VERSION 5.8 ;
BUSBITCHARS "[]" ;
DIVIDERCHAR "/" ;
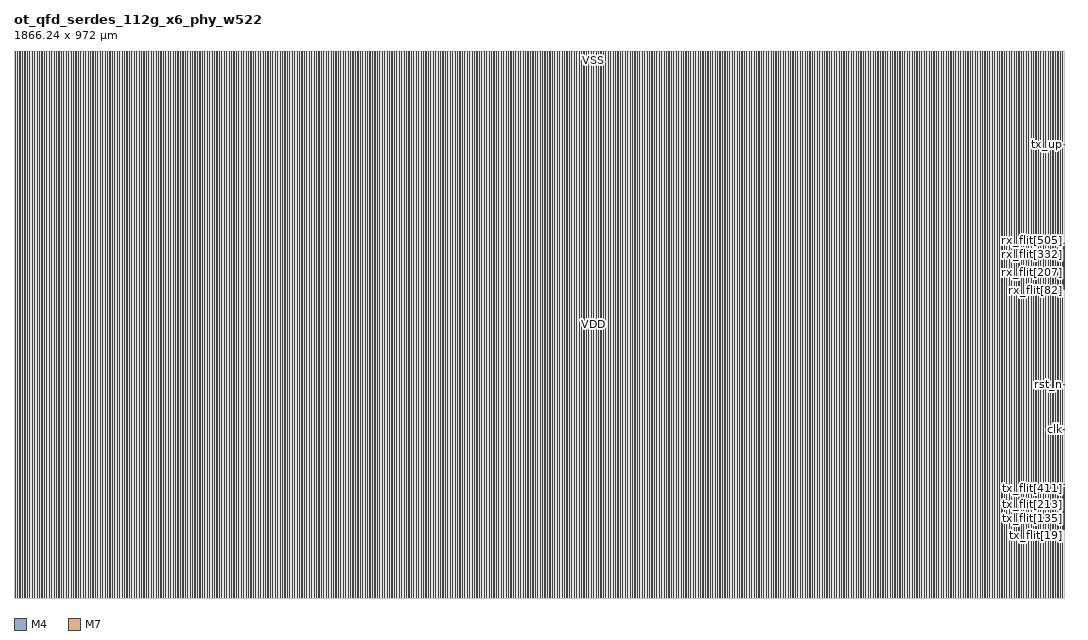
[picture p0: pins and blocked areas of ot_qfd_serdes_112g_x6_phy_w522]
MACRO ot_qfd_serdes_112g_x6_phy_w522
 CLASS BLOCK ;
 ORIGIN 0 0 ;
 SIZE 1866.24 BY 972.0 ;
 SYMMETRY X Y ;
 PIN clk
 DIRECTION INPUT ;
 USE CLOCK ;
 PORT
 LAYER M4 ;
 RECT 1865.760000 300.012000 1866.240000 300.036000 ;
 END
 END clk
 PIN rst_n
 DIRECTION INPUT ;
 USE SIGNAL ;
 PORT
 LAYER M4 ;
 RECT 1865.760000 379.068000 1866.240000 379.092000 ;
 END
 END rst_n
 PIN tx_up
 DIRECTION OUTPUT ;
 USE SIGNAL ;
 PORT
 LAYER M4 ;
 RECT 1865.760000 806.316000 1866.240000 806.340000 ;
 END
 END tx_up
 PIN tx_v
 DIRECTION INPUT ;
 USE SIGNAL ;
 PORT
 LAYER M4 ;
 RECT 1865.760000 201.996000 1866.240000 202.020000 ;
 END
 END tx_v
 PIN tx_flit[0]
 DIRECTION INPUT ;
 USE SIGNAL ;
 PORT
 LAYER M4 ;
 RECT 1865.760000 121.932000 1866.240000 121.956000 ;
 END
 END tx_flit[0]
 PIN tx_flit[1]
 DIRECTION INPUT ;
 USE SIGNAL ;
 PORT
 LAYER M4 ;
 RECT 1865.760000 122.076000 1866.240000 122.100000 ;
 END
 END tx_flit[1]
 PIN tx_flit[2]
 DIRECTION INPUT ;
 USE SIGNAL ;
 PORT
 LAYER M4 ;
 RECT 1865.760000 122.220000 1866.240000 122.244000 ;
 END
 END tx_flit[2]
 PIN tx_flit[3]
 DIRECTION INPUT ;
 USE SIGNAL ;
 PORT
 LAYER M4 ;
 RECT 1865.760000 122.364000 1866.240000 122.388000 ;
 END
 END tx_flit[3]
 PIN tx_flit[4]
 DIRECTION INPUT ;
 USE SIGNAL ;
 PORT
 LAYER M4 ;
 RECT 1865.760000 122.508000 1866.240000 122.532000 ;
 END
 END tx_flit[4]
 PIN tx_flit[5]
 DIRECTION INPUT ;
 USE SIGNAL ;
 PORT
 LAYER M4 ;
 RECT 1865.760000 122.652000 1866.240000 122.676000 ;
 END
 END tx_flit[5]
 PIN tx_flit[6]
 DIRECTION INPUT ;
 USE SIGNAL ;
 PORT
 LAYER M4 ;
 RECT 1865.760000 122.796000 1866.240000 122.820000 ;
 END
 END tx_flit[6]
 PIN tx_flit[7]
 DIRECTION INPUT ;
 USE SIGNAL ;
 PORT
 LAYER M4 ;
 RECT 1865.760000 122.940000 1866.240000 122.964000 ;
 END
 END tx_flit[7]
 PIN tx_flit[8]
 DIRECTION INPUT ;
 USE SIGNAL ;
 PORT
 LAYER M4 ;
 RECT 1865.760000 123.084000 1866.240000 123.108000 ;
 END
 END tx_flit[8]
 PIN tx_flit[9]
 DIRECTION INPUT ;
 USE SIGNAL ;
 PORT
 LAYER M4 ;
 RECT 1865.760000 123.228000 1866.240000 123.252000 ;
 END
 END tx_flit[9]
 PIN tx_flit[10]
 DIRECTION INPUT ;
 USE SIGNAL ;
 PORT
 LAYER M4 ;
 RECT 1865.760000 123.372000 1866.240000 123.396000 ;
 END
 END tx_flit[10]
 PIN tx_flit[11]
 DIRECTION INPUT ;
 USE SIGNAL ;
 PORT
 LAYER M4 ;
 RECT 1865.760000 123.516000 1866.240000 123.540000 ;
 END
 END tx_flit[11]
 PIN tx_flit[12]
 DIRECTION INPUT ;
 USE SIGNAL ;
 PORT
 LAYER M4 ;
 RECT 1865.760000 123.660000 1866.240000 123.684000 ;
 END
 END tx_flit[12]
 PIN tx_flit[13]
 DIRECTION INPUT ;
 USE SIGNAL ;
 PORT
 LAYER M4 ;
 RECT 1865.760000 123.804000 1866.240000 123.828000 ;
 END
 END tx_flit[13]
 PIN tx_flit[14]
 DIRECTION INPUT ;
 USE SIGNAL ;
 PORT
 LAYER M4 ;
 RECT 1865.760000 123.948000 1866.240000 123.972000 ;
 END
 END tx_flit[14]
 PIN tx_flit[15]
 DIRECTION INPUT ;
 USE SIGNAL ;
 PORT
 LAYER M4 ;
 RECT 1865.760000 124.092000 1866.240000 124.116000 ;
 END
 END tx_flit[15]
 PIN tx_flit[16]
 DIRECTION INPUT ;
 USE SIGNAL ;
 PORT
 LAYER M4 ;
 RECT 1865.760000 124.236000 1866.240000 124.260000 ;
 END
 END tx_flit[16]
 PIN tx_flit[17]
 DIRECTION INPUT ;
 USE SIGNAL ;
 PORT
 LAYER M4 ;
 RECT 1865.760000 124.380000 1866.240000 124.404000 ;
 END
 END tx_flit[17]
 PIN tx_flit[18]
 DIRECTION INPUT ;
 USE SIGNAL ;
 PORT
 LAYER M4 ;
 RECT 1865.760000 124.524000 1866.240000 124.548000 ;
 END
 END tx_flit[18]
 PIN tx_flit[19]
 DIRECTION INPUT ;
 USE SIGNAL ;
 PORT
 LAYER M4 ;
 RECT 1865.760000 124.668000 1866.240000 124.692000 ;
 END
 END tx_flit[19]
 PIN tx_flit[20]
 DIRECTION INPUT ;
 USE SIGNAL ;
 PORT
 LAYER M4 ;
 RECT 1865.760000 124.812000 1866.240000 124.836000 ;
 END
 END tx_flit[20]
 PIN tx_flit[21]
 DIRECTION INPUT ;
 USE SIGNAL ;
 PORT
 LAYER M4 ;
 RECT 1865.760000 124.956000 1866.240000 124.980000 ;
 END
 END tx_flit[21]
 PIN tx_flit[22]
 DIRECTION INPUT ;
 USE SIGNAL ;
 PORT
 LAYER M4 ;
 RECT 1865.760000 125.100000 1866.240000 125.124000 ;
 END
 END tx_flit[22]
 PIN tx_flit[23]
 DIRECTION INPUT ;
 USE SIGNAL ;
 PORT
 LAYER M4 ;
 RECT 1865.760000 125.244000 1866.240000 125.268000 ;
 END
 END tx_flit[23]
 PIN tx_flit[24]
 DIRECTION INPUT ;
 USE SIGNAL ;
 PORT
 LAYER M4 ;
 RECT 1865.760000 125.388000 1866.240000 125.412000 ;
 END
 END tx_flit[24]
 PIN tx_flit[25]
 DIRECTION INPUT ;
 USE SIGNAL ;
 PORT
 LAYER M4 ;
 RECT 1865.760000 125.532000 1866.240000 125.556000 ;
 END
 END tx_flit[25]
 PIN tx_flit[26]
 DIRECTION INPUT ;
 USE SIGNAL ;
 PORT
 LAYER M4 ;
 RECT 1865.760000 125.676000 1866.240000 125.700000 ;
 END
 END tx_flit[26]
 PIN tx_flit[27]
 DIRECTION INPUT ;
 USE SIGNAL ;
 PORT
 LAYER M4 ;
 RECT 1865.760000 125.820000 1866.240000 125.844000 ;
 END
 END tx_flit[27]
 PIN tx_flit[28]
 DIRECTION INPUT ;
 USE SIGNAL ;
 PORT
 LAYER M4 ;
 RECT 1865.760000 125.964000 1866.240000 125.988000 ;
 END
 END tx_flit[28]
 PIN tx_flit[29]
 DIRECTION INPUT ;
 USE SIGNAL ;
 PORT
 LAYER M4 ;
 RECT 1865.760000 126.108000 1866.240000 126.132000 ;
 END
 END tx_flit[29]
 PIN tx_flit[30]
 DIRECTION INPUT ;
 USE SIGNAL ;
 PORT
 LAYER M4 ;
 RECT 1865.760000 126.252000 1866.240000 126.276000 ;
 END
 END tx_flit[30]
 PIN tx_flit[31]
 DIRECTION INPUT ;
 USE SIGNAL ;
 PORT
 LAYER M4 ;
 RECT 1865.760000 126.396000 1866.240000 126.420000 ;
 END
 END tx_flit[31]
 PIN tx_flit[32]
 DIRECTION INPUT ;
 USE SIGNAL ;
 PORT
 LAYER M4 ;
 RECT 1865.760000 126.540000 1866.240000 126.564000 ;
 END
 END tx_flit[32]
 PIN tx_flit[33]
 DIRECTION INPUT ;
 USE SIGNAL ;
 PORT
 LAYER M4 ;
 RECT 1865.760000 126.684000 1866.240000 126.708000 ;
 END
 END tx_flit[33]
 PIN tx_flit[34]
 DIRECTION INPUT ;
 USE SIGNAL ;
 PORT
 LAYER M4 ;
 RECT 1865.760000 126.828000 1866.240000 126.852000 ;
 END
 END tx_flit[34]
 PIN tx_flit[35]
 DIRECTION INPUT ;
 USE SIGNAL ;
 PORT
 LAYER M4 ;
 RECT 1865.760000 126.972000 1866.240000 126.996000 ;
 END
 END tx_flit[35]
 PIN tx_flit[36]
 DIRECTION INPUT ;
 USE SIGNAL ;
 PORT
 LAYER M4 ;
 RECT 1865.760000 127.116000 1866.240000 127.140000 ;
 END
 END tx_flit[36]
 PIN tx_flit[37]
 DIRECTION INPUT ;
 USE SIGNAL ;
 PORT
 LAYER M4 ;
 RECT 1865.760000 127.260000 1866.240000 127.284000 ;
 END
 END tx_flit[37]
 PIN tx_flit[38]
 DIRECTION INPUT ;
 USE SIGNAL ;
 PORT
 LAYER M4 ;
 RECT 1865.760000 127.404000 1866.240000 127.428000 ;
 END
 END tx_flit[38]
 PIN tx_flit[39]
 DIRECTION INPUT ;
 USE SIGNAL ;
 PORT
 LAYER M4 ;
 RECT 1865.760000 127.548000 1866.240000 127.572000 ;
 END
 END tx_flit[39]
 PIN tx_flit[40]
 DIRECTION INPUT ;
 USE SIGNAL ;
 PORT
 LAYER M4 ;
 RECT 1865.760000 127.692000 1866.240000 127.716000 ;
 END
 END tx_flit[40]
 PIN tx_flit[41]
 DIRECTION INPUT ;
 USE SIGNAL ;
 PORT
 LAYER M4 ;
 RECT 1865.760000 127.836000 1866.240000 127.860000 ;
 END
 END tx_flit[41]
 PIN tx_flit[42]
 DIRECTION INPUT ;
 USE SIGNAL ;
 PORT
 LAYER M4 ;
 RECT 1865.760000 127.980000 1866.240000 128.004000 ;
 END
 END tx_flit[42]
 PIN tx_flit[43]
 DIRECTION INPUT ;
 USE SIGNAL ;
 PORT
 LAYER M4 ;
 RECT 1865.760000 128.124000 1866.240000 128.148000 ;
 END
 END tx_flit[43]
 PIN tx_flit[44]
 DIRECTION INPUT ;
 USE SIGNAL ;
 PORT
 LAYER M4 ;
 RECT 1865.760000 128.268000 1866.240000 128.292000 ;
 END
 END tx_flit[44]
 PIN tx_flit[45]
 DIRECTION INPUT ;
 USE SIGNAL ;
 PORT
 LAYER M4 ;
 RECT 1865.760000 128.412000 1866.240000 128.436000 ;
 END
 END tx_flit[45]
 PIN tx_flit[46]
 DIRECTION INPUT ;
 USE SIGNAL ;
 PORT
 LAYER M4 ;
 RECT 1865.760000 128.556000 1866.240000 128.580000 ;
 END
 END tx_flit[46]
 PIN tx_flit[47]
 DIRECTION INPUT ;
 USE SIGNAL ;
 PORT
 LAYER M4 ;
 RECT 1865.760000 128.700000 1866.240000 128.724000 ;
 END
 END tx_flit[47]
 PIN tx_flit[48]
 DIRECTION INPUT ;
 USE SIGNAL ;
 PORT
 LAYER M4 ;
 RECT 1865.760000 128.844000 1866.240000 128.868000 ;
 END
 END tx_flit[48]
 PIN tx_flit[49]
 DIRECTION INPUT ;
 USE SIGNAL ;
 PORT
 LAYER M4 ;
 RECT 1865.760000 128.988000 1866.240000 129.012000 ;
 END
 END tx_flit[49]
 PIN tx_flit[50]
 DIRECTION INPUT ;
 USE SIGNAL ;
 PORT
 LAYER M4 ;
 RECT 1865.760000 129.132000 1866.240000 129.156000 ;
 END
 END tx_flit[50]
 PIN tx_flit[51]
 DIRECTION INPUT ;
 USE SIGNAL ;
 PORT
 LAYER M4 ;
 RECT 1865.760000 129.276000 1866.240000 129.300000 ;
 END
 END tx_flit[51]
 PIN tx_flit[52]
 DIRECTION INPUT ;
 USE SIGNAL ;
 PORT
 LAYER M4 ;
 RECT 1865.760000 129.420000 1866.240000 129.444000 ;
 END
 END tx_flit[52]
 PIN tx_flit[53]
 DIRECTION INPUT ;
 USE SIGNAL ;
 PORT
 LAYER M4 ;
 RECT 1865.760000 129.564000 1866.240000 129.588000 ;
 END
 END tx_flit[53]
 PIN tx_flit[54]
 DIRECTION INPUT ;
 USE SIGNAL ;
 PORT
 LAYER M4 ;
 RECT 1865.760000 129.708000 1866.240000 129.732000 ;
 END
 END tx_flit[54]
 PIN tx_flit[55]
 DIRECTION INPUT ;
 USE SIGNAL ;
 PORT
 LAYER M4 ;
 RECT 1865.760000 129.852000 1866.240000 129.876000 ;
 END
 END tx_flit[55]
 PIN tx_flit[56]
 DIRECTION INPUT ;
 USE SIGNAL ;
 PORT
 LAYER M4 ;
 RECT 1865.760000 129.996000 1866.240000 130.020000 ;
 END
 END tx_flit[56]
 PIN tx_flit[57]
 DIRECTION INPUT ;
 USE SIGNAL ;
 PORT
 LAYER M4 ;
 RECT 1865.760000 130.140000 1866.240000 130.164000 ;
 END
 END tx_flit[57]
 PIN tx_flit[58]
 DIRECTION INPUT ;
 USE SIGNAL ;
 PORT
 LAYER M4 ;
 RECT 1865.760000 130.284000 1866.240000 130.308000 ;
 END
 END tx_flit[58]
 PIN tx_flit[59]
 DIRECTION INPUT ;
 USE SIGNAL ;
 PORT
 LAYER M4 ;
 RECT 1865.760000 130.428000 1866.240000 130.452000 ;
 END
 END tx_flit[59]
 PIN tx_flit[60]
 DIRECTION INPUT ;
 USE SIGNAL ;
 PORT
 LAYER M4 ;
 RECT 1865.760000 130.572000 1866.240000 130.596000 ;
 END
 END tx_flit[60]
 PIN tx_flit[61]
 DIRECTION INPUT ;
 USE SIGNAL ;
 PORT
 LAYER M4 ;
 RECT 1865.760000 130.716000 1866.240000 130.740000 ;
 END
 END tx_flit[61]
 PIN tx_flit[62]
 DIRECTION INPUT ;
 USE SIGNAL ;
 PORT
 LAYER M4 ;
 RECT 1865.760000 130.860000 1866.240000 130.884000 ;
 END
 END tx_flit[62]
 PIN tx_flit[63]
 DIRECTION INPUT ;
 USE SIGNAL ;
 PORT
 LAYER M4 ;
 RECT 1865.760000 131.004000 1866.240000 131.028000 ;
 END
 END tx_flit[63]
 PIN tx_flit[64]
 DIRECTION INPUT ;
 USE SIGNAL ;
 PORT
 LAYER M4 ;
 RECT 1865.760000 131.148000 1866.240000 131.172000 ;
 END
 END tx_flit[64]
 PIN tx_flit[65]
 DIRECTION INPUT ;
 USE SIGNAL ;
 PORT
 LAYER M4 ;
 RECT 1865.760000 131.292000 1866.240000 131.316000 ;
 END
 END tx_flit[65]
 PIN tx_flit[66]
 DIRECTION INPUT ;
 USE SIGNAL ;
 PORT
 LAYER M4 ;
 RECT 1865.760000 131.436000 1866.240000 131.460000 ;
 END
 END tx_flit[66]
 PIN tx_flit[67]
 DIRECTION INPUT ;
 USE SIGNAL ;
 PORT
 LAYER M4 ;
 RECT 1865.760000 131.580000 1866.240000 131.604000 ;
 END
 END tx_flit[67]
 PIN tx_flit[68]
 DIRECTION INPUT ;
 USE SIGNAL ;
 PORT
 LAYER M4 ;
 RECT 1865.760000 131.724000 1866.240000 131.748000 ;
 END
 END tx_flit[68]
 PIN tx_flit[69]
 DIRECTION INPUT ;
 USE SIGNAL ;
 PORT
 LAYER M4 ;
 RECT 1865.760000 131.868000 1866.240000 131.892000 ;
 END
 END tx_flit[69]
 PIN tx_flit[70]
 DIRECTION INPUT ;
 USE SIGNAL ;
 PORT
 LAYER M4 ;
 RECT 1865.760000 132.012000 1866.240000 132.036000 ;
 END
 END tx_flit[70]
 PIN tx_flit[71]
 DIRECTION INPUT ;
 USE SIGNAL ;
 PORT
 LAYER M4 ;
 RECT 1865.760000 132.156000 1866.240000 132.180000 ;
 END
 END tx_flit[71]
 PIN tx_flit[72]
 DIRECTION INPUT ;
 USE SIGNAL ;
 PORT
 LAYER M4 ;
 RECT 1865.760000 132.300000 1866.240000 132.324000 ;
 END
 END tx_flit[72]
 PIN tx_flit[73]
 DIRECTION INPUT ;
 USE SIGNAL ;
 PORT
 LAYER M4 ;
 RECT 1865.760000 132.444000 1866.240000 132.468000 ;
 END
 END tx_flit[73]
 PIN tx_flit[74]
 DIRECTION INPUT ;
 USE SIGNAL ;
 PORT
 LAYER M4 ;
 RECT 1865.760000 132.588000 1866.240000 132.612000 ;
 END
 END tx_flit[74]
 PIN tx_flit[75]
 DIRECTION INPUT ;
 USE SIGNAL ;
 PORT
 LAYER M4 ;
 RECT 1865.760000 132.732000 1866.240000 132.756000 ;
 END
 END tx_flit[75]
 PIN tx_flit[76]
 DIRECTION INPUT ;
 USE SIGNAL ;
 PORT
 LAYER M4 ;
 RECT 1865.760000 132.876000 1866.240000 132.900000 ;
 END
 END tx_flit[76]
 PIN tx_flit[77]
 DIRECTION INPUT ;
 USE SIGNAL ;
 PORT
 LAYER M4 ;
 RECT 1865.760000 133.020000 1866.240000 133.044000 ;
 END
 END tx_flit[77]
 PIN tx_flit[78]
 DIRECTION INPUT ;
 USE SIGNAL ;
 PORT
 LAYER M4 ;
 RECT 1865.760000 133.164000 1866.240000 133.188000 ;
 END
 END tx_flit[78]
 PIN tx_flit[79]
 DIRECTION INPUT ;
 USE SIGNAL ;
 PORT
 LAYER M4 ;
 RECT 1865.760000 133.308000 1866.240000 133.332000 ;
 END
 END tx_flit[79]
 PIN tx_flit[80]
 DIRECTION INPUT ;
 USE SIGNAL ;
 PORT
 LAYER M4 ;
 RECT 1865.760000 133.452000 1866.240000 133.476000 ;
 END
 END tx_flit[80]
 PIN tx_flit[81]
 DIRECTION INPUT ;
 USE SIGNAL ;
 PORT
 LAYER M4 ;
 RECT 1865.760000 133.596000 1866.240000 133.620000 ;
 END
 END tx_flit[81]
 PIN tx_flit[82]
 DIRECTION INPUT ;
 USE SIGNAL ;
 PORT
 LAYER M4 ;
 RECT 1865.760000 133.740000 1866.240000 133.764000 ;
 END
 END tx_flit[82]
 PIN tx_flit[83]
 DIRECTION INPUT ;
 USE SIGNAL ;
 PORT
 LAYER M4 ;
 RECT 1865.760000 133.884000 1866.240000 133.908000 ;
 END
 END tx_flit[83]
 PIN tx_flit[84]
 DIRECTION INPUT ;
 USE SIGNAL ;
 PORT
 LAYER M4 ;
 RECT 1865.760000 134.028000 1866.240000 134.052000 ;
 END
 END tx_flit[84]
 PIN tx_flit[85]
 DIRECTION INPUT ;
 USE SIGNAL ;
 PORT
 LAYER M4 ;
 RECT 1865.760000 134.172000 1866.240000 134.196000 ;
 END
 END tx_flit[85]
 PIN tx_flit[86]
 DIRECTION INPUT ;
 USE SIGNAL ;
 PORT
 LAYER M4 ;
 RECT 1865.760000 134.316000 1866.240000 134.340000 ;
 END
 END tx_flit[86]
 PIN tx_flit[87]
 DIRECTION INPUT ;
 USE SIGNAL ;
 PORT
 LAYER M4 ;
 RECT 1865.760000 134.460000 1866.240000 134.484000 ;
 END
 END tx_flit[87]
 PIN tx_flit[88]
 DIRECTION INPUT ;
 USE SIGNAL ;
 PORT
 LAYER M4 ;
 RECT 1865.760000 134.604000 1866.240000 134.628000 ;
 END
 END tx_flit[88]
 PIN tx_flit[89]
 DIRECTION INPUT ;
 USE SIGNAL ;
 PORT
 LAYER M4 ;
 RECT 1865.760000 134.748000 1866.240000 134.772000 ;
 END
 END tx_flit[89]
 PIN tx_flit[90]
 DIRECTION INPUT ;
 USE SIGNAL ;
 PORT
 LAYER M4 ;
 RECT 1865.760000 134.892000 1866.240000 134.916000 ;
 END
 END tx_flit[90]
 PIN tx_flit[91]
 DIRECTION INPUT ;
 USE SIGNAL ;
 PORT
 LAYER M4 ;
 RECT 1865.760000 135.036000 1866.240000 135.060000 ;
 END
 END tx_flit[91]
 PIN tx_flit[92]
 DIRECTION INPUT ;
 USE SIGNAL ;
 PORT
 LAYER M4 ;
 RECT 1865.760000 135.180000 1866.240000 135.204000 ;
 END
 END tx_flit[92]
 PIN tx_flit[93]
 DIRECTION INPUT ;
 USE SIGNAL ;
 PORT
 LAYER M4 ;
 RECT 1865.760000 135.324000 1866.240000 135.348000 ;
 END
 END tx_flit[93]
 PIN tx_flit[94]
 DIRECTION INPUT ;
 USE SIGNAL ;
 PORT
 LAYER M4 ;
 RECT 1865.760000 135.468000 1866.240000 135.492000 ;
 END
 END tx_flit[94]
 PIN tx_flit[95]
 DIRECTION INPUT ;
 USE SIGNAL ;
 PORT
 LAYER M4 ;
 RECT 1865.760000 135.612000 1866.240000 135.636000 ;
 END
 END tx_flit[95]
 PIN tx_flit[96]
 DIRECTION INPUT ;
 USE SIGNAL ;
 PORT
 LAYER M4 ;
 RECT 1865.760000 135.756000 1866.240000 135.780000 ;
 END
 END tx_flit[96]
 PIN tx_flit[97]
 DIRECTION INPUT ;
 USE SIGNAL ;
 PORT
 LAYER M4 ;
 RECT 1865.760000 135.900000 1866.240000 135.924000 ;
 END
 END tx_flit[97]
 PIN tx_flit[98]
 DIRECTION INPUT ;
 USE SIGNAL ;
 PORT
 LAYER M4 ;
 RECT 1865.760000 136.044000 1866.240000 136.068000 ;
 END
 END tx_flit[98]
 PIN tx_flit[99]
 DIRECTION INPUT ;
 USE SIGNAL ;
 PORT
 LAYER M4 ;
 RECT 1865.760000 136.188000 1866.240000 136.212000 ;
 END
 END tx_flit[99]
 PIN tx_flit[100]
 DIRECTION INPUT ;
 USE SIGNAL ;
 PORT
 LAYER M4 ;
 RECT 1865.760000 136.332000 1866.240000 136.356000 ;
 END
 END tx_flit[100]
 PIN tx_flit[101]
 DIRECTION INPUT ;
 USE SIGNAL ;
 PORT
 LAYER M4 ;
 RECT 1865.760000 136.476000 1866.240000 136.500000 ;
 END
 END tx_flit[101]
 PIN tx_flit[102]
 DIRECTION INPUT ;
 USE SIGNAL ;
 PORT
 LAYER M4 ;
 RECT 1865.760000 136.620000 1866.240000 136.644000 ;
 END
 END tx_flit[102]
 PIN tx_flit[103]
 DIRECTION INPUT ;
 USE SIGNAL ;
 PORT
 LAYER M4 ;
 RECT 1865.760000 136.764000 1866.240000 136.788000 ;
 END
 END tx_flit[103]
 PIN tx_flit[104]
 DIRECTION INPUT ;
 USE SIGNAL ;
 PORT
 LAYER M4 ;
 RECT 1865.760000 136.908000 1866.240000 136.932000 ;
 END
 END tx_flit[104]
 PIN tx_flit[105]
 DIRECTION INPUT ;
 USE SIGNAL ;
 PORT
 LAYER M4 ;
 RECT 1865.760000 137.052000 1866.240000 137.076000 ;
 END
 END tx_flit[105]
 PIN tx_flit[106]
 DIRECTION INPUT ;
 USE SIGNAL ;
 PORT
 LAYER M4 ;
 RECT 1865.760000 137.196000 1866.240000 137.220000 ;
 END
 END tx_flit[106]
 PIN tx_flit[107]
 DIRECTION INPUT ;
 USE SIGNAL ;
 PORT
 LAYER M4 ;
 RECT 1865.760000 137.340000 1866.240000 137.364000 ;
 END
 END tx_flit[107]
 PIN tx_flit[108]
 DIRECTION INPUT ;
 USE SIGNAL ;
 PORT
 LAYER M4 ;
 RECT 1865.760000 137.484000 1866.240000 137.508000 ;
 END
 END tx_flit[108]
 PIN tx_flit[109]
 DIRECTION INPUT ;
 USE SIGNAL ;
 PORT
 LAYER M4 ;
 RECT 1865.760000 137.628000 1866.240000 137.652000 ;
 END
 END tx_flit[109]
 PIN tx_flit[110]
 DIRECTION INPUT ;
 USE SIGNAL ;
 PORT
 LAYER M4 ;
 RECT 1865.760000 137.772000 1866.240000 137.796000 ;
 END
 END tx_flit[110]
 PIN tx_flit[111]
 DIRECTION INPUT ;
 USE SIGNAL ;
 PORT
 LAYER M4 ;
 RECT 1865.760000 137.916000 1866.240000 137.940000 ;
 END
 END tx_flit[111]
 PIN tx_flit[112]
 DIRECTION INPUT ;
 USE SIGNAL ;
 PORT
 LAYER M4 ;
 RECT 1865.760000 138.060000 1866.240000 138.084000 ;
 END
 END tx_flit[112]
 PIN tx_flit[113]
 DIRECTION INPUT ;
 USE SIGNAL ;
 PORT
 LAYER M4 ;
 RECT 1865.760000 138.204000 1866.240000 138.228000 ;
 END
 END tx_flit[113]
 PIN tx_flit[114]
 DIRECTION INPUT ;
 USE SIGNAL ;
 PORT
 LAYER M4 ;
 RECT 1865.760000 138.348000 1866.240000 138.372000 ;
 END
 END tx_flit[114]
 PIN tx_flit[115]
 DIRECTION INPUT ;
 USE SIGNAL ;
 PORT
 LAYER M4 ;
 RECT 1865.760000 138.492000 1866.240000 138.516000 ;
 END
 END tx_flit[115]
 PIN tx_flit[116]
 DIRECTION INPUT ;
 USE SIGNAL ;
 PORT
 LAYER M4 ;
 RECT 1865.760000 138.636000 1866.240000 138.660000 ;
 END
 END tx_flit[116]
 PIN tx_flit[117]
 DIRECTION INPUT ;
 USE SIGNAL ;
 PORT
 LAYER M4 ;
 RECT 1865.760000 138.780000 1866.240000 138.804000 ;
 END
 END tx_flit[117]
 PIN tx_flit[118]
 DIRECTION INPUT ;
 USE SIGNAL ;
 PORT
 LAYER M4 ;
 RECT 1865.760000 138.924000 1866.240000 138.948000 ;
 END
 END tx_flit[118]
 PIN tx_flit[119]
 DIRECTION INPUT ;
 USE SIGNAL ;
 PORT
 LAYER M4 ;
 RECT 1865.760000 139.068000 1866.240000 139.092000 ;
 END
 END tx_flit[119]
 PIN tx_flit[120]
 DIRECTION INPUT ;
 USE SIGNAL ;
 PORT
 LAYER M4 ;
 RECT 1865.760000 139.212000 1866.240000 139.236000 ;
 END
 END tx_flit[120]
 PIN tx_flit[121]
 DIRECTION INPUT ;
 USE SIGNAL ;
 PORT
 LAYER M4 ;
 RECT 1865.760000 139.356000 1866.240000 139.380000 ;
 END
 END tx_flit[121]
 PIN tx_flit[122]
 DIRECTION INPUT ;
 USE SIGNAL ;
 PORT
 LAYER M4 ;
 RECT 1865.760000 139.500000 1866.240000 139.524000 ;
 END
 END tx_flit[122]
 PIN tx_flit[123]
 DIRECTION INPUT ;
 USE SIGNAL ;
 PORT
 LAYER M4 ;
 RECT 1865.760000 139.644000 1866.240000 139.668000 ;
 END
 END tx_flit[123]
 PIN tx_flit[124]
 DIRECTION INPUT ;
 USE SIGNAL ;
 PORT
 LAYER M4 ;
 RECT 1865.760000 139.788000 1866.240000 139.812000 ;
 END
 END tx_flit[124]
 PIN tx_flit[125]
 DIRECTION INPUT ;
 USE SIGNAL ;
 PORT
 LAYER M4 ;
 RECT 1865.760000 139.932000 1866.240000 139.956000 ;
 END
 END tx_flit[125]
 PIN tx_flit[126]
 DIRECTION INPUT ;
 USE SIGNAL ;
 PORT
 LAYER M4 ;
 RECT 1865.760000 140.076000 1866.240000 140.100000 ;
 END
 END tx_flit[126]
 PIN tx_flit[127]
 DIRECTION INPUT ;
 USE SIGNAL ;
 PORT
 LAYER M4 ;
 RECT 1865.760000 140.220000 1866.240000 140.244000 ;
 END
 END tx_flit[127]
 PIN tx_flit[128]
 DIRECTION INPUT ;
 USE SIGNAL ;
 PORT
 LAYER M4 ;
 RECT 1865.760000 140.364000 1866.240000 140.388000 ;
 END
 END tx_flit[128]
 PIN tx_flit[129]
 DIRECTION INPUT ;
 USE SIGNAL ;
 PORT
 LAYER M4 ;
 RECT 1865.760000 140.508000 1866.240000 140.532000 ;
 END
 END tx_flit[129]
 PIN tx_flit[130]
 DIRECTION INPUT ;
 USE SIGNAL ;
 PORT
 LAYER M4 ;
 RECT 1865.760000 140.652000 1866.240000 140.676000 ;
 END
 END tx_flit[130]
 PIN tx_flit[131]
 DIRECTION INPUT ;
 USE SIGNAL ;
 PORT
 LAYER M4 ;
 RECT 1865.760000 140.796000 1866.240000 140.820000 ;
 END
 END tx_flit[131]
 PIN tx_flit[132]
 DIRECTION INPUT ;
 USE SIGNAL ;
 PORT
 LAYER M4 ;
 RECT 1865.760000 140.940000 1866.240000 140.964000 ;
 END
 END tx_flit[132]
 PIN tx_flit[133]
 DIRECTION INPUT ;
 USE SIGNAL ;
 PORT
 LAYER M4 ;
 RECT 1865.760000 141.084000 1866.240000 141.108000 ;
 END
 END tx_flit[133]
 PIN tx_flit[134]
 DIRECTION INPUT ;
 USE SIGNAL ;
 PORT
 LAYER M4 ;
 RECT 1865.760000 141.228000 1866.240000 141.252000 ;
 END
 END tx_flit[134]
 PIN tx_flit[135]
 DIRECTION INPUT ;
 USE SIGNAL ;
 PORT
 LAYER M4 ;
 RECT 1865.760000 141.372000 1866.240000 141.396000 ;
 END
 END tx_flit[135]
 PIN tx_flit[136]
 DIRECTION INPUT ;
 USE SIGNAL ;
 PORT
 LAYER M4 ;
 RECT 1865.760000 141.516000 1866.240000 141.540000 ;
 END
 END tx_flit[136]
 PIN tx_flit[137]
 DIRECTION INPUT ;
 USE SIGNAL ;
 PORT
 LAYER M4 ;
 RECT 1865.760000 141.660000 1866.240000 141.684000 ;
 END
 END tx_flit[137]
 PIN tx_flit[138]
 DIRECTION INPUT ;
 USE SIGNAL ;
 PORT
 LAYER M4 ;
 RECT 1865.760000 141.804000 1866.240000 141.828000 ;
 END
 END tx_flit[138]
 PIN tx_flit[139]
 DIRECTION INPUT ;
 USE SIGNAL ;
 PORT
 LAYER M4 ;
 RECT 1865.760000 141.948000 1866.240000 141.972000 ;
 END
 END tx_flit[139]
 PIN tx_flit[140]
 DIRECTION INPUT ;
 USE SIGNAL ;
 PORT
 LAYER M4 ;
 RECT 1865.760000 142.092000 1866.240000 142.116000 ;
 END
 END tx_flit[140]
 PIN tx_flit[141]
 DIRECTION INPUT ;
 USE SIGNAL ;
 PORT
 LAYER M4 ;
 RECT 1865.760000 142.236000 1866.240000 142.260000 ;
 END
 END tx_flit[141]
 PIN tx_flit[142]
 DIRECTION INPUT ;
 USE SIGNAL ;
 PORT
 LAYER M4 ;
 RECT 1865.760000 142.380000 1866.240000 142.404000 ;
 END
 END tx_flit[142]
 PIN tx_flit[143]
 DIRECTION INPUT ;
 USE SIGNAL ;
 PORT
 LAYER M4 ;
 RECT 1865.760000 142.524000 1866.240000 142.548000 ;
 END
 END tx_flit[143]
 PIN tx_flit[144]
 DIRECTION INPUT ;
 USE SIGNAL ;
 PORT
 LAYER M4 ;
 RECT 1865.760000 142.668000 1866.240000 142.692000 ;
 END
 END tx_flit[144]
 PIN tx_flit[145]
 DIRECTION INPUT ;
 USE SIGNAL ;
 PORT
 LAYER M4 ;
 RECT 1865.760000 142.812000 1866.240000 142.836000 ;
 END
 END tx_flit[145]
 PIN tx_flit[146]
 DIRECTION INPUT ;
 USE SIGNAL ;
 PORT
 LAYER M4 ;
 RECT 1865.760000 142.956000 1866.240000 142.980000 ;
 END
 END tx_flit[146]
 PIN tx_flit[147]
 DIRECTION INPUT ;
 USE SIGNAL ;
 PORT
 LAYER M4 ;
 RECT 1865.760000 143.100000 1866.240000 143.124000 ;
 END
 END tx_flit[147]
 PIN tx_flit[148]
 DIRECTION INPUT ;
 USE SIGNAL ;
 PORT
 LAYER M4 ;
 RECT 1865.760000 143.244000 1866.240000 143.268000 ;
 END
 END tx_flit[148]
 PIN tx_flit[149]
 DIRECTION INPUT ;
 USE SIGNAL ;
 PORT
 LAYER M4 ;
 RECT 1865.760000 143.388000 1866.240000 143.412000 ;
 END
 END tx_flit[149]
 PIN tx_flit[150]
 DIRECTION INPUT ;
 USE SIGNAL ;
 PORT
 LAYER M4 ;
 RECT 1865.760000 143.532000 1866.240000 143.556000 ;
 END
 END tx_flit[150]
 PIN tx_flit[151]
 DIRECTION INPUT ;
 USE SIGNAL ;
 PORT
 LAYER M4 ;
 RECT 1865.760000 143.676000 1866.240000 143.700000 ;
 END
 END tx_flit[151]
 PIN tx_flit[152]
 DIRECTION INPUT ;
 USE SIGNAL ;
 PORT
 LAYER M4 ;
 RECT 1865.760000 143.820000 1866.240000 143.844000 ;
 END
 END tx_flit[152]
 PIN tx_flit[153]
 DIRECTION INPUT ;
 USE SIGNAL ;
 PORT
 LAYER M4 ;
 RECT 1865.760000 143.964000 1866.240000 143.988000 ;
 END
 END tx_flit[153]
 PIN tx_flit[154]
 DIRECTION INPUT ;
 USE SIGNAL ;
 PORT
 LAYER M4 ;
 RECT 1865.760000 144.108000 1866.240000 144.132000 ;
 END
 END tx_flit[154]
 PIN tx_flit[155]
 DIRECTION INPUT ;
 USE SIGNAL ;
 PORT
 LAYER M4 ;
 RECT 1865.760000 144.252000 1866.240000 144.276000 ;
 END
 END tx_flit[155]
 PIN tx_flit[156]
 DIRECTION INPUT ;
 USE SIGNAL ;
 PORT
 LAYER M4 ;
 RECT 1865.760000 144.396000 1866.240000 144.420000 ;
 END
 END tx_flit[156]
 PIN tx_flit[157]
 DIRECTION INPUT ;
 USE SIGNAL ;
 PORT
 LAYER M4 ;
 RECT 1865.760000 144.540000 1866.240000 144.564000 ;
 END
 END tx_flit[157]
 PIN tx_flit[158]
 DIRECTION INPUT ;
 USE SIGNAL ;
 PORT
 LAYER M4 ;
 RECT 1865.760000 144.684000 1866.240000 144.708000 ;
 END
 END tx_flit[158]
 PIN tx_flit[159]
 DIRECTION INPUT ;
 USE SIGNAL ;
 PORT
 LAYER M4 ;
 RECT 1865.760000 144.828000 1866.240000 144.852000 ;
 END
 END tx_flit[159]
 PIN tx_flit[160]
 DIRECTION INPUT ;
 USE SIGNAL ;
 PORT
 LAYER M4 ;
 RECT 1865.760000 144.972000 1866.240000 144.996000 ;
 END
 END tx_flit[160]
 PIN tx_flit[161]
 DIRECTION INPUT ;
 USE SIGNAL ;
 PORT
 LAYER M4 ;
 RECT 1865.760000 145.116000 1866.240000 145.140000 ;
 END
 END tx_flit[161]
 PIN tx_flit[162]
 DIRECTION INPUT ;
 USE SIGNAL ;
 PORT
 LAYER M4 ;
 RECT 1865.760000 145.260000 1866.240000 145.284000 ;
 END
 END tx_flit[162]
 PIN tx_flit[163]
 DIRECTION INPUT ;
 USE SIGNAL ;
 PORT
 LAYER M4 ;
 RECT 1865.760000 145.404000 1866.240000 145.428000 ;
 END
 END tx_flit[163]
 PIN tx_flit[164]
 DIRECTION INPUT ;
 USE SIGNAL ;
 PORT
 LAYER M4 ;
 RECT 1865.760000 145.548000 1866.240000 145.572000 ;
 END
 END tx_flit[164]
 PIN tx_flit[165]
 DIRECTION INPUT ;
 USE SIGNAL ;
 PORT
 LAYER M4 ;
 RECT 1865.760000 145.692000 1866.240000 145.716000 ;
 END
 END tx_flit[165]
 PIN tx_flit[166]
 DIRECTION INPUT ;
 USE SIGNAL ;
 PORT
 LAYER M4 ;
 RECT 1865.760000 145.836000 1866.240000 145.860000 ;
 END
 END tx_flit[166]
 PIN tx_flit[167]
 DIRECTION INPUT ;
 USE SIGNAL ;
 PORT
 LAYER M4 ;
 RECT 1865.760000 145.980000 1866.240000 146.004000 ;
 END
 END tx_flit[167]
 PIN tx_flit[168]
 DIRECTION INPUT ;
 USE SIGNAL ;
 PORT
 LAYER M4 ;
 RECT 1865.760000 146.124000 1866.240000 146.148000 ;
 END
 END tx_flit[168]
 PIN tx_flit[169]
 DIRECTION INPUT ;
 USE SIGNAL ;
 PORT
 LAYER M4 ;
 RECT 1865.760000 146.268000 1866.240000 146.292000 ;
 END
 END tx_flit[169]
 PIN tx_flit[170]
 DIRECTION INPUT ;
 USE SIGNAL ;
 PORT
 LAYER M4 ;
 RECT 1865.760000 146.412000 1866.240000 146.436000 ;
 END
 END tx_flit[170]
 PIN tx_flit[171]
 DIRECTION INPUT ;
 USE SIGNAL ;
 PORT
 LAYER M4 ;
 RECT 1865.760000 146.556000 1866.240000 146.580000 ;
 END
 END tx_flit[171]
 PIN tx_flit[172]
 DIRECTION INPUT ;
 USE SIGNAL ;
 PORT
 LAYER M4 ;
 RECT 1865.760000 146.700000 1866.240000 146.724000 ;
 END
 END tx_flit[172]
 PIN tx_flit[173]
 DIRECTION INPUT ;
 USE SIGNAL ;
 PORT
 LAYER M4 ;
 RECT 1865.760000 146.844000 1866.240000 146.868000 ;
 END
 END tx_flit[173]
 PIN tx_flit[174]
 DIRECTION INPUT ;
 USE SIGNAL ;
 PORT
 LAYER M4 ;
 RECT 1865.760000 146.988000 1866.240000 147.012000 ;
 END
 END tx_flit[174]
 PIN tx_flit[175]
 DIRECTION INPUT ;
 USE SIGNAL ;
 PORT
 LAYER M4 ;
 RECT 1865.760000 147.132000 1866.240000 147.156000 ;
 END
 END tx_flit[175]
 PIN tx_flit[176]
 DIRECTION INPUT ;
 USE SIGNAL ;
 PORT
 LAYER M4 ;
 RECT 1865.760000 147.276000 1866.240000 147.300000 ;
 END
 END tx_flit[176]
 PIN tx_flit[177]
 DIRECTION INPUT ;
 USE SIGNAL ;
 PORT
 LAYER M4 ;
 RECT 1865.760000 147.420000 1866.240000 147.444000 ;
 END
 END tx_flit[177]
 PIN tx_flit[178]
 DIRECTION INPUT ;
 USE SIGNAL ;
 PORT
 LAYER M4 ;
 RECT 1865.760000 147.564000 1866.240000 147.588000 ;
 END
 END tx_flit[178]
 PIN tx_flit[179]
 DIRECTION INPUT ;
 USE SIGNAL ;
 PORT
 LAYER M4 ;
 RECT 1865.760000 147.708000 1866.240000 147.732000 ;
 END
 END tx_flit[179]
 PIN tx_flit[180]
 DIRECTION INPUT ;
 USE SIGNAL ;
 PORT
 LAYER M4 ;
 RECT 1865.760000 147.852000 1866.240000 147.876000 ;
 END
 END tx_flit[180]
 PIN tx_flit[181]
 DIRECTION INPUT ;
 USE SIGNAL ;
 PORT
 LAYER M4 ;
 RECT 1865.760000 147.996000 1866.240000 148.020000 ;
 END
 END tx_flit[181]
 PIN tx_flit[182]
 DIRECTION INPUT ;
 USE SIGNAL ;
 PORT
 LAYER M4 ;
 RECT 1865.760000 148.140000 1866.240000 148.164000 ;
 END
 END tx_flit[182]
 PIN tx_flit[183]
 DIRECTION INPUT ;
 USE SIGNAL ;
 PORT
 LAYER M4 ;
 RECT 1865.760000 148.284000 1866.240000 148.308000 ;
 END
 END tx_flit[183]
 PIN tx_flit[184]
 DIRECTION INPUT ;
 USE SIGNAL ;
 PORT
 LAYER M4 ;
 RECT 1865.760000 148.428000 1866.240000 148.452000 ;
 END
 END tx_flit[184]
 PIN tx_flit[185]
 DIRECTION INPUT ;
 USE SIGNAL ;
 PORT
 LAYER M4 ;
 RECT 1865.760000 148.572000 1866.240000 148.596000 ;
 END
 END tx_flit[185]
 PIN tx_flit[186]
 DIRECTION INPUT ;
 USE SIGNAL ;
 PORT
 LAYER M4 ;
 RECT 1865.760000 148.716000 1866.240000 148.740000 ;
 END
 END tx_flit[186]
 PIN tx_flit[187]
 DIRECTION INPUT ;
 USE SIGNAL ;
 PORT
 LAYER M4 ;
 RECT 1865.760000 148.860000 1866.240000 148.884000 ;
 END
 END tx_flit[187]
 PIN tx_flit[188]
 DIRECTION INPUT ;
 USE SIGNAL ;
 PORT
 LAYER M4 ;
 RECT 1865.760000 149.004000 1866.240000 149.028000 ;
 END
 END tx_flit[188]
 PIN tx_flit[189]
 DIRECTION INPUT ;
 USE SIGNAL ;
 PORT
 LAYER M4 ;
 RECT 1865.760000 149.148000 1866.240000 149.172000 ;
 END
 END tx_flit[189]
 PIN tx_flit[190]
 DIRECTION INPUT ;
 USE SIGNAL ;
 PORT
 LAYER M4 ;
 RECT 1865.760000 149.292000 1866.240000 149.316000 ;
 END
 END tx_flit[190]
 PIN tx_flit[191]
 DIRECTION INPUT ;
 USE SIGNAL ;
 PORT
 LAYER M4 ;
 RECT 1865.760000 149.436000 1866.240000 149.460000 ;
 END
 END tx_flit[191]
 PIN tx_flit[192]
 DIRECTION INPUT ;
 USE SIGNAL ;
 PORT
 LAYER M4 ;
 RECT 1865.760000 149.580000 1866.240000 149.604000 ;
 END
 END tx_flit[192]
 PIN tx_flit[193]
 DIRECTION INPUT ;
 USE SIGNAL ;
 PORT
 LAYER M4 ;
 RECT 1865.760000 149.724000 1866.240000 149.748000 ;
 END
 END tx_flit[193]
 PIN tx_flit[194]
 DIRECTION INPUT ;
 USE SIGNAL ;
 PORT
 LAYER M4 ;
 RECT 1865.760000 149.868000 1866.240000 149.892000 ;
 END
 END tx_flit[194]
 PIN tx_flit[195]
 DIRECTION INPUT ;
 USE SIGNAL ;
 PORT
 LAYER M4 ;
 RECT 1865.760000 150.012000 1866.240000 150.036000 ;
 END
 END tx_flit[195]
 PIN tx_flit[196]
 DIRECTION INPUT ;
 USE SIGNAL ;
 PORT
 LAYER M4 ;
 RECT 1865.760000 150.156000 1866.240000 150.180000 ;
 END
 END tx_flit[196]
 PIN tx_flit[197]
 DIRECTION INPUT ;
 USE SIGNAL ;
 PORT
 LAYER M4 ;
 RECT 1865.760000 150.300000 1866.240000 150.324000 ;
 END
 END tx_flit[197]
 PIN tx_flit[198]
 DIRECTION INPUT ;
 USE SIGNAL ;
 PORT
 LAYER M4 ;
 RECT 1865.760000 150.444000 1866.240000 150.468000 ;
 END
 END tx_flit[198]
 PIN tx_flit[199]
 DIRECTION INPUT ;
 USE SIGNAL ;
 PORT
 LAYER M4 ;
 RECT 1865.760000 150.588000 1866.240000 150.612000 ;
 END
 END tx_flit[199]
 PIN tx_flit[200]
 DIRECTION INPUT ;
 USE SIGNAL ;
 PORT
 LAYER M4 ;
 RECT 1865.760000 150.732000 1866.240000 150.756000 ;
 END
 END tx_flit[200]
 PIN tx_flit[201]
 DIRECTION INPUT ;
 USE SIGNAL ;
 PORT
 LAYER M4 ;
 RECT 1865.760000 150.876000 1866.240000 150.900000 ;
 END
 END tx_flit[201]
 PIN tx_flit[202]
 DIRECTION INPUT ;
 USE SIGNAL ;
 PORT
 LAYER M4 ;
 RECT 1865.760000 151.020000 1866.240000 151.044000 ;
 END
 END tx_flit[202]
 PIN tx_flit[203]
 DIRECTION INPUT ;
 USE SIGNAL ;
 PORT
 LAYER M4 ;
 RECT 1865.760000 151.164000 1866.240000 151.188000 ;
 END
 END tx_flit[203]
 PIN tx_flit[204]
 DIRECTION INPUT ;
 USE SIGNAL ;
 PORT
 LAYER M4 ;
 RECT 1865.760000 151.308000 1866.240000 151.332000 ;
 END
 END tx_flit[204]
 PIN tx_flit[205]
 DIRECTION INPUT ;
 USE SIGNAL ;
 PORT
 LAYER M4 ;
 RECT 1865.760000 151.452000 1866.240000 151.476000 ;
 END
 END tx_flit[205]
 PIN tx_flit[206]
 DIRECTION INPUT ;
 USE SIGNAL ;
 PORT
 LAYER M4 ;
 RECT 1865.760000 151.596000 1866.240000 151.620000 ;
 END
 END tx_flit[206]
 PIN tx_flit[207]
 DIRECTION INPUT ;
 USE SIGNAL ;
 PORT
 LAYER M4 ;
 RECT 1865.760000 151.740000 1866.240000 151.764000 ;
 END
 END tx_flit[207]
 PIN tx_flit[208]
 DIRECTION INPUT ;
 USE SIGNAL ;
 PORT
 LAYER M4 ;
 RECT 1865.760000 151.884000 1866.240000 151.908000 ;
 END
 END tx_flit[208]
 PIN tx_flit[209]
 DIRECTION INPUT ;
 USE SIGNAL ;
 PORT
 LAYER M4 ;
 RECT 1865.760000 152.028000 1866.240000 152.052000 ;
 END
 END tx_flit[209]
 PIN tx_flit[210]
 DIRECTION INPUT ;
 USE SIGNAL ;
 PORT
 LAYER M4 ;
 RECT 1865.760000 152.172000 1866.240000 152.196000 ;
 END
 END tx_flit[210]
 PIN tx_flit[211]
 DIRECTION INPUT ;
 USE SIGNAL ;
 PORT
 LAYER M4 ;
 RECT 1865.760000 152.316000 1866.240000 152.340000 ;
 END
 END tx_flit[211]
 PIN tx_flit[212]
 DIRECTION INPUT ;
 USE SIGNAL ;
 PORT
 LAYER M4 ;
 RECT 1865.760000 152.460000 1866.240000 152.484000 ;
 END
 END tx_flit[212]
 PIN tx_flit[213]
 DIRECTION INPUT ;
 USE SIGNAL ;
 PORT
 LAYER M4 ;
 RECT 1865.760000 152.604000 1866.240000 152.628000 ;
 END
 END tx_flit[213]
 PIN tx_flit[214]
 DIRECTION INPUT ;
 USE SIGNAL ;
 PORT
 LAYER M4 ;
 RECT 1865.760000 152.748000 1866.240000 152.772000 ;
 END
 END tx_flit[214]
 PIN tx_flit[215]
 DIRECTION INPUT ;
 USE SIGNAL ;
 PORT
 LAYER M4 ;
 RECT 1865.760000 152.892000 1866.240000 152.916000 ;
 END
 END tx_flit[215]
 PIN tx_flit[216]
 DIRECTION INPUT ;
 USE SIGNAL ;
 PORT
 LAYER M4 ;
 RECT 1865.760000 153.036000 1866.240000 153.060000 ;
 END
 END tx_flit[216]
 PIN tx_flit[217]
 DIRECTION INPUT ;
 USE SIGNAL ;
 PORT
 LAYER M4 ;
 RECT 1865.760000 153.180000 1866.240000 153.204000 ;
 END
 END tx_flit[217]
 PIN tx_flit[218]
 DIRECTION INPUT ;
 USE SIGNAL ;
 PORT
 LAYER M4 ;
 RECT 1865.760000 153.324000 1866.240000 153.348000 ;
 END
 END tx_flit[218]
 PIN tx_flit[219]
 DIRECTION INPUT ;
 USE SIGNAL ;
 PORT
 LAYER M4 ;
 RECT 1865.760000 153.468000 1866.240000 153.492000 ;
 END
 END tx_flit[219]
 PIN tx_flit[220]
 DIRECTION INPUT ;
 USE SIGNAL ;
 PORT
 LAYER M4 ;
 RECT 1865.760000 153.612000 1866.240000 153.636000 ;
 END
 END tx_flit[220]
 PIN tx_flit[221]
 DIRECTION INPUT ;
 USE SIGNAL ;
 PORT
 LAYER M4 ;
 RECT 1865.760000 153.756000 1866.240000 153.780000 ;
 END
 END tx_flit[221]
 PIN tx_flit[222]
 DIRECTION INPUT ;
 USE SIGNAL ;
 PORT
 LAYER M4 ;
 RECT 1865.760000 153.900000 1866.240000 153.924000 ;
 END
 END tx_flit[222]
 PIN tx_flit[223]
 DIRECTION INPUT ;
 USE SIGNAL ;
 PORT
 LAYER M4 ;
 RECT 1865.760000 154.044000 1866.240000 154.068000 ;
 END
 END tx_flit[223]
 PIN tx_flit[224]
 DIRECTION INPUT ;
 USE SIGNAL ;
 PORT
 LAYER M4 ;
 RECT 1865.760000 154.188000 1866.240000 154.212000 ;
 END
 END tx_flit[224]
 PIN tx_flit[225]
 DIRECTION INPUT ;
 USE SIGNAL ;
 PORT
 LAYER M4 ;
 RECT 1865.760000 154.332000 1866.240000 154.356000 ;
 END
 END tx_flit[225]
 PIN tx_flit[226]
 DIRECTION INPUT ;
 USE SIGNAL ;
 PORT
 LAYER M4 ;
 RECT 1865.760000 154.476000 1866.240000 154.500000 ;
 END
 END tx_flit[226]
 PIN tx_flit[227]
 DIRECTION INPUT ;
 USE SIGNAL ;
 PORT
 LAYER M4 ;
 RECT 1865.760000 154.620000 1866.240000 154.644000 ;
 END
 END tx_flit[227]
 PIN tx_flit[228]
 DIRECTION INPUT ;
 USE SIGNAL ;
 PORT
 LAYER M4 ;
 RECT 1865.760000 154.764000 1866.240000 154.788000 ;
 END
 END tx_flit[228]
 PIN tx_flit[229]
 DIRECTION INPUT ;
 USE SIGNAL ;
 PORT
 LAYER M4 ;
 RECT 1865.760000 154.908000 1866.240000 154.932000 ;
 END
 END tx_flit[229]
 PIN tx_flit[230]
 DIRECTION INPUT ;
 USE SIGNAL ;
 PORT
 LAYER M4 ;
 RECT 1865.760000 155.052000 1866.240000 155.076000 ;
 END
 END tx_flit[230]
 PIN tx_flit[231]
 DIRECTION INPUT ;
 USE SIGNAL ;
 PORT
 LAYER M4 ;
 RECT 1865.760000 155.196000 1866.240000 155.220000 ;
 END
 END tx_flit[231]
 PIN tx_flit[232]
 DIRECTION INPUT ;
 USE SIGNAL ;
 PORT
 LAYER M4 ;
 RECT 1865.760000 155.340000 1866.240000 155.364000 ;
 END
 END tx_flit[232]
 PIN tx_flit[233]
 DIRECTION INPUT ;
 USE SIGNAL ;
 PORT
 LAYER M4 ;
 RECT 1865.760000 155.484000 1866.240000 155.508000 ;
 END
 END tx_flit[233]
 PIN tx_flit[234]
 DIRECTION INPUT ;
 USE SIGNAL ;
 PORT
 LAYER M4 ;
 RECT 1865.760000 155.628000 1866.240000 155.652000 ;
 END
 END tx_flit[234]
 PIN tx_flit[235]
 DIRECTION INPUT ;
 USE SIGNAL ;
 PORT
 LAYER M4 ;
 RECT 1865.760000 155.772000 1866.240000 155.796000 ;
 END
 END tx_flit[235]
 PIN tx_flit[236]
 DIRECTION INPUT ;
 USE SIGNAL ;
 PORT
 LAYER M4 ;
 RECT 1865.760000 155.916000 1866.240000 155.940000 ;
 END
 END tx_flit[236]
 PIN tx_flit[237]
 DIRECTION INPUT ;
 USE SIGNAL ;
 PORT
 LAYER M4 ;
 RECT 1865.760000 156.060000 1866.240000 156.084000 ;
 END
 END tx_flit[237]
 PIN tx_flit[238]
 DIRECTION INPUT ;
 USE SIGNAL ;
 PORT
 LAYER M4 ;
 RECT 1865.760000 156.204000 1866.240000 156.228000 ;
 END
 END tx_flit[238]
 PIN tx_flit[239]
 DIRECTION INPUT ;
 USE SIGNAL ;
 PORT
 LAYER M4 ;
 RECT 1865.760000 156.348000 1866.240000 156.372000 ;
 END
 END tx_flit[239]
 PIN tx_flit[240]
 DIRECTION INPUT ;
 USE SIGNAL ;
 PORT
 LAYER M4 ;
 RECT 1865.760000 156.492000 1866.240000 156.516000 ;
 END
 END tx_flit[240]
 PIN tx_flit[241]
 DIRECTION INPUT ;
 USE SIGNAL ;
 PORT
 LAYER M4 ;
 RECT 1865.760000 156.636000 1866.240000 156.660000 ;
 END
 END tx_flit[241]
 PIN tx_flit[242]
 DIRECTION INPUT ;
 USE SIGNAL ;
 PORT
 LAYER M4 ;
 RECT 1865.760000 156.780000 1866.240000 156.804000 ;
 END
 END tx_flit[242]
 PIN tx_flit[243]
 DIRECTION INPUT ;
 USE SIGNAL ;
 PORT
 LAYER M4 ;
 RECT 1865.760000 156.924000 1866.240000 156.948000 ;
 END
 END tx_flit[243]
 PIN tx_flit[244]
 DIRECTION INPUT ;
 USE SIGNAL ;
 PORT
 LAYER M4 ;
 RECT 1865.760000 157.068000 1866.240000 157.092000 ;
 END
 END tx_flit[244]
 PIN tx_flit[245]
 DIRECTION INPUT ;
 USE SIGNAL ;
 PORT
 LAYER M4 ;
 RECT 1865.760000 157.212000 1866.240000 157.236000 ;
 END
 END tx_flit[245]
 PIN tx_flit[246]
 DIRECTION INPUT ;
 USE SIGNAL ;
 PORT
 LAYER M4 ;
 RECT 1865.760000 157.356000 1866.240000 157.380000 ;
 END
 END tx_flit[246]
 PIN tx_flit[247]
 DIRECTION INPUT ;
 USE SIGNAL ;
 PORT
 LAYER M4 ;
 RECT 1865.760000 157.500000 1866.240000 157.524000 ;
 END
 END tx_flit[247]
 PIN tx_flit[248]
 DIRECTION INPUT ;
 USE SIGNAL ;
 PORT
 LAYER M4 ;
 RECT 1865.760000 157.644000 1866.240000 157.668000 ;
 END
 END tx_flit[248]
 PIN tx_flit[249]
 DIRECTION INPUT ;
 USE SIGNAL ;
 PORT
 LAYER M4 ;
 RECT 1865.760000 157.788000 1866.240000 157.812000 ;
 END
 END tx_flit[249]
 PIN tx_flit[250]
 DIRECTION INPUT ;
 USE SIGNAL ;
 PORT
 LAYER M4 ;
 RECT 1865.760000 157.932000 1866.240000 157.956000 ;
 END
 END tx_flit[250]
 PIN tx_flit[251]
 DIRECTION INPUT ;
 USE SIGNAL ;
 PORT
 LAYER M4 ;
 RECT 1865.760000 158.076000 1866.240000 158.100000 ;
 END
 END tx_flit[251]
 PIN tx_flit[252]
 DIRECTION INPUT ;
 USE SIGNAL ;
 PORT
 LAYER M4 ;
 RECT 1865.760000 158.220000 1866.240000 158.244000 ;
 END
 END tx_flit[252]
 PIN tx_flit[253]
 DIRECTION INPUT ;
 USE SIGNAL ;
 PORT
 LAYER M4 ;
 RECT 1865.760000 158.364000 1866.240000 158.388000 ;
 END
 END tx_flit[253]
 PIN tx_flit[254]
 DIRECTION INPUT ;
 USE SIGNAL ;
 PORT
 LAYER M4 ;
 RECT 1865.760000 158.508000 1866.240000 158.532000 ;
 END
 END tx_flit[254]
 PIN tx_flit[255]
 DIRECTION INPUT ;
 USE SIGNAL ;
 PORT
 LAYER M4 ;
 RECT 1865.760000 158.652000 1866.240000 158.676000 ;
 END
 END tx_flit[255]
 PIN tx_flit[256]
 DIRECTION INPUT ;
 USE SIGNAL ;
 PORT
 LAYER M4 ;
 RECT 1865.760000 158.796000 1866.240000 158.820000 ;
 END
 END tx_flit[256]
 PIN tx_flit[257]
 DIRECTION INPUT ;
 USE SIGNAL ;
 PORT
 LAYER M4 ;
 RECT 1865.760000 158.940000 1866.240000 158.964000 ;
 END
 END tx_flit[257]
 PIN tx_flit[258]
 DIRECTION INPUT ;
 USE SIGNAL ;
 PORT
 LAYER M4 ;
 RECT 1865.760000 159.084000 1866.240000 159.108000 ;
 END
 END tx_flit[258]
 PIN tx_flit[259]
 DIRECTION INPUT ;
 USE SIGNAL ;
 PORT
 LAYER M4 ;
 RECT 1865.760000 159.228000 1866.240000 159.252000 ;
 END
 END tx_flit[259]
 PIN tx_flit[260]
 DIRECTION INPUT ;
 USE SIGNAL ;
 PORT
 LAYER M4 ;
 RECT 1865.760000 159.372000 1866.240000 159.396000 ;
 END
 END tx_flit[260]
 PIN tx_flit[261]
 DIRECTION INPUT ;
 USE SIGNAL ;
 PORT
 LAYER M4 ;
 RECT 1865.760000 159.516000 1866.240000 159.540000 ;
 END
 END tx_flit[261]
 PIN tx_flit[262]
 DIRECTION INPUT ;
 USE SIGNAL ;
 PORT
 LAYER M4 ;
 RECT 1865.760000 159.660000 1866.240000 159.684000 ;
 END
 END tx_flit[262]
 PIN tx_flit[263]
 DIRECTION INPUT ;
 USE SIGNAL ;
 PORT
 LAYER M4 ;
 RECT 1865.760000 159.804000 1866.240000 159.828000 ;
 END
 END tx_flit[263]
 PIN tx_flit[264]
 DIRECTION INPUT ;
 USE SIGNAL ;
 PORT
 LAYER M4 ;
 RECT 1865.760000 159.948000 1866.240000 159.972000 ;
 END
 END tx_flit[264]
 PIN tx_flit[265]
 DIRECTION INPUT ;
 USE SIGNAL ;
 PORT
 LAYER M4 ;
 RECT 1865.760000 160.092000 1866.240000 160.116000 ;
 END
 END tx_flit[265]
 PIN tx_flit[266]
 DIRECTION INPUT ;
 USE SIGNAL ;
 PORT
 LAYER M4 ;
 RECT 1865.760000 160.236000 1866.240000 160.260000 ;
 END
 END tx_flit[266]
 PIN tx_flit[267]
 DIRECTION INPUT ;
 USE SIGNAL ;
 PORT
 LAYER M4 ;
 RECT 1865.760000 160.380000 1866.240000 160.404000 ;
 END
 END tx_flit[267]
 PIN tx_flit[268]
 DIRECTION INPUT ;
 USE SIGNAL ;
 PORT
 LAYER M4 ;
 RECT 1865.760000 160.524000 1866.240000 160.548000 ;
 END
 END tx_flit[268]
 PIN tx_flit[269]
 DIRECTION INPUT ;
 USE SIGNAL ;
 PORT
 LAYER M4 ;
 RECT 1865.760000 160.668000 1866.240000 160.692000 ;
 END
 END tx_flit[269]
 PIN tx_flit[270]
 DIRECTION INPUT ;
 USE SIGNAL ;
 PORT
 LAYER M4 ;
 RECT 1865.760000 160.812000 1866.240000 160.836000 ;
 END
 END tx_flit[270]
 PIN tx_flit[271]
 DIRECTION INPUT ;
 USE SIGNAL ;
 PORT
 LAYER M4 ;
 RECT 1865.760000 160.956000 1866.240000 160.980000 ;
 END
 END tx_flit[271]
 PIN tx_flit[272]
 DIRECTION INPUT ;
 USE SIGNAL ;
 PORT
 LAYER M4 ;
 RECT 1865.760000 161.100000 1866.240000 161.124000 ;
 END
 END tx_flit[272]
 PIN tx_flit[273]
 DIRECTION INPUT ;
 USE SIGNAL ;
 PORT
 LAYER M4 ;
 RECT 1865.760000 161.244000 1866.240000 161.268000 ;
 END
 END tx_flit[273]
 PIN tx_flit[274]
 DIRECTION INPUT ;
 USE SIGNAL ;
 PORT
 LAYER M4 ;
 RECT 1865.760000 161.388000 1866.240000 161.412000 ;
 END
 END tx_flit[274]
 PIN tx_flit[275]
 DIRECTION INPUT ;
 USE SIGNAL ;
 PORT
 LAYER M4 ;
 RECT 1865.760000 161.532000 1866.240000 161.556000 ;
 END
 END tx_flit[275]
 PIN tx_flit[276]
 DIRECTION INPUT ;
 USE SIGNAL ;
 PORT
 LAYER M4 ;
 RECT 1865.760000 161.676000 1866.240000 161.700000 ;
 END
 END tx_flit[276]
 PIN tx_flit[277]
 DIRECTION INPUT ;
 USE SIGNAL ;
 PORT
 LAYER M4 ;
 RECT 1865.760000 161.820000 1866.240000 161.844000 ;
 END
 END tx_flit[277]
 PIN tx_flit[278]
 DIRECTION INPUT ;
 USE SIGNAL ;
 PORT
 LAYER M4 ;
 RECT 1865.760000 161.964000 1866.240000 161.988000 ;
 END
 END tx_flit[278]
 PIN tx_flit[279]
 DIRECTION INPUT ;
 USE SIGNAL ;
 PORT
 LAYER M4 ;
 RECT 1865.760000 162.108000 1866.240000 162.132000 ;
 END
 END tx_flit[279]
 PIN tx_flit[280]
 DIRECTION INPUT ;
 USE SIGNAL ;
 PORT
 LAYER M4 ;
 RECT 1865.760000 162.252000 1866.240000 162.276000 ;
 END
 END tx_flit[280]
 PIN tx_flit[281]
 DIRECTION INPUT ;
 USE SIGNAL ;
 PORT
 LAYER M4 ;
 RECT 1865.760000 162.396000 1866.240000 162.420000 ;
 END
 END tx_flit[281]
 PIN tx_flit[282]
 DIRECTION INPUT ;
 USE SIGNAL ;
 PORT
 LAYER M4 ;
 RECT 1865.760000 162.540000 1866.240000 162.564000 ;
 END
 END tx_flit[282]
 PIN tx_flit[283]
 DIRECTION INPUT ;
 USE SIGNAL ;
 PORT
 LAYER M4 ;
 RECT 1865.760000 162.684000 1866.240000 162.708000 ;
 END
 END tx_flit[283]
 PIN tx_flit[284]
 DIRECTION INPUT ;
 USE SIGNAL ;
 PORT
 LAYER M4 ;
 RECT 1865.760000 162.828000 1866.240000 162.852000 ;
 END
 END tx_flit[284]
 PIN tx_flit[285]
 DIRECTION INPUT ;
 USE SIGNAL ;
 PORT
 LAYER M4 ;
 RECT 1865.760000 162.972000 1866.240000 162.996000 ;
 END
 END tx_flit[285]
 PIN tx_flit[286]
 DIRECTION INPUT ;
 USE SIGNAL ;
 PORT
 LAYER M4 ;
 RECT 1865.760000 163.116000 1866.240000 163.140000 ;
 END
 END tx_flit[286]
 PIN tx_flit[287]
 DIRECTION INPUT ;
 USE SIGNAL ;
 PORT
 LAYER M4 ;
 RECT 1865.760000 163.260000 1866.240000 163.284000 ;
 END
 END tx_flit[287]
 PIN tx_flit[288]
 DIRECTION INPUT ;
 USE SIGNAL ;
 PORT
 LAYER M4 ;
 RECT 1865.760000 163.404000 1866.240000 163.428000 ;
 END
 END tx_flit[288]
 PIN tx_flit[289]
 DIRECTION INPUT ;
 USE SIGNAL ;
 PORT
 LAYER M4 ;
 RECT 1865.760000 163.548000 1866.240000 163.572000 ;
 END
 END tx_flit[289]
 PIN tx_flit[290]
 DIRECTION INPUT ;
 USE SIGNAL ;
 PORT
 LAYER M4 ;
 RECT 1865.760000 163.692000 1866.240000 163.716000 ;
 END
 END tx_flit[290]
 PIN tx_flit[291]
 DIRECTION INPUT ;
 USE SIGNAL ;
 PORT
 LAYER M4 ;
 RECT 1865.760000 163.836000 1866.240000 163.860000 ;
 END
 END tx_flit[291]
 PIN tx_flit[292]
 DIRECTION INPUT ;
 USE SIGNAL ;
 PORT
 LAYER M4 ;
 RECT 1865.760000 163.980000 1866.240000 164.004000 ;
 END
 END tx_flit[292]
 PIN tx_flit[293]
 DIRECTION INPUT ;
 USE SIGNAL ;
 PORT
 LAYER M4 ;
 RECT 1865.760000 164.124000 1866.240000 164.148000 ;
 END
 END tx_flit[293]
 PIN tx_flit[294]
 DIRECTION INPUT ;
 USE SIGNAL ;
 PORT
 LAYER M4 ;
 RECT 1865.760000 164.268000 1866.240000 164.292000 ;
 END
 END tx_flit[294]
 PIN tx_flit[295]
 DIRECTION INPUT ;
 USE SIGNAL ;
 PORT
 LAYER M4 ;
 RECT 1865.760000 164.412000 1866.240000 164.436000 ;
 END
 END tx_flit[295]
 PIN tx_flit[296]
 DIRECTION INPUT ;
 USE SIGNAL ;
 PORT
 LAYER M4 ;
 RECT 1865.760000 164.556000 1866.240000 164.580000 ;
 END
 END tx_flit[296]
 PIN tx_flit[297]
 DIRECTION INPUT ;
 USE SIGNAL ;
 PORT
 LAYER M4 ;
 RECT 1865.760000 164.700000 1866.240000 164.724000 ;
 END
 END tx_flit[297]
 PIN tx_flit[298]
 DIRECTION INPUT ;
 USE SIGNAL ;
 PORT
 LAYER M4 ;
 RECT 1865.760000 164.844000 1866.240000 164.868000 ;
 END
 END tx_flit[298]
 PIN tx_flit[299]
 DIRECTION INPUT ;
 USE SIGNAL ;
 PORT
 LAYER M4 ;
 RECT 1865.760000 164.988000 1866.240000 165.012000 ;
 END
 END tx_flit[299]
 PIN tx_flit[300]
 DIRECTION INPUT ;
 USE SIGNAL ;
 PORT
 LAYER M4 ;
 RECT 1865.760000 165.132000 1866.240000 165.156000 ;
 END
 END tx_flit[300]
 PIN tx_flit[301]
 DIRECTION INPUT ;
 USE SIGNAL ;
 PORT
 LAYER M4 ;
 RECT 1865.760000 165.276000 1866.240000 165.300000 ;
 END
 END tx_flit[301]
 PIN tx_flit[302]
 DIRECTION INPUT ;
 USE SIGNAL ;
 PORT
 LAYER M4 ;
 RECT 1865.760000 165.420000 1866.240000 165.444000 ;
 END
 END tx_flit[302]
 PIN tx_flit[303]
 DIRECTION INPUT ;
 USE SIGNAL ;
 PORT
 LAYER M4 ;
 RECT 1865.760000 165.564000 1866.240000 165.588000 ;
 END
 END tx_flit[303]
 PIN tx_flit[304]
 DIRECTION INPUT ;
 USE SIGNAL ;
 PORT
 LAYER M4 ;
 RECT 1865.760000 165.708000 1866.240000 165.732000 ;
 END
 END tx_flit[304]
 PIN tx_flit[305]
 DIRECTION INPUT ;
 USE SIGNAL ;
 PORT
 LAYER M4 ;
 RECT 1865.760000 165.852000 1866.240000 165.876000 ;
 END
 END tx_flit[305]
 PIN tx_flit[306]
 DIRECTION INPUT ;
 USE SIGNAL ;
 PORT
 LAYER M4 ;
 RECT 1865.760000 165.996000 1866.240000 166.020000 ;
 END
 END tx_flit[306]
 PIN tx_flit[307]
 DIRECTION INPUT ;
 USE SIGNAL ;
 PORT
 LAYER M4 ;
 RECT 1865.760000 166.140000 1866.240000 166.164000 ;
 END
 END tx_flit[307]
 PIN tx_flit[308]
 DIRECTION INPUT ;
 USE SIGNAL ;
 PORT
 LAYER M4 ;
 RECT 1865.760000 166.284000 1866.240000 166.308000 ;
 END
 END tx_flit[308]
 PIN tx_flit[309]
 DIRECTION INPUT ;
 USE SIGNAL ;
 PORT
 LAYER M4 ;
 RECT 1865.760000 166.428000 1866.240000 166.452000 ;
 END
 END tx_flit[309]
 PIN tx_flit[310]
 DIRECTION INPUT ;
 USE SIGNAL ;
 PORT
 LAYER M4 ;
 RECT 1865.760000 166.572000 1866.240000 166.596000 ;
 END
 END tx_flit[310]
 PIN tx_flit[311]
 DIRECTION INPUT ;
 USE SIGNAL ;
 PORT
 LAYER M4 ;
 RECT 1865.760000 166.716000 1866.240000 166.740000 ;
 END
 END tx_flit[311]
 PIN tx_flit[312]
 DIRECTION INPUT ;
 USE SIGNAL ;
 PORT
 LAYER M4 ;
 RECT 1865.760000 166.860000 1866.240000 166.884000 ;
 END
 END tx_flit[312]
 PIN tx_flit[313]
 DIRECTION INPUT ;
 USE SIGNAL ;
 PORT
 LAYER M4 ;
 RECT 1865.760000 167.004000 1866.240000 167.028000 ;
 END
 END tx_flit[313]
 PIN tx_flit[314]
 DIRECTION INPUT ;
 USE SIGNAL ;
 PORT
 LAYER M4 ;
 RECT 1865.760000 167.148000 1866.240000 167.172000 ;
 END
 END tx_flit[314]
 PIN tx_flit[315]
 DIRECTION INPUT ;
 USE SIGNAL ;
 PORT
 LAYER M4 ;
 RECT 1865.760000 167.292000 1866.240000 167.316000 ;
 END
 END tx_flit[315]
 PIN tx_flit[316]
 DIRECTION INPUT ;
 USE SIGNAL ;
 PORT
 LAYER M4 ;
 RECT 1865.760000 167.436000 1866.240000 167.460000 ;
 END
 END tx_flit[316]
 PIN tx_flit[317]
 DIRECTION INPUT ;
 USE SIGNAL ;
 PORT
 LAYER M4 ;
 RECT 1865.760000 167.580000 1866.240000 167.604000 ;
 END
 END tx_flit[317]
 PIN tx_flit[318]
 DIRECTION INPUT ;
 USE SIGNAL ;
 PORT
 LAYER M4 ;
 RECT 1865.760000 167.724000 1866.240000 167.748000 ;
 END
 END tx_flit[318]
 PIN tx_flit[319]
 DIRECTION INPUT ;
 USE SIGNAL ;
 PORT
 LAYER M4 ;
 RECT 1865.760000 167.868000 1866.240000 167.892000 ;
 END
 END tx_flit[319]
 PIN tx_flit[320]
 DIRECTION INPUT ;
 USE SIGNAL ;
 PORT
 LAYER M4 ;
 RECT 1865.760000 168.012000 1866.240000 168.036000 ;
 END
 END tx_flit[320]
 PIN tx_flit[321]
 DIRECTION INPUT ;
 USE SIGNAL ;
 PORT
 LAYER M4 ;
 RECT 1865.760000 168.156000 1866.240000 168.180000 ;
 END
 END tx_flit[321]
 PIN tx_flit[322]
 DIRECTION INPUT ;
 USE SIGNAL ;
 PORT
 LAYER M4 ;
 RECT 1865.760000 168.300000 1866.240000 168.324000 ;
 END
 END tx_flit[322]
 PIN tx_flit[323]
 DIRECTION INPUT ;
 USE SIGNAL ;
 PORT
 LAYER M4 ;
 RECT 1865.760000 168.444000 1866.240000 168.468000 ;
 END
 END tx_flit[323]
 PIN tx_flit[324]
 DIRECTION INPUT ;
 USE SIGNAL ;
 PORT
 LAYER M4 ;
 RECT 1865.760000 168.588000 1866.240000 168.612000 ;
 END
 END tx_flit[324]
 PIN tx_flit[325]
 DIRECTION INPUT ;
 USE SIGNAL ;
 PORT
 LAYER M4 ;
 RECT 1865.760000 168.732000 1866.240000 168.756000 ;
 END
 END tx_flit[325]
 PIN tx_flit[326]
 DIRECTION INPUT ;
 USE SIGNAL ;
 PORT
 LAYER M4 ;
 RECT 1865.760000 168.876000 1866.240000 168.900000 ;
 END
 END tx_flit[326]
 PIN tx_flit[327]
 DIRECTION INPUT ;
 USE SIGNAL ;
 PORT
 LAYER M4 ;
 RECT 1865.760000 169.020000 1866.240000 169.044000 ;
 END
 END tx_flit[327]
 PIN tx_flit[328]
 DIRECTION INPUT ;
 USE SIGNAL ;
 PORT
 LAYER M4 ;
 RECT 1865.760000 169.164000 1866.240000 169.188000 ;
 END
 END tx_flit[328]
 PIN tx_flit[329]
 DIRECTION INPUT ;
 USE SIGNAL ;
 PORT
 LAYER M4 ;
 RECT 1865.760000 169.308000 1866.240000 169.332000 ;
 END
 END tx_flit[329]
 PIN tx_flit[330]
 DIRECTION INPUT ;
 USE SIGNAL ;
 PORT
 LAYER M4 ;
 RECT 1865.760000 169.452000 1866.240000 169.476000 ;
 END
 END tx_flit[330]
 PIN tx_flit[331]
 DIRECTION INPUT ;
 USE SIGNAL ;
 PORT
 LAYER M4 ;
 RECT 1865.760000 169.596000 1866.240000 169.620000 ;
 END
 END tx_flit[331]
 PIN tx_flit[332]
 DIRECTION INPUT ;
 USE SIGNAL ;
 PORT
 LAYER M4 ;
 RECT 1865.760000 169.740000 1866.240000 169.764000 ;
 END
 END tx_flit[332]
 PIN tx_flit[333]
 DIRECTION INPUT ;
 USE SIGNAL ;
 PORT
 LAYER M4 ;
 RECT 1865.760000 169.884000 1866.240000 169.908000 ;
 END
 END tx_flit[333]
 PIN tx_flit[334]
 DIRECTION INPUT ;
 USE SIGNAL ;
 PORT
 LAYER M4 ;
 RECT 1865.760000 170.028000 1866.240000 170.052000 ;
 END
 END tx_flit[334]
 PIN tx_flit[335]
 DIRECTION INPUT ;
 USE SIGNAL ;
 PORT
 LAYER M4 ;
 RECT 1865.760000 170.172000 1866.240000 170.196000 ;
 END
 END tx_flit[335]
 PIN tx_flit[336]
 DIRECTION INPUT ;
 USE SIGNAL ;
 PORT
 LAYER M4 ;
 RECT 1865.760000 170.316000 1866.240000 170.340000 ;
 END
 END tx_flit[336]
 PIN tx_flit[337]
 DIRECTION INPUT ;
 USE SIGNAL ;
 PORT
 LAYER M4 ;
 RECT 1865.760000 170.460000 1866.240000 170.484000 ;
 END
 END tx_flit[337]
 PIN tx_flit[338]
 DIRECTION INPUT ;
 USE SIGNAL ;
 PORT
 LAYER M4 ;
 RECT 1865.760000 170.604000 1866.240000 170.628000 ;
 END
 END tx_flit[338]
 PIN tx_flit[339]
 DIRECTION INPUT ;
 USE SIGNAL ;
 PORT
 LAYER M4 ;
 RECT 1865.760000 170.748000 1866.240000 170.772000 ;
 END
 END tx_flit[339]
 PIN tx_flit[340]
 DIRECTION INPUT ;
 USE SIGNAL ;
 PORT
 LAYER M4 ;
 RECT 1865.760000 170.892000 1866.240000 170.916000 ;
 END
 END tx_flit[340]
 PIN tx_flit[341]
 DIRECTION INPUT ;
 USE SIGNAL ;
 PORT
 LAYER M4 ;
 RECT 1865.760000 171.036000 1866.240000 171.060000 ;
 END
 END tx_flit[341]
 PIN tx_flit[342]
 DIRECTION INPUT ;
 USE SIGNAL ;
 PORT
 LAYER M4 ;
 RECT 1865.760000 171.180000 1866.240000 171.204000 ;
 END
 END tx_flit[342]
 PIN tx_flit[343]
 DIRECTION INPUT ;
 USE SIGNAL ;
 PORT
 LAYER M4 ;
 RECT 1865.760000 171.324000 1866.240000 171.348000 ;
 END
 END tx_flit[343]
 PIN tx_flit[344]
 DIRECTION INPUT ;
 USE SIGNAL ;
 PORT
 LAYER M4 ;
 RECT 1865.760000 171.468000 1866.240000 171.492000 ;
 END
 END tx_flit[344]
 PIN tx_flit[345]
 DIRECTION INPUT ;
 USE SIGNAL ;
 PORT
 LAYER M4 ;
 RECT 1865.760000 171.612000 1866.240000 171.636000 ;
 END
 END tx_flit[345]
 PIN tx_flit[346]
 DIRECTION INPUT ;
 USE SIGNAL ;
 PORT
 LAYER M4 ;
 RECT 1865.760000 171.756000 1866.240000 171.780000 ;
 END
 END tx_flit[346]
 PIN tx_flit[347]
 DIRECTION INPUT ;
 USE SIGNAL ;
 PORT
 LAYER M4 ;
 RECT 1865.760000 171.900000 1866.240000 171.924000 ;
 END
 END tx_flit[347]
 PIN tx_flit[348]
 DIRECTION INPUT ;
 USE SIGNAL ;
 PORT
 LAYER M4 ;
 RECT 1865.760000 172.044000 1866.240000 172.068000 ;
 END
 END tx_flit[348]
 PIN tx_flit[349]
 DIRECTION INPUT ;
 USE SIGNAL ;
 PORT
 LAYER M4 ;
 RECT 1865.760000 172.188000 1866.240000 172.212000 ;
 END
 END tx_flit[349]
 PIN tx_flit[350]
 DIRECTION INPUT ;
 USE SIGNAL ;
 PORT
 LAYER M4 ;
 RECT 1865.760000 172.332000 1866.240000 172.356000 ;
 END
 END tx_flit[350]
 PIN tx_flit[351]
 DIRECTION INPUT ;
 USE SIGNAL ;
 PORT
 LAYER M4 ;
 RECT 1865.760000 172.476000 1866.240000 172.500000 ;
 END
 END tx_flit[351]
 PIN tx_flit[352]
 DIRECTION INPUT ;
 USE SIGNAL ;
 PORT
 LAYER M4 ;
 RECT 1865.760000 172.620000 1866.240000 172.644000 ;
 END
 END tx_flit[352]
 PIN tx_flit[353]
 DIRECTION INPUT ;
 USE SIGNAL ;
 PORT
 LAYER M4 ;
 RECT 1865.760000 172.764000 1866.240000 172.788000 ;
 END
 END tx_flit[353]
 PIN tx_flit[354]
 DIRECTION INPUT ;
 USE SIGNAL ;
 PORT
 LAYER M4 ;
 RECT 1865.760000 172.908000 1866.240000 172.932000 ;
 END
 END tx_flit[354]
 PIN tx_flit[355]
 DIRECTION INPUT ;
 USE SIGNAL ;
 PORT
 LAYER M4 ;
 RECT 1865.760000 173.052000 1866.240000 173.076000 ;
 END
 END tx_flit[355]
 PIN tx_flit[356]
 DIRECTION INPUT ;
 USE SIGNAL ;
 PORT
 LAYER M4 ;
 RECT 1865.760000 173.196000 1866.240000 173.220000 ;
 END
 END tx_flit[356]
 PIN tx_flit[357]
 DIRECTION INPUT ;
 USE SIGNAL ;
 PORT
 LAYER M4 ;
 RECT 1865.760000 173.340000 1866.240000 173.364000 ;
 END
 END tx_flit[357]
 PIN tx_flit[358]
 DIRECTION INPUT ;
 USE SIGNAL ;
 PORT
 LAYER M4 ;
 RECT 1865.760000 173.484000 1866.240000 173.508000 ;
 END
 END tx_flit[358]
 PIN tx_flit[359]
 DIRECTION INPUT ;
 USE SIGNAL ;
 PORT
 LAYER M4 ;
 RECT 1865.760000 173.628000 1866.240000 173.652000 ;
 END
 END tx_flit[359]
 PIN tx_flit[360]
 DIRECTION INPUT ;
 USE SIGNAL ;
 PORT
 LAYER M4 ;
 RECT 1865.760000 173.772000 1866.240000 173.796000 ;
 END
 END tx_flit[360]
 PIN tx_flit[361]
 DIRECTION INPUT ;
 USE SIGNAL ;
 PORT
 LAYER M4 ;
 RECT 1865.760000 173.916000 1866.240000 173.940000 ;
 END
 END tx_flit[361]
 PIN tx_flit[362]
 DIRECTION INPUT ;
 USE SIGNAL ;
 PORT
 LAYER M4 ;
 RECT 1865.760000 174.060000 1866.240000 174.084000 ;
 END
 END tx_flit[362]
 PIN tx_flit[363]
 DIRECTION INPUT ;
 USE SIGNAL ;
 PORT
 LAYER M4 ;
 RECT 1865.760000 174.204000 1866.240000 174.228000 ;
 END
 END tx_flit[363]
 PIN tx_flit[364]
 DIRECTION INPUT ;
 USE SIGNAL ;
 PORT
 LAYER M4 ;
 RECT 1865.760000 174.348000 1866.240000 174.372000 ;
 END
 END tx_flit[364]
 PIN tx_flit[365]
 DIRECTION INPUT ;
 USE SIGNAL ;
 PORT
 LAYER M4 ;
 RECT 1865.760000 174.492000 1866.240000 174.516000 ;
 END
 END tx_flit[365]
 PIN tx_flit[366]
 DIRECTION INPUT ;
 USE SIGNAL ;
 PORT
 LAYER M4 ;
 RECT 1865.760000 174.636000 1866.240000 174.660000 ;
 END
 END tx_flit[366]
 PIN tx_flit[367]
 DIRECTION INPUT ;
 USE SIGNAL ;
 PORT
 LAYER M4 ;
 RECT 1865.760000 174.780000 1866.240000 174.804000 ;
 END
 END tx_flit[367]
 PIN tx_flit[368]
 DIRECTION INPUT ;
 USE SIGNAL ;
 PORT
 LAYER M4 ;
 RECT 1865.760000 174.924000 1866.240000 174.948000 ;
 END
 END tx_flit[368]
 PIN tx_flit[369]
 DIRECTION INPUT ;
 USE SIGNAL ;
 PORT
 LAYER M4 ;
 RECT 1865.760000 175.068000 1866.240000 175.092000 ;
 END
 END tx_flit[369]
 PIN tx_flit[370]
 DIRECTION INPUT ;
 USE SIGNAL ;
 PORT
 LAYER M4 ;
 RECT 1865.760000 175.212000 1866.240000 175.236000 ;
 END
 END tx_flit[370]
 PIN tx_flit[371]
 DIRECTION INPUT ;
 USE SIGNAL ;
 PORT
 LAYER M4 ;
 RECT 1865.760000 175.356000 1866.240000 175.380000 ;
 END
 END tx_flit[371]
 PIN tx_flit[372]
 DIRECTION INPUT ;
 USE SIGNAL ;
 PORT
 LAYER M4 ;
 RECT 1865.760000 175.500000 1866.240000 175.524000 ;
 END
 END tx_flit[372]
 PIN tx_flit[373]
 DIRECTION INPUT ;
 USE SIGNAL ;
 PORT
 LAYER M4 ;
 RECT 1865.760000 175.644000 1866.240000 175.668000 ;
 END
 END tx_flit[373]
 PIN tx_flit[374]
 DIRECTION INPUT ;
 USE SIGNAL ;
 PORT
 LAYER M4 ;
 RECT 1865.760000 175.788000 1866.240000 175.812000 ;
 END
 END tx_flit[374]
 PIN tx_flit[375]
 DIRECTION INPUT ;
 USE SIGNAL ;
 PORT
 LAYER M4 ;
 RECT 1865.760000 175.932000 1866.240000 175.956000 ;
 END
 END tx_flit[375]
 PIN tx_flit[376]
 DIRECTION INPUT ;
 USE SIGNAL ;
 PORT
 LAYER M4 ;
 RECT 1865.760000 176.076000 1866.240000 176.100000 ;
 END
 END tx_flit[376]
 PIN tx_flit[377]
 DIRECTION INPUT ;
 USE SIGNAL ;
 PORT
 LAYER M4 ;
 RECT 1865.760000 176.220000 1866.240000 176.244000 ;
 END
 END tx_flit[377]
 PIN tx_flit[378]
 DIRECTION INPUT ;
 USE SIGNAL ;
 PORT
 LAYER M4 ;
 RECT 1865.760000 176.364000 1866.240000 176.388000 ;
 END
 END tx_flit[378]
 PIN tx_flit[379]
 DIRECTION INPUT ;
 USE SIGNAL ;
 PORT
 LAYER M4 ;
 RECT 1865.760000 176.508000 1866.240000 176.532000 ;
 END
 END tx_flit[379]
 PIN tx_flit[380]
 DIRECTION INPUT ;
 USE SIGNAL ;
 PORT
 LAYER M4 ;
 RECT 1865.760000 176.652000 1866.240000 176.676000 ;
 END
 END tx_flit[380]
 PIN tx_flit[381]
 DIRECTION INPUT ;
 USE SIGNAL ;
 PORT
 LAYER M4 ;
 RECT 1865.760000 176.796000 1866.240000 176.820000 ;
 END
 END tx_flit[381]
 PIN tx_flit[382]
 DIRECTION INPUT ;
 USE SIGNAL ;
 PORT
 LAYER M4 ;
 RECT 1865.760000 176.940000 1866.240000 176.964000 ;
 END
 END tx_flit[382]
 PIN tx_flit[383]
 DIRECTION INPUT ;
 USE SIGNAL ;
 PORT
 LAYER M4 ;
 RECT 1865.760000 177.084000 1866.240000 177.108000 ;
 END
 END tx_flit[383]
 PIN tx_flit[384]
 DIRECTION INPUT ;
 USE SIGNAL ;
 PORT
 LAYER M4 ;
 RECT 1865.760000 177.228000 1866.240000 177.252000 ;
 END
 END tx_flit[384]
 PIN tx_flit[385]
 DIRECTION INPUT ;
 USE SIGNAL ;
 PORT
 LAYER M4 ;
 RECT 1865.760000 177.372000 1866.240000 177.396000 ;
 END
 END tx_flit[385]
 PIN tx_flit[386]
 DIRECTION INPUT ;
 USE SIGNAL ;
 PORT
 LAYER M4 ;
 RECT 1865.760000 177.516000 1866.240000 177.540000 ;
 END
 END tx_flit[386]
 PIN tx_flit[387]
 DIRECTION INPUT ;
 USE SIGNAL ;
 PORT
 LAYER M4 ;
 RECT 1865.760000 177.660000 1866.240000 177.684000 ;
 END
 END tx_flit[387]
 PIN tx_flit[388]
 DIRECTION INPUT ;
 USE SIGNAL ;
 PORT
 LAYER M4 ;
 RECT 1865.760000 177.804000 1866.240000 177.828000 ;
 END
 END tx_flit[388]
 PIN tx_flit[389]
 DIRECTION INPUT ;
 USE SIGNAL ;
 PORT
 LAYER M4 ;
 RECT 1865.760000 177.948000 1866.240000 177.972000 ;
 END
 END tx_flit[389]
 PIN tx_flit[390]
 DIRECTION INPUT ;
 USE SIGNAL ;
 PORT
 LAYER M4 ;
 RECT 1865.760000 178.092000 1866.240000 178.116000 ;
 END
 END tx_flit[390]
 PIN tx_flit[391]
 DIRECTION INPUT ;
 USE SIGNAL ;
 PORT
 LAYER M4 ;
 RECT 1865.760000 178.236000 1866.240000 178.260000 ;
 END
 END tx_flit[391]
 PIN tx_flit[392]
 DIRECTION INPUT ;
 USE SIGNAL ;
 PORT
 LAYER M4 ;
 RECT 1865.760000 178.380000 1866.240000 178.404000 ;
 END
 END tx_flit[392]
 PIN tx_flit[393]
 DIRECTION INPUT ;
 USE SIGNAL ;
 PORT
 LAYER M4 ;
 RECT 1865.760000 178.524000 1866.240000 178.548000 ;
 END
 END tx_flit[393]
 PIN tx_flit[394]
 DIRECTION INPUT ;
 USE SIGNAL ;
 PORT
 LAYER M4 ;
 RECT 1865.760000 178.668000 1866.240000 178.692000 ;
 END
 END tx_flit[394]
 PIN tx_flit[395]
 DIRECTION INPUT ;
 USE SIGNAL ;
 PORT
 LAYER M4 ;
 RECT 1865.760000 178.812000 1866.240000 178.836000 ;
 END
 END tx_flit[395]
 PIN tx_flit[396]
 DIRECTION INPUT ;
 USE SIGNAL ;
 PORT
 LAYER M4 ;
 RECT 1865.760000 178.956000 1866.240000 178.980000 ;
 END
 END tx_flit[396]
 PIN tx_flit[397]
 DIRECTION INPUT ;
 USE SIGNAL ;
 PORT
 LAYER M4 ;
 RECT 1865.760000 179.100000 1866.240000 179.124000 ;
 END
 END tx_flit[397]
 PIN tx_flit[398]
 DIRECTION INPUT ;
 USE SIGNAL ;
 PORT
 LAYER M4 ;
 RECT 1865.760000 179.244000 1866.240000 179.268000 ;
 END
 END tx_flit[398]
 PIN tx_flit[399]
 DIRECTION INPUT ;
 USE SIGNAL ;
 PORT
 LAYER M4 ;
 RECT 1865.760000 179.388000 1866.240000 179.412000 ;
 END
 END tx_flit[399]
 PIN tx_flit[400]
 DIRECTION INPUT ;
 USE SIGNAL ;
 PORT
 LAYER M4 ;
 RECT 1865.760000 179.532000 1866.240000 179.556000 ;
 END
 END tx_flit[400]
 PIN tx_flit[401]
 DIRECTION INPUT ;
 USE SIGNAL ;
 PORT
 LAYER M4 ;
 RECT 1865.760000 179.676000 1866.240000 179.700000 ;
 END
 END tx_flit[401]
 PIN tx_flit[402]
 DIRECTION INPUT ;
 USE SIGNAL ;
 PORT
 LAYER M4 ;
 RECT 1865.760000 179.820000 1866.240000 179.844000 ;
 END
 END tx_flit[402]
 PIN tx_flit[403]
 DIRECTION INPUT ;
 USE SIGNAL ;
 PORT
 LAYER M4 ;
 RECT 1865.760000 179.964000 1866.240000 179.988000 ;
 END
 END tx_flit[403]
 PIN tx_flit[404]
 DIRECTION INPUT ;
 USE SIGNAL ;
 PORT
 LAYER M4 ;
 RECT 1865.760000 180.108000 1866.240000 180.132000 ;
 END
 END tx_flit[404]
 PIN tx_flit[405]
 DIRECTION INPUT ;
 USE SIGNAL ;
 PORT
 LAYER M4 ;
 RECT 1865.760000 180.252000 1866.240000 180.276000 ;
 END
 END tx_flit[405]
 PIN tx_flit[406]
 DIRECTION INPUT ;
 USE SIGNAL ;
 PORT
 LAYER M4 ;
 RECT 1865.760000 180.396000 1866.240000 180.420000 ;
 END
 END tx_flit[406]
 PIN tx_flit[407]
 DIRECTION INPUT ;
 USE SIGNAL ;
 PORT
 LAYER M4 ;
 RECT 1865.760000 180.540000 1866.240000 180.564000 ;
 END
 END tx_flit[407]
 PIN tx_flit[408]
 DIRECTION INPUT ;
 USE SIGNAL ;
 PORT
 LAYER M4 ;
 RECT 1865.760000 180.684000 1866.240000 180.708000 ;
 END
 END tx_flit[408]
 PIN tx_flit[409]
 DIRECTION INPUT ;
 USE SIGNAL ;
 PORT
 LAYER M4 ;
 RECT 1865.760000 180.828000 1866.240000 180.852000 ;
 END
 END tx_flit[409]
 PIN tx_flit[410]
 DIRECTION INPUT ;
 USE SIGNAL ;
 PORT
 LAYER M4 ;
 RECT 1865.760000 180.972000 1866.240000 180.996000 ;
 END
 END tx_flit[410]
 PIN tx_flit[411]
 DIRECTION INPUT ;
 USE SIGNAL ;
 PORT
 LAYER M4 ;
 RECT 1865.760000 181.116000 1866.240000 181.140000 ;
 END
 END tx_flit[411]
 PIN tx_flit[412]
 DIRECTION INPUT ;
 USE SIGNAL ;
 PORT
 LAYER M4 ;
 RECT 1865.760000 181.260000 1866.240000 181.284000 ;
 END
 END tx_flit[412]
 PIN tx_flit[413]
 DIRECTION INPUT ;
 USE SIGNAL ;
 PORT
 LAYER M4 ;
 RECT 1865.760000 181.404000 1866.240000 181.428000 ;
 END
 END tx_flit[413]
 PIN tx_flit[414]
 DIRECTION INPUT ;
 USE SIGNAL ;
 PORT
 LAYER M4 ;
 RECT 1865.760000 181.548000 1866.240000 181.572000 ;
 END
 END tx_flit[414]
 PIN tx_flit[415]
 DIRECTION INPUT ;
 USE SIGNAL ;
 PORT
 LAYER M4 ;
 RECT 1865.760000 181.692000 1866.240000 181.716000 ;
 END
 END tx_flit[415]
 PIN tx_flit[416]
 DIRECTION INPUT ;
 USE SIGNAL ;
 PORT
 LAYER M4 ;
 RECT 1865.760000 181.836000 1866.240000 181.860000 ;
 END
 END tx_flit[416]
 PIN tx_flit[417]
 DIRECTION INPUT ;
 USE SIGNAL ;
 PORT
 LAYER M4 ;
 RECT 1865.760000 181.980000 1866.240000 182.004000 ;
 END
 END tx_flit[417]
 PIN tx_flit[418]
 DIRECTION INPUT ;
 USE SIGNAL ;
 PORT
 LAYER M4 ;
 RECT 1865.760000 182.124000 1866.240000 182.148000 ;
 END
 END tx_flit[418]
 PIN tx_flit[419]
 DIRECTION INPUT ;
 USE SIGNAL ;
 PORT
 LAYER M4 ;
 RECT 1865.760000 182.268000 1866.240000 182.292000 ;
 END
 END tx_flit[419]
 PIN tx_flit[420]
 DIRECTION INPUT ;
 USE SIGNAL ;
 PORT
 LAYER M4 ;
 RECT 1865.760000 182.412000 1866.240000 182.436000 ;
 END
 END tx_flit[420]
 PIN tx_flit[421]
 DIRECTION INPUT ;
 USE SIGNAL ;
 PORT
 LAYER M4 ;
 RECT 1865.760000 182.556000 1866.240000 182.580000 ;
 END
 END tx_flit[421]
 PIN tx_flit[422]
 DIRECTION INPUT ;
 USE SIGNAL ;
 PORT
 LAYER M4 ;
 RECT 1865.760000 182.700000 1866.240000 182.724000 ;
 END
 END tx_flit[422]
 PIN tx_flit[423]
 DIRECTION INPUT ;
 USE SIGNAL ;
 PORT
 LAYER M4 ;
 RECT 1865.760000 182.844000 1866.240000 182.868000 ;
 END
 END tx_flit[423]
 PIN tx_flit[424]
 DIRECTION INPUT ;
 USE SIGNAL ;
 PORT
 LAYER M4 ;
 RECT 1865.760000 182.988000 1866.240000 183.012000 ;
 END
 END tx_flit[424]
 PIN tx_flit[425]
 DIRECTION INPUT ;
 USE SIGNAL ;
 PORT
 LAYER M4 ;
 RECT 1865.760000 183.132000 1866.240000 183.156000 ;
 END
 END tx_flit[425]
 PIN tx_flit[426]
 DIRECTION INPUT ;
 USE SIGNAL ;
 PORT
 LAYER M4 ;
 RECT 1865.760000 183.276000 1866.240000 183.300000 ;
 END
 END tx_flit[426]
 PIN tx_flit[427]
 DIRECTION INPUT ;
 USE SIGNAL ;
 PORT
 LAYER M4 ;
 RECT 1865.760000 183.420000 1866.240000 183.444000 ;
 END
 END tx_flit[427]
 PIN tx_flit[428]
 DIRECTION INPUT ;
 USE SIGNAL ;
 PORT
 LAYER M4 ;
 RECT 1865.760000 183.564000 1866.240000 183.588000 ;
 END
 END tx_flit[428]
 PIN tx_flit[429]
 DIRECTION INPUT ;
 USE SIGNAL ;
 PORT
 LAYER M4 ;
 RECT 1865.760000 183.708000 1866.240000 183.732000 ;
 END
 END tx_flit[429]
 PIN tx_flit[430]
 DIRECTION INPUT ;
 USE SIGNAL ;
 PORT
 LAYER M4 ;
 RECT 1865.760000 183.852000 1866.240000 183.876000 ;
 END
 END tx_flit[430]
 PIN tx_flit[431]
 DIRECTION INPUT ;
 USE SIGNAL ;
 PORT
 LAYER M4 ;
 RECT 1865.760000 183.996000 1866.240000 184.020000 ;
 END
 END tx_flit[431]
 PIN tx_flit[432]
 DIRECTION INPUT ;
 USE SIGNAL ;
 PORT
 LAYER M4 ;
 RECT 1865.760000 184.140000 1866.240000 184.164000 ;
 END
 END tx_flit[432]
 PIN tx_flit[433]
 DIRECTION INPUT ;
 USE SIGNAL ;
 PORT
 LAYER M4 ;
 RECT 1865.760000 184.284000 1866.240000 184.308000 ;
 END
 END tx_flit[433]
 PIN tx_flit[434]
 DIRECTION INPUT ;
 USE SIGNAL ;
 PORT
 LAYER M4 ;
 RECT 1865.760000 184.428000 1866.240000 184.452000 ;
 END
 END tx_flit[434]
 PIN tx_flit[435]
 DIRECTION INPUT ;
 USE SIGNAL ;
 PORT
 LAYER M4 ;
 RECT 1865.760000 184.572000 1866.240000 184.596000 ;
 END
 END tx_flit[435]
 PIN tx_flit[436]
 DIRECTION INPUT ;
 USE SIGNAL ;
 PORT
 LAYER M4 ;
 RECT 1865.760000 184.716000 1866.240000 184.740000 ;
 END
 END tx_flit[436]
 PIN tx_flit[437]
 DIRECTION INPUT ;
 USE SIGNAL ;
 PORT
 LAYER M4 ;
 RECT 1865.760000 184.860000 1866.240000 184.884000 ;
 END
 END tx_flit[437]
 PIN tx_flit[438]
 DIRECTION INPUT ;
 USE SIGNAL ;
 PORT
 LAYER M4 ;
 RECT 1865.760000 185.004000 1866.240000 185.028000 ;
 END
 END tx_flit[438]
 PIN tx_flit[439]
 DIRECTION INPUT ;
 USE SIGNAL ;
 PORT
 LAYER M4 ;
 RECT 1865.760000 185.148000 1866.240000 185.172000 ;
 END
 END tx_flit[439]
 PIN tx_flit[440]
 DIRECTION INPUT ;
 USE SIGNAL ;
 PORT
 LAYER M4 ;
 RECT 1865.760000 185.292000 1866.240000 185.316000 ;
 END
 END tx_flit[440]
 PIN tx_flit[441]
 DIRECTION INPUT ;
 USE SIGNAL ;
 PORT
 LAYER M4 ;
 RECT 1865.760000 185.436000 1866.240000 185.460000 ;
 END
 END tx_flit[441]
 PIN tx_flit[442]
 DIRECTION INPUT ;
 USE SIGNAL ;
 PORT
 LAYER M4 ;
 RECT 1865.760000 185.580000 1866.240000 185.604000 ;
 END
 END tx_flit[442]
 PIN tx_flit[443]
 DIRECTION INPUT ;
 USE SIGNAL ;
 PORT
 LAYER M4 ;
 RECT 1865.760000 185.724000 1866.240000 185.748000 ;
 END
 END tx_flit[443]
 PIN tx_flit[444]
 DIRECTION INPUT ;
 USE SIGNAL ;
 PORT
 LAYER M4 ;
 RECT 1865.760000 185.868000 1866.240000 185.892000 ;
 END
 END tx_flit[444]
 PIN tx_flit[445]
 DIRECTION INPUT ;
 USE SIGNAL ;
 PORT
 LAYER M4 ;
 RECT 1865.760000 186.012000 1866.240000 186.036000 ;
 END
 END tx_flit[445]
 PIN tx_flit[446]
 DIRECTION INPUT ;
 USE SIGNAL ;
 PORT
 LAYER M4 ;
 RECT 1865.760000 186.156000 1866.240000 186.180000 ;
 END
 END tx_flit[446]
 PIN tx_flit[447]
 DIRECTION INPUT ;
 USE SIGNAL ;
 PORT
 LAYER M4 ;
 RECT 1865.760000 186.300000 1866.240000 186.324000 ;
 END
 END tx_flit[447]
 PIN tx_flit[448]
 DIRECTION INPUT ;
 USE SIGNAL ;
 PORT
 LAYER M4 ;
 RECT 1865.760000 186.444000 1866.240000 186.468000 ;
 END
 END tx_flit[448]
 PIN tx_flit[449]
 DIRECTION INPUT ;
 USE SIGNAL ;
 PORT
 LAYER M4 ;
 RECT 1865.760000 186.588000 1866.240000 186.612000 ;
 END
 END tx_flit[449]
 PIN tx_flit[450]
 DIRECTION INPUT ;
 USE SIGNAL ;
 PORT
 LAYER M4 ;
 RECT 1865.760000 186.732000 1866.240000 186.756000 ;
 END
 END tx_flit[450]
 PIN tx_flit[451]
 DIRECTION INPUT ;
 USE SIGNAL ;
 PORT
 LAYER M4 ;
 RECT 1865.760000 186.876000 1866.240000 186.900000 ;
 END
 END tx_flit[451]
 PIN tx_flit[452]
 DIRECTION INPUT ;
 USE SIGNAL ;
 PORT
 LAYER M4 ;
 RECT 1865.760000 187.020000 1866.240000 187.044000 ;
 END
 END tx_flit[452]
 PIN tx_flit[453]
 DIRECTION INPUT ;
 USE SIGNAL ;
 PORT
 LAYER M4 ;
 RECT 1865.760000 187.164000 1866.240000 187.188000 ;
 END
 END tx_flit[453]
 PIN tx_flit[454]
 DIRECTION INPUT ;
 USE SIGNAL ;
 PORT
 LAYER M4 ;
 RECT 1865.760000 187.308000 1866.240000 187.332000 ;
 END
 END tx_flit[454]
 PIN tx_flit[455]
 DIRECTION INPUT ;
 USE SIGNAL ;
 PORT
 LAYER M4 ;
 RECT 1865.760000 187.452000 1866.240000 187.476000 ;
 END
 END tx_flit[455]
 PIN tx_flit[456]
 DIRECTION INPUT ;
 USE SIGNAL ;
 PORT
 LAYER M4 ;
 RECT 1865.760000 187.596000 1866.240000 187.620000 ;
 END
 END tx_flit[456]
 PIN tx_flit[457]
 DIRECTION INPUT ;
 USE SIGNAL ;
 PORT
 LAYER M4 ;
 RECT 1865.760000 187.740000 1866.240000 187.764000 ;
 END
 END tx_flit[457]
 PIN tx_flit[458]
 DIRECTION INPUT ;
 USE SIGNAL ;
 PORT
 LAYER M4 ;
 RECT 1865.760000 187.884000 1866.240000 187.908000 ;
 END
 END tx_flit[458]
 PIN tx_flit[459]
 DIRECTION INPUT ;
 USE SIGNAL ;
 PORT
 LAYER M4 ;
 RECT 1865.760000 188.028000 1866.240000 188.052000 ;
 END
 END tx_flit[459]
 PIN tx_flit[460]
 DIRECTION INPUT ;
 USE SIGNAL ;
 PORT
 LAYER M4 ;
 RECT 1865.760000 188.172000 1866.240000 188.196000 ;
 END
 END tx_flit[460]
 PIN tx_flit[461]
 DIRECTION INPUT ;
 USE SIGNAL ;
 PORT
 LAYER M4 ;
 RECT 1865.760000 188.316000 1866.240000 188.340000 ;
 END
 END tx_flit[461]
 PIN tx_flit[462]
 DIRECTION INPUT ;
 USE SIGNAL ;
 PORT
 LAYER M4 ;
 RECT 1865.760000 188.460000 1866.240000 188.484000 ;
 END
 END tx_flit[462]
 PIN tx_flit[463]
 DIRECTION INPUT ;
 USE SIGNAL ;
 PORT
 LAYER M4 ;
 RECT 1865.760000 188.604000 1866.240000 188.628000 ;
 END
 END tx_flit[463]
 PIN tx_flit[464]
 DIRECTION INPUT ;
 USE SIGNAL ;
 PORT
 LAYER M4 ;
 RECT 1865.760000 188.748000 1866.240000 188.772000 ;
 END
 END tx_flit[464]
 PIN tx_flit[465]
 DIRECTION INPUT ;
 USE SIGNAL ;
 PORT
 LAYER M4 ;
 RECT 1865.760000 188.892000 1866.240000 188.916000 ;
 END
 END tx_flit[465]
 PIN tx_flit[466]
 DIRECTION INPUT ;
 USE SIGNAL ;
 PORT
 LAYER M4 ;
 RECT 1865.760000 189.036000 1866.240000 189.060000 ;
 END
 END tx_flit[466]
 PIN tx_flit[467]
 DIRECTION INPUT ;
 USE SIGNAL ;
 PORT
 LAYER M4 ;
 RECT 1865.760000 189.180000 1866.240000 189.204000 ;
 END
 END tx_flit[467]
 PIN tx_flit[468]
 DIRECTION INPUT ;
 USE SIGNAL ;
 PORT
 LAYER M4 ;
 RECT 1865.760000 189.324000 1866.240000 189.348000 ;
 END
 END tx_flit[468]
 PIN tx_flit[469]
 DIRECTION INPUT ;
 USE SIGNAL ;
 PORT
 LAYER M4 ;
 RECT 1865.760000 189.468000 1866.240000 189.492000 ;
 END
 END tx_flit[469]
 PIN tx_flit[470]
 DIRECTION INPUT ;
 USE SIGNAL ;
 PORT
 LAYER M4 ;
 RECT 1865.760000 189.612000 1866.240000 189.636000 ;
 END
 END tx_flit[470]
 PIN tx_flit[471]
 DIRECTION INPUT ;
 USE SIGNAL ;
 PORT
 LAYER M4 ;
 RECT 1865.760000 189.756000 1866.240000 189.780000 ;
 END
 END tx_flit[471]
 PIN tx_flit[472]
 DIRECTION INPUT ;
 USE SIGNAL ;
 PORT
 LAYER M4 ;
 RECT 1865.760000 189.900000 1866.240000 189.924000 ;
 END
 END tx_flit[472]
 PIN tx_flit[473]
 DIRECTION INPUT ;
 USE SIGNAL ;
 PORT
 LAYER M4 ;
 RECT 1865.760000 190.044000 1866.240000 190.068000 ;
 END
 END tx_flit[473]
 PIN tx_flit[474]
 DIRECTION INPUT ;
 USE SIGNAL ;
 PORT
 LAYER M4 ;
 RECT 1865.760000 190.188000 1866.240000 190.212000 ;
 END
 END tx_flit[474]
 PIN tx_flit[475]
 DIRECTION INPUT ;
 USE SIGNAL ;
 PORT
 LAYER M4 ;
 RECT 1865.760000 190.332000 1866.240000 190.356000 ;
 END
 END tx_flit[475]
 PIN tx_flit[476]
 DIRECTION INPUT ;
 USE SIGNAL ;
 PORT
 LAYER M4 ;
 RECT 1865.760000 190.476000 1866.240000 190.500000 ;
 END
 END tx_flit[476]
 PIN tx_flit[477]
 DIRECTION INPUT ;
 USE SIGNAL ;
 PORT
 LAYER M4 ;
 RECT 1865.760000 190.620000 1866.240000 190.644000 ;
 END
 END tx_flit[477]
 PIN tx_flit[478]
 DIRECTION INPUT ;
 USE SIGNAL ;
 PORT
 LAYER M4 ;
 RECT 1865.760000 190.764000 1866.240000 190.788000 ;
 END
 END tx_flit[478]
 PIN tx_flit[479]
 DIRECTION INPUT ;
 USE SIGNAL ;
 PORT
 LAYER M4 ;
 RECT 1865.760000 190.908000 1866.240000 190.932000 ;
 END
 END tx_flit[479]
 PIN tx_flit[480]
 DIRECTION INPUT ;
 USE SIGNAL ;
 PORT
 LAYER M4 ;
 RECT 1865.760000 191.052000 1866.240000 191.076000 ;
 END
 END tx_flit[480]
 PIN tx_flit[481]
 DIRECTION INPUT ;
 USE SIGNAL ;
 PORT
 LAYER M4 ;
 RECT 1865.760000 191.196000 1866.240000 191.220000 ;
 END
 END tx_flit[481]
 PIN tx_flit[482]
 DIRECTION INPUT ;
 USE SIGNAL ;
 PORT
 LAYER M4 ;
 RECT 1865.760000 191.340000 1866.240000 191.364000 ;
 END
 END tx_flit[482]
 PIN tx_flit[483]
 DIRECTION INPUT ;
 USE SIGNAL ;
 PORT
 LAYER M4 ;
 RECT 1865.760000 191.484000 1866.240000 191.508000 ;
 END
 END tx_flit[483]
 PIN tx_flit[484]
 DIRECTION INPUT ;
 USE SIGNAL ;
 PORT
 LAYER M4 ;
 RECT 1865.760000 191.628000 1866.240000 191.652000 ;
 END
 END tx_flit[484]
 PIN tx_flit[485]
 DIRECTION INPUT ;
 USE SIGNAL ;
 PORT
 LAYER M4 ;
 RECT 1865.760000 191.772000 1866.240000 191.796000 ;
 END
 END tx_flit[485]
 PIN tx_flit[486]
 DIRECTION INPUT ;
 USE SIGNAL ;
 PORT
 LAYER M4 ;
 RECT 1865.760000 191.916000 1866.240000 191.940000 ;
 END
 END tx_flit[486]
 PIN tx_flit[487]
 DIRECTION INPUT ;
 USE SIGNAL ;
 PORT
 LAYER M4 ;
 RECT 1865.760000 192.060000 1866.240000 192.084000 ;
 END
 END tx_flit[487]
 PIN tx_flit[488]
 DIRECTION INPUT ;
 USE SIGNAL ;
 PORT
 LAYER M4 ;
 RECT 1865.760000 192.204000 1866.240000 192.228000 ;
 END
 END tx_flit[488]
 PIN tx_flit[489]
 DIRECTION INPUT ;
 USE SIGNAL ;
 PORT
 LAYER M4 ;
 RECT 1865.760000 192.348000 1866.240000 192.372000 ;
 END
 END tx_flit[489]
 PIN tx_flit[490]
 DIRECTION INPUT ;
 USE SIGNAL ;
 PORT
 LAYER M4 ;
 RECT 1865.760000 192.492000 1866.240000 192.516000 ;
 END
 END tx_flit[490]
 PIN tx_flit[491]
 DIRECTION INPUT ;
 USE SIGNAL ;
 PORT
 LAYER M4 ;
 RECT 1865.760000 192.636000 1866.240000 192.660000 ;
 END
 END tx_flit[491]
 PIN tx_flit[492]
 DIRECTION INPUT ;
 USE SIGNAL ;
 PORT
 LAYER M4 ;
 RECT 1865.760000 192.780000 1866.240000 192.804000 ;
 END
 END tx_flit[492]
 PIN tx_flit[493]
 DIRECTION INPUT ;
 USE SIGNAL ;
 PORT
 LAYER M4 ;
 RECT 1865.760000 192.924000 1866.240000 192.948000 ;
 END
 END tx_flit[493]
 PIN tx_flit[494]
 DIRECTION INPUT ;
 USE SIGNAL ;
 PORT
 LAYER M4 ;
 RECT 1865.760000 193.068000 1866.240000 193.092000 ;
 END
 END tx_flit[494]
 PIN tx_flit[495]
 DIRECTION INPUT ;
 USE SIGNAL ;
 PORT
 LAYER M4 ;
 RECT 1865.760000 193.212000 1866.240000 193.236000 ;
 END
 END tx_flit[495]
 PIN tx_flit[496]
 DIRECTION INPUT ;
 USE SIGNAL ;
 PORT
 LAYER M4 ;
 RECT 1865.760000 193.356000 1866.240000 193.380000 ;
 END
 END tx_flit[496]
 PIN tx_flit[497]
 DIRECTION INPUT ;
 USE SIGNAL ;
 PORT
 LAYER M4 ;
 RECT 1865.760000 193.500000 1866.240000 193.524000 ;
 END
 END tx_flit[497]
 PIN tx_flit[498]
 DIRECTION INPUT ;
 USE SIGNAL ;
 PORT
 LAYER M4 ;
 RECT 1865.760000 193.644000 1866.240000 193.668000 ;
 END
 END tx_flit[498]
 PIN tx_flit[499]
 DIRECTION INPUT ;
 USE SIGNAL ;
 PORT
 LAYER M4 ;
 RECT 1865.760000 193.788000 1866.240000 193.812000 ;
 END
 END tx_flit[499]
 PIN tx_flit[500]
 DIRECTION INPUT ;
 USE SIGNAL ;
 PORT
 LAYER M4 ;
 RECT 1865.760000 193.932000 1866.240000 193.956000 ;
 END
 END tx_flit[500]
 PIN tx_flit[501]
 DIRECTION INPUT ;
 USE SIGNAL ;
 PORT
 LAYER M4 ;
 RECT 1865.760000 194.076000 1866.240000 194.100000 ;
 END
 END tx_flit[501]
 PIN tx_flit[502]
 DIRECTION INPUT ;
 USE SIGNAL ;
 PORT
 LAYER M4 ;
 RECT 1865.760000 194.220000 1866.240000 194.244000 ;
 END
 END tx_flit[502]
 PIN tx_flit[503]
 DIRECTION INPUT ;
 USE SIGNAL ;
 PORT
 LAYER M4 ;
 RECT 1865.760000 194.364000 1866.240000 194.388000 ;
 END
 END tx_flit[503]
 PIN tx_flit[504]
 DIRECTION INPUT ;
 USE SIGNAL ;
 PORT
 LAYER M4 ;
 RECT 1865.760000 194.508000 1866.240000 194.532000 ;
 END
 END tx_flit[504]
 PIN tx_flit[505]
 DIRECTION INPUT ;
 USE SIGNAL ;
 PORT
 LAYER M4 ;
 RECT 1865.760000 194.652000 1866.240000 194.676000 ;
 END
 END tx_flit[505]
 PIN tx_flit[506]
 DIRECTION INPUT ;
 USE SIGNAL ;
 PORT
 LAYER M4 ;
 RECT 1865.760000 194.796000 1866.240000 194.820000 ;
 END
 END tx_flit[506]
 PIN tx_flit[507]
 DIRECTION INPUT ;
 USE SIGNAL ;
 PORT
 LAYER M4 ;
 RECT 1865.760000 194.940000 1866.240000 194.964000 ;
 END
 END tx_flit[507]
 PIN tx_flit[508]
 DIRECTION INPUT ;
 USE SIGNAL ;
 PORT
 LAYER M4 ;
 RECT 1865.760000 195.084000 1866.240000 195.108000 ;
 END
 END tx_flit[508]
 PIN tx_flit[509]
 DIRECTION INPUT ;
 USE SIGNAL ;
 PORT
 LAYER M4 ;
 RECT 1865.760000 195.228000 1866.240000 195.252000 ;
 END
 END tx_flit[509]
 PIN tx_flit[510]
 DIRECTION INPUT ;
 USE SIGNAL ;
 PORT
 LAYER M4 ;
 RECT 1865.760000 195.372000 1866.240000 195.396000 ;
 END
 END tx_flit[510]
 PIN tx_flit[511]
 DIRECTION INPUT ;
 USE SIGNAL ;
 PORT
 LAYER M4 ;
 RECT 1865.760000 195.516000 1866.240000 195.540000 ;
 END
 END tx_flit[511]
 PIN tx_flit[512]
 DIRECTION INPUT ;
 USE SIGNAL ;
 PORT
 LAYER M4 ;
 RECT 1865.760000 195.660000 1866.240000 195.684000 ;
 END
 END tx_flit[512]
 PIN tx_flit[513]
 DIRECTION INPUT ;
 USE SIGNAL ;
 PORT
 LAYER M4 ;
 RECT 1865.760000 195.804000 1866.240000 195.828000 ;
 END
 END tx_flit[513]
 PIN tx_flit[514]
 DIRECTION INPUT ;
 USE SIGNAL ;
 PORT
 LAYER M4 ;
 RECT 1865.760000 195.948000 1866.240000 195.972000 ;
 END
 END tx_flit[514]
 PIN tx_flit[515]
 DIRECTION INPUT ;
 USE SIGNAL ;
 PORT
 LAYER M4 ;
 RECT 1865.760000 196.092000 1866.240000 196.116000 ;
 END
 END tx_flit[515]
 PIN tx_flit[516]
 DIRECTION INPUT ;
 USE SIGNAL ;
 PORT
 LAYER M4 ;
 RECT 1865.760000 196.236000 1866.240000 196.260000 ;
 END
 END tx_flit[516]
 PIN tx_flit[517]
 DIRECTION INPUT ;
 USE SIGNAL ;
 PORT
 LAYER M4 ;
 RECT 1865.760000 196.380000 1866.240000 196.404000 ;
 END
 END tx_flit[517]
 PIN tx_flit[518]
 DIRECTION INPUT ;
 USE SIGNAL ;
 PORT
 LAYER M4 ;
 RECT 1865.760000 196.524000 1866.240000 196.548000 ;
 END
 END tx_flit[518]
 PIN tx_flit[519]
 DIRECTION INPUT ;
 USE SIGNAL ;
 PORT
 LAYER M4 ;
 RECT 1865.760000 196.668000 1866.240000 196.692000 ;
 END
 END tx_flit[519]
 PIN tx_flit[520]
 DIRECTION INPUT ;
 USE SIGNAL ;
 PORT
 LAYER M4 ;
 RECT 1865.760000 196.812000 1866.240000 196.836000 ;
 END
 END tx_flit[520]
 PIN tx_flit[521]
 DIRECTION INPUT ;
 USE SIGNAL ;
 PORT
 LAYER M4 ;
 RECT 1865.760000 196.956000 1866.240000 196.980000 ;
 END
 END tx_flit[521]
 PIN rx_v
 DIRECTION OUTPUT ;
 USE SIGNAL ;
 PORT
 LAYER M4 ;
 RECT 1865.760000 630.012000 1866.240000 630.036000 ;
 END
 END rx_v
 PIN rx_flit[0]
 DIRECTION OUTPUT ;
 USE SIGNAL ;
 PORT
 LAYER M4 ;
 RECT 1865.760000 549.180000 1866.240000 549.204000 ;
 END
 END rx_flit[0]
 PIN rx_flit[1]
 DIRECTION OUTPUT ;
 USE SIGNAL ;
 PORT
 LAYER M4 ;
 RECT 1865.760000 549.324000 1866.240000 549.348000 ;
 END
 END rx_flit[1]
 PIN rx_flit[2]
 DIRECTION OUTPUT ;
 USE SIGNAL ;
 PORT
 LAYER M4 ;
 RECT 1865.760000 549.468000 1866.240000 549.492000 ;
 END
 END rx_flit[2]
 PIN rx_flit[3]
 DIRECTION OUTPUT ;
 USE SIGNAL ;
 PORT
 LAYER M4 ;
 RECT 1865.760000 549.612000 1866.240000 549.636000 ;
 END
 END rx_flit[3]
 PIN rx_flit[4]
 DIRECTION OUTPUT ;
 USE SIGNAL ;
 PORT
 LAYER M4 ;
 RECT 1865.760000 549.756000 1866.240000 549.780000 ;
 END
 END rx_flit[4]
 PIN rx_flit[5]
 DIRECTION OUTPUT ;
 USE SIGNAL ;
 PORT
 LAYER M4 ;
 RECT 1865.760000 549.900000 1866.240000 549.924000 ;
 END
 END rx_flit[5]
 PIN rx_flit[6]
 DIRECTION OUTPUT ;
 USE SIGNAL ;
 PORT
 LAYER M4 ;
 RECT 1865.760000 550.044000 1866.240000 550.068000 ;
 END
 END rx_flit[6]
 PIN rx_flit[7]
 DIRECTION OUTPUT ;
 USE SIGNAL ;
 PORT
 LAYER M4 ;
 RECT 1865.760000 550.188000 1866.240000 550.212000 ;
 END
 END rx_flit[7]
 PIN rx_flit[8]
 DIRECTION OUTPUT ;
 USE SIGNAL ;
 PORT
 LAYER M4 ;
 RECT 1865.760000 550.332000 1866.240000 550.356000 ;
 END
 END rx_flit[8]
 PIN rx_flit[9]
 DIRECTION OUTPUT ;
 USE SIGNAL ;
 PORT
 LAYER M4 ;
 RECT 1865.760000 550.476000 1866.240000 550.500000 ;
 END
 END rx_flit[9]
 PIN rx_flit[10]
 DIRECTION OUTPUT ;
 USE SIGNAL ;
 PORT
 LAYER M4 ;
 RECT 1865.760000 550.620000 1866.240000 550.644000 ;
 END
 END rx_flit[10]
 PIN rx_flit[11]
 DIRECTION OUTPUT ;
 USE SIGNAL ;
 PORT
 LAYER M4 ;
 RECT 1865.760000 550.764000 1866.240000 550.788000 ;
 END
 END rx_flit[11]
 PIN rx_flit[12]
 DIRECTION OUTPUT ;
 USE SIGNAL ;
 PORT
 LAYER M4 ;
 RECT 1865.760000 550.908000 1866.240000 550.932000 ;
 END
 END rx_flit[12]
 PIN rx_flit[13]
 DIRECTION OUTPUT ;
 USE SIGNAL ;
 PORT
 LAYER M4 ;
 RECT 1865.760000 551.052000 1866.240000 551.076000 ;
 END
 END rx_flit[13]
 PIN rx_flit[14]
 DIRECTION OUTPUT ;
 USE SIGNAL ;
 PORT
 LAYER M4 ;
 RECT 1865.760000 551.196000 1866.240000 551.220000 ;
 END
 END rx_flit[14]
 PIN rx_flit[15]
 DIRECTION OUTPUT ;
 USE SIGNAL ;
 PORT
 LAYER M4 ;
 RECT 1865.760000 551.340000 1866.240000 551.364000 ;
 END
 END rx_flit[15]
 PIN rx_flit[16]
 DIRECTION OUTPUT ;
 USE SIGNAL ;
 PORT
 LAYER M4 ;
 RECT 1865.760000 551.484000 1866.240000 551.508000 ;
 END
 END rx_flit[16]
 PIN rx_flit[17]
 DIRECTION OUTPUT ;
 USE SIGNAL ;
 PORT
 LAYER M4 ;
 RECT 1865.760000 551.628000 1866.240000 551.652000 ;
 END
 END rx_flit[17]
 PIN rx_flit[18]
 DIRECTION OUTPUT ;
 USE SIGNAL ;
 PORT
 LAYER M4 ;
 RECT 1865.760000 551.772000 1866.240000 551.796000 ;
 END
 END rx_flit[18]
 PIN rx_flit[19]
 DIRECTION OUTPUT ;
 USE SIGNAL ;
 PORT
 LAYER M4 ;
 RECT 1865.760000 551.916000 1866.240000 551.940000 ;
 END
 END rx_flit[19]
 PIN rx_flit[20]
 DIRECTION OUTPUT ;
 USE SIGNAL ;
 PORT
 LAYER M4 ;
 RECT 1865.760000 552.060000 1866.240000 552.084000 ;
 END
 END rx_flit[20]
 PIN rx_flit[21]
 DIRECTION OUTPUT ;
 USE SIGNAL ;
 PORT
 LAYER M4 ;
 RECT 1865.760000 552.204000 1866.240000 552.228000 ;
 END
 END rx_flit[21]
 PIN rx_flit[22]
 DIRECTION OUTPUT ;
 USE SIGNAL ;
 PORT
 LAYER M4 ;
 RECT 1865.760000 552.348000 1866.240000 552.372000 ;
 END
 END rx_flit[22]
 PIN rx_flit[23]
 DIRECTION OUTPUT ;
 USE SIGNAL ;
 PORT
 LAYER M4 ;
 RECT 1865.760000 552.492000 1866.240000 552.516000 ;
 END
 END rx_flit[23]
 PIN rx_flit[24]
 DIRECTION OUTPUT ;
 USE SIGNAL ;
 PORT
 LAYER M4 ;
 RECT 1865.760000 552.636000 1866.240000 552.660000 ;
 END
 END rx_flit[24]
 PIN rx_flit[25]
 DIRECTION OUTPUT ;
 USE SIGNAL ;
 PORT
 LAYER M4 ;
 RECT 1865.760000 552.780000 1866.240000 552.804000 ;
 END
 END rx_flit[25]
 PIN rx_flit[26]
 DIRECTION OUTPUT ;
 USE SIGNAL ;
 PORT
 LAYER M4 ;
 RECT 1865.760000 552.924000 1866.240000 552.948000 ;
 END
 END rx_flit[26]
 PIN rx_flit[27]
 DIRECTION OUTPUT ;
 USE SIGNAL ;
 PORT
 LAYER M4 ;
 RECT 1865.760000 553.068000 1866.240000 553.092000 ;
 END
 END rx_flit[27]
 PIN rx_flit[28]
 DIRECTION OUTPUT ;
 USE SIGNAL ;
 PORT
 LAYER M4 ;
 RECT 1865.760000 553.212000 1866.240000 553.236000 ;
 END
 END rx_flit[28]
 PIN rx_flit[29]
 DIRECTION OUTPUT ;
 USE SIGNAL ;
 PORT
 LAYER M4 ;
 RECT 1865.760000 553.356000 1866.240000 553.380000 ;
 END
 END rx_flit[29]
 PIN rx_flit[30]
 DIRECTION OUTPUT ;
 USE SIGNAL ;
 PORT
 LAYER M4 ;
 RECT 1865.760000 553.500000 1866.240000 553.524000 ;
 END
 END rx_flit[30]
 PIN rx_flit[31]
 DIRECTION OUTPUT ;
 USE SIGNAL ;
 PORT
 LAYER M4 ;
 RECT 1865.760000 553.644000 1866.240000 553.668000 ;
 END
 END rx_flit[31]
 PIN rx_flit[32]
 DIRECTION OUTPUT ;
 USE SIGNAL ;
 PORT
 LAYER M4 ;
 RECT 1865.760000 553.788000 1866.240000 553.812000 ;
 END
 END rx_flit[32]
 PIN rx_flit[33]
 DIRECTION OUTPUT ;
 USE SIGNAL ;
 PORT
 LAYER M4 ;
 RECT 1865.760000 553.932000 1866.240000 553.956000 ;
 END
 END rx_flit[33]
 PIN rx_flit[34]
 DIRECTION OUTPUT ;
 USE SIGNAL ;
 PORT
 LAYER M4 ;
 RECT 1865.760000 554.076000 1866.240000 554.100000 ;
 END
 END rx_flit[34]
 PIN rx_flit[35]
 DIRECTION OUTPUT ;
 USE SIGNAL ;
 PORT
 LAYER M4 ;
 RECT 1865.760000 554.220000 1866.240000 554.244000 ;
 END
 END rx_flit[35]
 PIN rx_flit[36]
 DIRECTION OUTPUT ;
 USE SIGNAL ;
 PORT
 LAYER M4 ;
 RECT 1865.760000 554.364000 1866.240000 554.388000 ;
 END
 END rx_flit[36]
 PIN rx_flit[37]
 DIRECTION OUTPUT ;
 USE SIGNAL ;
 PORT
 LAYER M4 ;
 RECT 1865.760000 554.508000 1866.240000 554.532000 ;
 END
 END rx_flit[37]
 PIN rx_flit[38]
 DIRECTION OUTPUT ;
 USE SIGNAL ;
 PORT
 LAYER M4 ;
 RECT 1865.760000 554.652000 1866.240000 554.676000 ;
 END
 END rx_flit[38]
 PIN rx_flit[39]
 DIRECTION OUTPUT ;
 USE SIGNAL ;
 PORT
 LAYER M4 ;
 RECT 1865.760000 554.796000 1866.240000 554.820000 ;
 END
 END rx_flit[39]
 PIN rx_flit[40]
 DIRECTION OUTPUT ;
 USE SIGNAL ;
 PORT
 LAYER M4 ;
 RECT 1865.760000 554.940000 1866.240000 554.964000 ;
 END
 END rx_flit[40]
 PIN rx_flit[41]
 DIRECTION OUTPUT ;
 USE SIGNAL ;
 PORT
 LAYER M4 ;
 RECT 1865.760000 555.084000 1866.240000 555.108000 ;
 END
 END rx_flit[41]
 PIN rx_flit[42]
 DIRECTION OUTPUT ;
 USE SIGNAL ;
 PORT
 LAYER M4 ;
 RECT 1865.760000 555.228000 1866.240000 555.252000 ;
 END
 END rx_flit[42]
 PIN rx_flit[43]
 DIRECTION OUTPUT ;
 USE SIGNAL ;
 PORT
 LAYER M4 ;
 RECT 1865.760000 555.372000 1866.240000 555.396000 ;
 END
 END rx_flit[43]
 PIN rx_flit[44]
 DIRECTION OUTPUT ;
 USE SIGNAL ;
 PORT
 LAYER M4 ;
 RECT 1865.760000 555.516000 1866.240000 555.540000 ;
 END
 END rx_flit[44]
 PIN rx_flit[45]
 DIRECTION OUTPUT ;
 USE SIGNAL ;
 PORT
 LAYER M4 ;
 RECT 1865.760000 555.660000 1866.240000 555.684000 ;
 END
 END rx_flit[45]
 PIN rx_flit[46]
 DIRECTION OUTPUT ;
 USE SIGNAL ;
 PORT
 LAYER M4 ;
 RECT 1865.760000 555.804000 1866.240000 555.828000 ;
 END
 END rx_flit[46]
 PIN rx_flit[47]
 DIRECTION OUTPUT ;
 USE SIGNAL ;
 PORT
 LAYER M4 ;
 RECT 1865.760000 555.948000 1866.240000 555.972000 ;
 END
 END rx_flit[47]
 PIN rx_flit[48]
 DIRECTION OUTPUT ;
 USE SIGNAL ;
 PORT
 LAYER M4 ;
 RECT 1865.760000 556.092000 1866.240000 556.116000 ;
 END
 END rx_flit[48]
 PIN rx_flit[49]
 DIRECTION OUTPUT ;
 USE SIGNAL ;
 PORT
 LAYER M4 ;
 RECT 1865.760000 556.236000 1866.240000 556.260000 ;
 END
 END rx_flit[49]
 PIN rx_flit[50]
 DIRECTION OUTPUT ;
 USE SIGNAL ;
 PORT
 LAYER M4 ;
 RECT 1865.760000 556.380000 1866.240000 556.404000 ;
 END
 END rx_flit[50]
 PIN rx_flit[51]
 DIRECTION OUTPUT ;
 USE SIGNAL ;
 PORT
 LAYER M4 ;
 RECT 1865.760000 556.524000 1866.240000 556.548000 ;
 END
 END rx_flit[51]
 PIN rx_flit[52]
 DIRECTION OUTPUT ;
 USE SIGNAL ;
 PORT
 LAYER M4 ;
 RECT 1865.760000 556.668000 1866.240000 556.692000 ;
 END
 END rx_flit[52]
 PIN rx_flit[53]
 DIRECTION OUTPUT ;
 USE SIGNAL ;
 PORT
 LAYER M4 ;
 RECT 1865.760000 556.812000 1866.240000 556.836000 ;
 END
 END rx_flit[53]
 PIN rx_flit[54]
 DIRECTION OUTPUT ;
 USE SIGNAL ;
 PORT
 LAYER M4 ;
 RECT 1865.760000 556.956000 1866.240000 556.980000 ;
 END
 END rx_flit[54]
 PIN rx_flit[55]
 DIRECTION OUTPUT ;
 USE SIGNAL ;
 PORT
 LAYER M4 ;
 RECT 1865.760000 557.100000 1866.240000 557.124000 ;
 END
 END rx_flit[55]
 PIN rx_flit[56]
 DIRECTION OUTPUT ;
 USE SIGNAL ;
 PORT
 LAYER M4 ;
 RECT 1865.760000 557.244000 1866.240000 557.268000 ;
 END
 END rx_flit[56]
 PIN rx_flit[57]
 DIRECTION OUTPUT ;
 USE SIGNAL ;
 PORT
 LAYER M4 ;
 RECT 1865.760000 557.388000 1866.240000 557.412000 ;
 END
 END rx_flit[57]
 PIN rx_flit[58]
 DIRECTION OUTPUT ;
 USE SIGNAL ;
 PORT
 LAYER M4 ;
 RECT 1865.760000 557.532000 1866.240000 557.556000 ;
 END
 END rx_flit[58]
 PIN rx_flit[59]
 DIRECTION OUTPUT ;
 USE SIGNAL ;
 PORT
 LAYER M4 ;
 RECT 1865.760000 557.676000 1866.240000 557.700000 ;
 END
 END rx_flit[59]
 PIN rx_flit[60]
 DIRECTION OUTPUT ;
 USE SIGNAL ;
 PORT
 LAYER M4 ;
 RECT 1865.760000 557.820000 1866.240000 557.844000 ;
 END
 END rx_flit[60]
 PIN rx_flit[61]
 DIRECTION OUTPUT ;
 USE SIGNAL ;
 PORT
 LAYER M4 ;
 RECT 1865.760000 557.964000 1866.240000 557.988000 ;
 END
 END rx_flit[61]
 PIN rx_flit[62]
 DIRECTION OUTPUT ;
 USE SIGNAL ;
 PORT
 LAYER M4 ;
 RECT 1865.760000 558.108000 1866.240000 558.132000 ;
 END
 END rx_flit[62]
 PIN rx_flit[63]
 DIRECTION OUTPUT ;
 USE SIGNAL ;
 PORT
 LAYER M4 ;
 RECT 1865.760000 558.252000 1866.240000 558.276000 ;
 END
 END rx_flit[63]
 PIN rx_flit[64]
 DIRECTION OUTPUT ;
 USE SIGNAL ;
 PORT
 LAYER M4 ;
 RECT 1865.760000 558.396000 1866.240000 558.420000 ;
 END
 END rx_flit[64]
 PIN rx_flit[65]
 DIRECTION OUTPUT ;
 USE SIGNAL ;
 PORT
 LAYER M4 ;
 RECT 1865.760000 558.540000 1866.240000 558.564000 ;
 END
 END rx_flit[65]
 PIN rx_flit[66]
 DIRECTION OUTPUT ;
 USE SIGNAL ;
 PORT
 LAYER M4 ;
 RECT 1865.760000 558.684000 1866.240000 558.708000 ;
 END
 END rx_flit[66]
 PIN rx_flit[67]
 DIRECTION OUTPUT ;
 USE SIGNAL ;
 PORT
 LAYER M4 ;
 RECT 1865.760000 558.828000 1866.240000 558.852000 ;
 END
 END rx_flit[67]
 PIN rx_flit[68]
 DIRECTION OUTPUT ;
 USE SIGNAL ;
 PORT
 LAYER M4 ;
 RECT 1865.760000 558.972000 1866.240000 558.996000 ;
 END
 END rx_flit[68]
 PIN rx_flit[69]
 DIRECTION OUTPUT ;
 USE SIGNAL ;
 PORT
 LAYER M4 ;
 RECT 1865.760000 559.116000 1866.240000 559.140000 ;
 END
 END rx_flit[69]
 PIN rx_flit[70]
 DIRECTION OUTPUT ;
 USE SIGNAL ;
 PORT
 LAYER M4 ;
 RECT 1865.760000 559.260000 1866.240000 559.284000 ;
 END
 END rx_flit[70]
 PIN rx_flit[71]
 DIRECTION OUTPUT ;
 USE SIGNAL ;
 PORT
 LAYER M4 ;
 RECT 1865.760000 559.404000 1866.240000 559.428000 ;
 END
 END rx_flit[71]
 PIN rx_flit[72]
 DIRECTION OUTPUT ;
 USE SIGNAL ;
 PORT
 LAYER M4 ;
 RECT 1865.760000 559.548000 1866.240000 559.572000 ;
 END
 END rx_flit[72]
 PIN rx_flit[73]
 DIRECTION OUTPUT ;
 USE SIGNAL ;
 PORT
 LAYER M4 ;
 RECT 1865.760000 559.692000 1866.240000 559.716000 ;
 END
 END rx_flit[73]
 PIN rx_flit[74]
 DIRECTION OUTPUT ;
 USE SIGNAL ;
 PORT
 LAYER M4 ;
 RECT 1865.760000 559.836000 1866.240000 559.860000 ;
 END
 END rx_flit[74]
 PIN rx_flit[75]
 DIRECTION OUTPUT ;
 USE SIGNAL ;
 PORT
 LAYER M4 ;
 RECT 1865.760000 559.980000 1866.240000 560.004000 ;
 END
 END rx_flit[75]
 PIN rx_flit[76]
 DIRECTION OUTPUT ;
 USE SIGNAL ;
 PORT
 LAYER M4 ;
 RECT 1865.760000 560.124000 1866.240000 560.148000 ;
 END
 END rx_flit[76]
 PIN rx_flit[77]
 DIRECTION OUTPUT ;
 USE SIGNAL ;
 PORT
 LAYER M4 ;
 RECT 1865.760000 560.268000 1866.240000 560.292000 ;
 END
 END rx_flit[77]
 PIN rx_flit[78]
 DIRECTION OUTPUT ;
 USE SIGNAL ;
 PORT
 LAYER M4 ;
 RECT 1865.760000 560.412000 1866.240000 560.436000 ;
 END
 END rx_flit[78]
 PIN rx_flit[79]
 DIRECTION OUTPUT ;
 USE SIGNAL ;
 PORT
 LAYER M4 ;
 RECT 1865.760000 560.556000 1866.240000 560.580000 ;
 END
 END rx_flit[79]
 PIN rx_flit[80]
 DIRECTION OUTPUT ;
 USE SIGNAL ;
 PORT
 LAYER M4 ;
 RECT 1865.760000 560.700000 1866.240000 560.724000 ;
 END
 END rx_flit[80]
 PIN rx_flit[81]
 DIRECTION OUTPUT ;
 USE SIGNAL ;
 PORT
 LAYER M4 ;
 RECT 1865.760000 560.844000 1866.240000 560.868000 ;
 END
 END rx_flit[81]
 PIN rx_flit[82]
 DIRECTION OUTPUT ;
 USE SIGNAL ;
 PORT
 LAYER M4 ;
 RECT 1865.760000 560.988000 1866.240000 561.012000 ;
 END
 END rx_flit[82]
 PIN rx_flit[83]
 DIRECTION OUTPUT ;
 USE SIGNAL ;
 PORT
 LAYER M4 ;
 RECT 1865.760000 561.132000 1866.240000 561.156000 ;
 END
 END rx_flit[83]
 PIN rx_flit[84]
 DIRECTION OUTPUT ;
 USE SIGNAL ;
 PORT
 LAYER M4 ;
 RECT 1865.760000 561.276000 1866.240000 561.300000 ;
 END
 END rx_flit[84]
 PIN rx_flit[85]
 DIRECTION OUTPUT ;
 USE SIGNAL ;
 PORT
 LAYER M4 ;
 RECT 1865.760000 561.420000 1866.240000 561.444000 ;
 END
 END rx_flit[85]
 PIN rx_flit[86]
 DIRECTION OUTPUT ;
 USE SIGNAL ;
 PORT
 LAYER M4 ;
 RECT 1865.760000 561.564000 1866.240000 561.588000 ;
 END
 END rx_flit[86]
 PIN rx_flit[87]
 DIRECTION OUTPUT ;
 USE SIGNAL ;
 PORT
 LAYER M4 ;
 RECT 1865.760000 561.708000 1866.240000 561.732000 ;
 END
 END rx_flit[87]
 PIN rx_flit[88]
 DIRECTION OUTPUT ;
 USE SIGNAL ;
 PORT
 LAYER M4 ;
 RECT 1865.760000 561.852000 1866.240000 561.876000 ;
 END
 END rx_flit[88]
 PIN rx_flit[89]
 DIRECTION OUTPUT ;
 USE SIGNAL ;
 PORT
 LAYER M4 ;
 RECT 1865.760000 561.996000 1866.240000 562.020000 ;
 END
 END rx_flit[89]
 PIN rx_flit[90]
 DIRECTION OUTPUT ;
 USE SIGNAL ;
 PORT
 LAYER M4 ;
 RECT 1865.760000 562.140000 1866.240000 562.164000 ;
 END
 END rx_flit[90]
 PIN rx_flit[91]
 DIRECTION OUTPUT ;
 USE SIGNAL ;
 PORT
 LAYER M4 ;
 RECT 1865.760000 562.284000 1866.240000 562.308000 ;
 END
 END rx_flit[91]
 PIN rx_flit[92]
 DIRECTION OUTPUT ;
 USE SIGNAL ;
 PORT
 LAYER M4 ;
 RECT 1865.760000 562.428000 1866.240000 562.452000 ;
 END
 END rx_flit[92]
 PIN rx_flit[93]
 DIRECTION OUTPUT ;
 USE SIGNAL ;
 PORT
 LAYER M4 ;
 RECT 1865.760000 562.572000 1866.240000 562.596000 ;
 END
 END rx_flit[93]
 PIN rx_flit[94]
 DIRECTION OUTPUT ;
 USE SIGNAL ;
 PORT
 LAYER M4 ;
 RECT 1865.760000 562.716000 1866.240000 562.740000 ;
 END
 END rx_flit[94]
 PIN rx_flit[95]
 DIRECTION OUTPUT ;
 USE SIGNAL ;
 PORT
 LAYER M4 ;
 RECT 1865.760000 562.860000 1866.240000 562.884000 ;
 END
 END rx_flit[95]
 PIN rx_flit[96]
 DIRECTION OUTPUT ;
 USE SIGNAL ;
 PORT
 LAYER M4 ;
 RECT 1865.760000 563.004000 1866.240000 563.028000 ;
 END
 END rx_flit[96]
 PIN rx_flit[97]
 DIRECTION OUTPUT ;
 USE SIGNAL ;
 PORT
 LAYER M4 ;
 RECT 1865.760000 563.148000 1866.240000 563.172000 ;
 END
 END rx_flit[97]
 PIN rx_flit[98]
 DIRECTION OUTPUT ;
 USE SIGNAL ;
 PORT
 LAYER M4 ;
 RECT 1865.760000 563.292000 1866.240000 563.316000 ;
 END
 END rx_flit[98]
 PIN rx_flit[99]
 DIRECTION OUTPUT ;
 USE SIGNAL ;
 PORT
 LAYER M4 ;
 RECT 1865.760000 563.436000 1866.240000 563.460000 ;
 END
 END rx_flit[99]
 PIN rx_flit[100]
 DIRECTION OUTPUT ;
 USE SIGNAL ;
 PORT
 LAYER M4 ;
 RECT 1865.760000 563.580000 1866.240000 563.604000 ;
 END
 END rx_flit[100]
 PIN rx_flit[101]
 DIRECTION OUTPUT ;
 USE SIGNAL ;
 PORT
 LAYER M4 ;
 RECT 1865.760000 563.724000 1866.240000 563.748000 ;
 END
 END rx_flit[101]
 PIN rx_flit[102]
 DIRECTION OUTPUT ;
 USE SIGNAL ;
 PORT
 LAYER M4 ;
 RECT 1865.760000 563.868000 1866.240000 563.892000 ;
 END
 END rx_flit[102]
 PIN rx_flit[103]
 DIRECTION OUTPUT ;
 USE SIGNAL ;
 PORT
 LAYER M4 ;
 RECT 1865.760000 564.012000 1866.240000 564.036000 ;
 END
 END rx_flit[103]
 PIN rx_flit[104]
 DIRECTION OUTPUT ;
 USE SIGNAL ;
 PORT
 LAYER M4 ;
 RECT 1865.760000 564.156000 1866.240000 564.180000 ;
 END
 END rx_flit[104]
 PIN rx_flit[105]
 DIRECTION OUTPUT ;
 USE SIGNAL ;
 PORT
 LAYER M4 ;
 RECT 1865.760000 564.300000 1866.240000 564.324000 ;
 END
 END rx_flit[105]
 PIN rx_flit[106]
 DIRECTION OUTPUT ;
 USE SIGNAL ;
 PORT
 LAYER M4 ;
 RECT 1865.760000 564.444000 1866.240000 564.468000 ;
 END
 END rx_flit[106]
 PIN rx_flit[107]
 DIRECTION OUTPUT ;
 USE SIGNAL ;
 PORT
 LAYER M4 ;
 RECT 1865.760000 564.588000 1866.240000 564.612000 ;
 END
 END rx_flit[107]
 PIN rx_flit[108]
 DIRECTION OUTPUT ;
 USE SIGNAL ;
 PORT
 LAYER M4 ;
 RECT 1865.760000 564.732000 1866.240000 564.756000 ;
 END
 END rx_flit[108]
 PIN rx_flit[109]
 DIRECTION OUTPUT ;
 USE SIGNAL ;
 PORT
 LAYER M4 ;
 RECT 1865.760000 564.876000 1866.240000 564.900000 ;
 END
 END rx_flit[109]
 PIN rx_flit[110]
 DIRECTION OUTPUT ;
 USE SIGNAL ;
 PORT
 LAYER M4 ;
 RECT 1865.760000 565.020000 1866.240000 565.044000 ;
 END
 END rx_flit[110]
 PIN rx_flit[111]
 DIRECTION OUTPUT ;
 USE SIGNAL ;
 PORT
 LAYER M4 ;
 RECT 1865.760000 565.164000 1866.240000 565.188000 ;
 END
 END rx_flit[111]
 PIN rx_flit[112]
 DIRECTION OUTPUT ;
 USE SIGNAL ;
 PORT
 LAYER M4 ;
 RECT 1865.760000 565.308000 1866.240000 565.332000 ;
 END
 END rx_flit[112]
 PIN rx_flit[113]
 DIRECTION OUTPUT ;
 USE SIGNAL ;
 PORT
 LAYER M4 ;
 RECT 1865.760000 565.452000 1866.240000 565.476000 ;
 END
 END rx_flit[113]
 PIN rx_flit[114]
 DIRECTION OUTPUT ;
 USE SIGNAL ;
 PORT
 LAYER M4 ;
 RECT 1865.760000 565.596000 1866.240000 565.620000 ;
 END
 END rx_flit[114]
 PIN rx_flit[115]
 DIRECTION OUTPUT ;
 USE SIGNAL ;
 PORT
 LAYER M4 ;
 RECT 1865.760000 565.740000 1866.240000 565.764000 ;
 END
 END rx_flit[115]
 PIN rx_flit[116]
 DIRECTION OUTPUT ;
 USE SIGNAL ;
 PORT
 LAYER M4 ;
 RECT 1865.760000 565.884000 1866.240000 565.908000 ;
 END
 END rx_flit[116]
 PIN rx_flit[117]
 DIRECTION OUTPUT ;
 USE SIGNAL ;
 PORT
 LAYER M4 ;
 RECT 1865.760000 566.028000 1866.240000 566.052000 ;
 END
 END rx_flit[117]
 PIN rx_flit[118]
 DIRECTION OUTPUT ;
 USE SIGNAL ;
 PORT
 LAYER M4 ;
 RECT 1865.760000 566.172000 1866.240000 566.196000 ;
 END
 END rx_flit[118]
 PIN rx_flit[119]
 DIRECTION OUTPUT ;
 USE SIGNAL ;
 PORT
 LAYER M4 ;
 RECT 1865.760000 566.316000 1866.240000 566.340000 ;
 END
 END rx_flit[119]
 PIN rx_flit[120]
 DIRECTION OUTPUT ;
 USE SIGNAL ;
 PORT
 LAYER M4 ;
 RECT 1865.760000 566.460000 1866.240000 566.484000 ;
 END
 END rx_flit[120]
 PIN rx_flit[121]
 DIRECTION OUTPUT ;
 USE SIGNAL ;
 PORT
 LAYER M4 ;
 RECT 1865.760000 566.604000 1866.240000 566.628000 ;
 END
 END rx_flit[121]
 PIN rx_flit[122]
 DIRECTION OUTPUT ;
 USE SIGNAL ;
 PORT
 LAYER M4 ;
 RECT 1865.760000 566.748000 1866.240000 566.772000 ;
 END
 END rx_flit[122]
 PIN rx_flit[123]
 DIRECTION OUTPUT ;
 USE SIGNAL ;
 PORT
 LAYER M4 ;
 RECT 1865.760000 566.892000 1866.240000 566.916000 ;
 END
 END rx_flit[123]
 PIN rx_flit[124]
 DIRECTION OUTPUT ;
 USE SIGNAL ;
 PORT
 LAYER M4 ;
 RECT 1865.760000 567.036000 1866.240000 567.060000 ;
 END
 END rx_flit[124]
 PIN rx_flit[125]
 DIRECTION OUTPUT ;
 USE SIGNAL ;
 PORT
 LAYER M4 ;
 RECT 1865.760000 567.180000 1866.240000 567.204000 ;
 END
 END rx_flit[125]
 PIN rx_flit[126]
 DIRECTION OUTPUT ;
 USE SIGNAL ;
 PORT
 LAYER M4 ;
 RECT 1865.760000 567.324000 1866.240000 567.348000 ;
 END
 END rx_flit[126]
 PIN rx_flit[127]
 DIRECTION OUTPUT ;
 USE SIGNAL ;
 PORT
 LAYER M4 ;
 RECT 1865.760000 567.468000 1866.240000 567.492000 ;
 END
 END rx_flit[127]
 PIN rx_flit[128]
 DIRECTION OUTPUT ;
 USE SIGNAL ;
 PORT
 LAYER M4 ;
 RECT 1865.760000 567.612000 1866.240000 567.636000 ;
 END
 END rx_flit[128]
 PIN rx_flit[129]
 DIRECTION OUTPUT ;
 USE SIGNAL ;
 PORT
 LAYER M4 ;
 RECT 1865.760000 567.756000 1866.240000 567.780000 ;
 END
 END rx_flit[129]
 PIN rx_flit[130]
 DIRECTION OUTPUT ;
 USE SIGNAL ;
 PORT
 LAYER M4 ;
 RECT 1865.760000 567.900000 1866.240000 567.924000 ;
 END
 END rx_flit[130]
 PIN rx_flit[131]
 DIRECTION OUTPUT ;
 USE SIGNAL ;
 PORT
 LAYER M4 ;
 RECT 1865.760000 568.044000 1866.240000 568.068000 ;
 END
 END rx_flit[131]
 PIN rx_flit[132]
 DIRECTION OUTPUT ;
 USE SIGNAL ;
 PORT
 LAYER M4 ;
 RECT 1865.760000 568.188000 1866.240000 568.212000 ;
 END
 END rx_flit[132]
 PIN rx_flit[133]
 DIRECTION OUTPUT ;
 USE SIGNAL ;
 PORT
 LAYER M4 ;
 RECT 1865.760000 568.332000 1866.240000 568.356000 ;
 END
 END rx_flit[133]
 PIN rx_flit[134]
 DIRECTION OUTPUT ;
 USE SIGNAL ;
 PORT
 LAYER M4 ;
 RECT 1865.760000 568.476000 1866.240000 568.500000 ;
 END
 END rx_flit[134]
 PIN rx_flit[135]
 DIRECTION OUTPUT ;
 USE SIGNAL ;
 PORT
 LAYER M4 ;
 RECT 1865.760000 568.620000 1866.240000 568.644000 ;
 END
 END rx_flit[135]
 PIN rx_flit[136]
 DIRECTION OUTPUT ;
 USE SIGNAL ;
 PORT
 LAYER M4 ;
 RECT 1865.760000 568.764000 1866.240000 568.788000 ;
 END
 END rx_flit[136]
 PIN rx_flit[137]
 DIRECTION OUTPUT ;
 USE SIGNAL ;
 PORT
 LAYER M4 ;
 RECT 1865.760000 568.908000 1866.240000 568.932000 ;
 END
 END rx_flit[137]
 PIN rx_flit[138]
 DIRECTION OUTPUT ;
 USE SIGNAL ;
 PORT
 LAYER M4 ;
 RECT 1865.760000 569.052000 1866.240000 569.076000 ;
 END
 END rx_flit[138]
 PIN rx_flit[139]
 DIRECTION OUTPUT ;
 USE SIGNAL ;
 PORT
 LAYER M4 ;
 RECT 1865.760000 569.196000 1866.240000 569.220000 ;
 END
 END rx_flit[139]
 PIN rx_flit[140]
 DIRECTION OUTPUT ;
 USE SIGNAL ;
 PORT
 LAYER M4 ;
 RECT 1865.760000 569.340000 1866.240000 569.364000 ;
 END
 END rx_flit[140]
 PIN rx_flit[141]
 DIRECTION OUTPUT ;
 USE SIGNAL ;
 PORT
 LAYER M4 ;
 RECT 1865.760000 569.484000 1866.240000 569.508000 ;
 END
 END rx_flit[141]
 PIN rx_flit[142]
 DIRECTION OUTPUT ;
 USE SIGNAL ;
 PORT
 LAYER M4 ;
 RECT 1865.760000 569.628000 1866.240000 569.652000 ;
 END
 END rx_flit[142]
 PIN rx_flit[143]
 DIRECTION OUTPUT ;
 USE SIGNAL ;
 PORT
 LAYER M4 ;
 RECT 1865.760000 569.772000 1866.240000 569.796000 ;
 END
 END rx_flit[143]
 PIN rx_flit[144]
 DIRECTION OUTPUT ;
 USE SIGNAL ;
 PORT
 LAYER M4 ;
 RECT 1865.760000 569.916000 1866.240000 569.940000 ;
 END
 END rx_flit[144]
 PIN rx_flit[145]
 DIRECTION OUTPUT ;
 USE SIGNAL ;
 PORT
 LAYER M4 ;
 RECT 1865.760000 570.060000 1866.240000 570.084000 ;
 END
 END rx_flit[145]
 PIN rx_flit[146]
 DIRECTION OUTPUT ;
 USE SIGNAL ;
 PORT
 LAYER M4 ;
 RECT 1865.760000 570.204000 1866.240000 570.228000 ;
 END
 END rx_flit[146]
 PIN rx_flit[147]
 DIRECTION OUTPUT ;
 USE SIGNAL ;
 PORT
 LAYER M4 ;
 RECT 1865.760000 570.348000 1866.240000 570.372000 ;
 END
 END rx_flit[147]
 PIN rx_flit[148]
 DIRECTION OUTPUT ;
 USE SIGNAL ;
 PORT
 LAYER M4 ;
 RECT 1865.760000 570.492000 1866.240000 570.516000 ;
 END
 END rx_flit[148]
 PIN rx_flit[149]
 DIRECTION OUTPUT ;
 USE SIGNAL ;
 PORT
 LAYER M4 ;
 RECT 1865.760000 570.636000 1866.240000 570.660000 ;
 END
 END rx_flit[149]
 PIN rx_flit[150]
 DIRECTION OUTPUT ;
 USE SIGNAL ;
 PORT
 LAYER M4 ;
 RECT 1865.760000 570.780000 1866.240000 570.804000 ;
 END
 END rx_flit[150]
 PIN rx_flit[151]
 DIRECTION OUTPUT ;
 USE SIGNAL ;
 PORT
 LAYER M4 ;
 RECT 1865.760000 570.924000 1866.240000 570.948000 ;
 END
 END rx_flit[151]
 PIN rx_flit[152]
 DIRECTION OUTPUT ;
 USE SIGNAL ;
 PORT
 LAYER M4 ;
 RECT 1865.760000 571.068000 1866.240000 571.092000 ;
 END
 END rx_flit[152]
 PIN rx_flit[153]
 DIRECTION OUTPUT ;
 USE SIGNAL ;
 PORT
 LAYER M4 ;
 RECT 1865.760000 571.212000 1866.240000 571.236000 ;
 END
 END rx_flit[153]
 PIN rx_flit[154]
 DIRECTION OUTPUT ;
 USE SIGNAL ;
 PORT
 LAYER M4 ;
 RECT 1865.760000 571.356000 1866.240000 571.380000 ;
 END
 END rx_flit[154]
 PIN rx_flit[155]
 DIRECTION OUTPUT ;
 USE SIGNAL ;
 PORT
 LAYER M4 ;
 RECT 1865.760000 571.500000 1866.240000 571.524000 ;
 END
 END rx_flit[155]
 PIN rx_flit[156]
 DIRECTION OUTPUT ;
 USE SIGNAL ;
 PORT
 LAYER M4 ;
 RECT 1865.760000 571.644000 1866.240000 571.668000 ;
 END
 END rx_flit[156]
 PIN rx_flit[157]
 DIRECTION OUTPUT ;
 USE SIGNAL ;
 PORT
 LAYER M4 ;
 RECT 1865.760000 571.788000 1866.240000 571.812000 ;
 END
 END rx_flit[157]
 PIN rx_flit[158]
 DIRECTION OUTPUT ;
 USE SIGNAL ;
 PORT
 LAYER M4 ;
 RECT 1865.760000 571.932000 1866.240000 571.956000 ;
 END
 END rx_flit[158]
 PIN rx_flit[159]
 DIRECTION OUTPUT ;
 USE SIGNAL ;
 PORT
 LAYER M4 ;
 RECT 1865.760000 572.076000 1866.240000 572.100000 ;
 END
 END rx_flit[159]
 PIN rx_flit[160]
 DIRECTION OUTPUT ;
 USE SIGNAL ;
 PORT
 LAYER M4 ;
 RECT 1865.760000 572.220000 1866.240000 572.244000 ;
 END
 END rx_flit[160]
 PIN rx_flit[161]
 DIRECTION OUTPUT ;
 USE SIGNAL ;
 PORT
 LAYER M4 ;
 RECT 1865.760000 572.364000 1866.240000 572.388000 ;
 END
 END rx_flit[161]
 PIN rx_flit[162]
 DIRECTION OUTPUT ;
 USE SIGNAL ;
 PORT
 LAYER M4 ;
 RECT 1865.760000 572.508000 1866.240000 572.532000 ;
 END
 END rx_flit[162]
 PIN rx_flit[163]
 DIRECTION OUTPUT ;
 USE SIGNAL ;
 PORT
 LAYER M4 ;
 RECT 1865.760000 572.652000 1866.240000 572.676000 ;
 END
 END rx_flit[163]
 PIN rx_flit[164]
 DIRECTION OUTPUT ;
 USE SIGNAL ;
 PORT
 LAYER M4 ;
 RECT 1865.760000 572.796000 1866.240000 572.820000 ;
 END
 END rx_flit[164]
 PIN rx_flit[165]
 DIRECTION OUTPUT ;
 USE SIGNAL ;
 PORT
 LAYER M4 ;
 RECT 1865.760000 572.940000 1866.240000 572.964000 ;
 END
 END rx_flit[165]
 PIN rx_flit[166]
 DIRECTION OUTPUT ;
 USE SIGNAL ;
 PORT
 LAYER M4 ;
 RECT 1865.760000 573.084000 1866.240000 573.108000 ;
 END
 END rx_flit[166]
 PIN rx_flit[167]
 DIRECTION OUTPUT ;
 USE SIGNAL ;
 PORT
 LAYER M4 ;
 RECT 1865.760000 573.228000 1866.240000 573.252000 ;
 END
 END rx_flit[167]
 PIN rx_flit[168]
 DIRECTION OUTPUT ;
 USE SIGNAL ;
 PORT
 LAYER M4 ;
 RECT 1865.760000 573.372000 1866.240000 573.396000 ;
 END
 END rx_flit[168]
 PIN rx_flit[169]
 DIRECTION OUTPUT ;
 USE SIGNAL ;
 PORT
 LAYER M4 ;
 RECT 1865.760000 573.516000 1866.240000 573.540000 ;
 END
 END rx_flit[169]
 PIN rx_flit[170]
 DIRECTION OUTPUT ;
 USE SIGNAL ;
 PORT
 LAYER M4 ;
 RECT 1865.760000 573.660000 1866.240000 573.684000 ;
 END
 END rx_flit[170]
 PIN rx_flit[171]
 DIRECTION OUTPUT ;
 USE SIGNAL ;
 PORT
 LAYER M4 ;
 RECT 1865.760000 573.804000 1866.240000 573.828000 ;
 END
 END rx_flit[171]
 PIN rx_flit[172]
 DIRECTION OUTPUT ;
 USE SIGNAL ;
 PORT
 LAYER M4 ;
 RECT 1865.760000 573.948000 1866.240000 573.972000 ;
 END
 END rx_flit[172]
 PIN rx_flit[173]
 DIRECTION OUTPUT ;
 USE SIGNAL ;
 PORT
 LAYER M4 ;
 RECT 1865.760000 574.092000 1866.240000 574.116000 ;
 END
 END rx_flit[173]
 PIN rx_flit[174]
 DIRECTION OUTPUT ;
 USE SIGNAL ;
 PORT
 LAYER M4 ;
 RECT 1865.760000 574.236000 1866.240000 574.260000 ;
 END
 END rx_flit[174]
 PIN rx_flit[175]
 DIRECTION OUTPUT ;
 USE SIGNAL ;
 PORT
 LAYER M4 ;
 RECT 1865.760000 574.380000 1866.240000 574.404000 ;
 END
 END rx_flit[175]
 PIN rx_flit[176]
 DIRECTION OUTPUT ;
 USE SIGNAL ;
 PORT
 LAYER M4 ;
 RECT 1865.760000 574.524000 1866.240000 574.548000 ;
 END
 END rx_flit[176]
 PIN rx_flit[177]
 DIRECTION OUTPUT ;
 USE SIGNAL ;
 PORT
 LAYER M4 ;
 RECT 1865.760000 574.668000 1866.240000 574.692000 ;
 END
 END rx_flit[177]
 PIN rx_flit[178]
 DIRECTION OUTPUT ;
 USE SIGNAL ;
 PORT
 LAYER M4 ;
 RECT 1865.760000 574.812000 1866.240000 574.836000 ;
 END
 END rx_flit[178]
 PIN rx_flit[179]
 DIRECTION OUTPUT ;
 USE SIGNAL ;
 PORT
 LAYER M4 ;
 RECT 1865.760000 574.956000 1866.240000 574.980000 ;
 END
 END rx_flit[179]
 PIN rx_flit[180]
 DIRECTION OUTPUT ;
 USE SIGNAL ;
 PORT
 LAYER M4 ;
 RECT 1865.760000 575.100000 1866.240000 575.124000 ;
 END
 END rx_flit[180]
 PIN rx_flit[181]
 DIRECTION OUTPUT ;
 USE SIGNAL ;
 PORT
 LAYER M4 ;
 RECT 1865.760000 575.244000 1866.240000 575.268000 ;
 END
 END rx_flit[181]
 PIN rx_flit[182]
 DIRECTION OUTPUT ;
 USE SIGNAL ;
 PORT
 LAYER M4 ;
 RECT 1865.760000 575.388000 1866.240000 575.412000 ;
 END
 END rx_flit[182]
 PIN rx_flit[183]
 DIRECTION OUTPUT ;
 USE SIGNAL ;
 PORT
 LAYER M4 ;
 RECT 1865.760000 575.532000 1866.240000 575.556000 ;
 END
 END rx_flit[183]
 PIN rx_flit[184]
 DIRECTION OUTPUT ;
 USE SIGNAL ;
 PORT
 LAYER M4 ;
 RECT 1865.760000 575.676000 1866.240000 575.700000 ;
 END
 END rx_flit[184]
 PIN rx_flit[185]
 DIRECTION OUTPUT ;
 USE SIGNAL ;
 PORT
 LAYER M4 ;
 RECT 1865.760000 575.820000 1866.240000 575.844000 ;
 END
 END rx_flit[185]
 PIN rx_flit[186]
 DIRECTION OUTPUT ;
 USE SIGNAL ;
 PORT
 LAYER M4 ;
 RECT 1865.760000 575.964000 1866.240000 575.988000 ;
 END
 END rx_flit[186]
 PIN rx_flit[187]
 DIRECTION OUTPUT ;
 USE SIGNAL ;
 PORT
 LAYER M4 ;
 RECT 1865.760000 576.108000 1866.240000 576.132000 ;
 END
 END rx_flit[187]
 PIN rx_flit[188]
 DIRECTION OUTPUT ;
 USE SIGNAL ;
 PORT
 LAYER M4 ;
 RECT 1865.760000 576.252000 1866.240000 576.276000 ;
 END
 END rx_flit[188]
 PIN rx_flit[189]
 DIRECTION OUTPUT ;
 USE SIGNAL ;
 PORT
 LAYER M4 ;
 RECT 1865.760000 576.396000 1866.240000 576.420000 ;
 END
 END rx_flit[189]
 PIN rx_flit[190]
 DIRECTION OUTPUT ;
 USE SIGNAL ;
 PORT
 LAYER M4 ;
 RECT 1865.760000 576.540000 1866.240000 576.564000 ;
 END
 END rx_flit[190]
 PIN rx_flit[191]
 DIRECTION OUTPUT ;
 USE SIGNAL ;
 PORT
 LAYER M4 ;
 RECT 1865.760000 576.684000 1866.240000 576.708000 ;
 END
 END rx_flit[191]
 PIN rx_flit[192]
 DIRECTION OUTPUT ;
 USE SIGNAL ;
 PORT
 LAYER M4 ;
 RECT 1865.760000 576.828000 1866.240000 576.852000 ;
 END
 END rx_flit[192]
 PIN rx_flit[193]
 DIRECTION OUTPUT ;
 USE SIGNAL ;
 PORT
 LAYER M4 ;
 RECT 1865.760000 576.972000 1866.240000 576.996000 ;
 END
 END rx_flit[193]
 PIN rx_flit[194]
 DIRECTION OUTPUT ;
 USE SIGNAL ;
 PORT
 LAYER M4 ;
 RECT 1865.760000 577.116000 1866.240000 577.140000 ;
 END
 END rx_flit[194]
 PIN rx_flit[195]
 DIRECTION OUTPUT ;
 USE SIGNAL ;
 PORT
 LAYER M4 ;
 RECT 1865.760000 577.260000 1866.240000 577.284000 ;
 END
 END rx_flit[195]
 PIN rx_flit[196]
 DIRECTION OUTPUT ;
 USE SIGNAL ;
 PORT
 LAYER M4 ;
 RECT 1865.760000 577.404000 1866.240000 577.428000 ;
 END
 END rx_flit[196]
 PIN rx_flit[197]
 DIRECTION OUTPUT ;
 USE SIGNAL ;
 PORT
 LAYER M4 ;
 RECT 1865.760000 577.548000 1866.240000 577.572000 ;
 END
 END rx_flit[197]
 PIN rx_flit[198]
 DIRECTION OUTPUT ;
 USE SIGNAL ;
 PORT
 LAYER M4 ;
 RECT 1865.760000 577.692000 1866.240000 577.716000 ;
 END
 END rx_flit[198]
 PIN rx_flit[199]
 DIRECTION OUTPUT ;
 USE SIGNAL ;
 PORT
 LAYER M4 ;
 RECT 1865.760000 577.836000 1866.240000 577.860000 ;
 END
 END rx_flit[199]
 PIN rx_flit[200]
 DIRECTION OUTPUT ;
 USE SIGNAL ;
 PORT
 LAYER M4 ;
 RECT 1865.760000 577.980000 1866.240000 578.004000 ;
 END
 END rx_flit[200]
 PIN rx_flit[201]
 DIRECTION OUTPUT ;
 USE SIGNAL ;
 PORT
 LAYER M4 ;
 RECT 1865.760000 578.124000 1866.240000 578.148000 ;
 END
 END rx_flit[201]
 PIN rx_flit[202]
 DIRECTION OUTPUT ;
 USE SIGNAL ;
 PORT
 LAYER M4 ;
 RECT 1865.760000 578.268000 1866.240000 578.292000 ;
 END
 END rx_flit[202]
 PIN rx_flit[203]
 DIRECTION OUTPUT ;
 USE SIGNAL ;
 PORT
 LAYER M4 ;
 RECT 1865.760000 578.412000 1866.240000 578.436000 ;
 END
 END rx_flit[203]
 PIN rx_flit[204]
 DIRECTION OUTPUT ;
 USE SIGNAL ;
 PORT
 LAYER M4 ;
 RECT 1865.760000 578.556000 1866.240000 578.580000 ;
 END
 END rx_flit[204]
 PIN rx_flit[205]
 DIRECTION OUTPUT ;
 USE SIGNAL ;
 PORT
 LAYER M4 ;
 RECT 1865.760000 578.700000 1866.240000 578.724000 ;
 END
 END rx_flit[205]
 PIN rx_flit[206]
 DIRECTION OUTPUT ;
 USE SIGNAL ;
 PORT
 LAYER M4 ;
 RECT 1865.760000 578.844000 1866.240000 578.868000 ;
 END
 END rx_flit[206]
 PIN rx_flit[207]
 DIRECTION OUTPUT ;
 USE SIGNAL ;
 PORT
 LAYER M4 ;
 RECT 1865.760000 578.988000 1866.240000 579.012000 ;
 END
 END rx_flit[207]
 PIN rx_flit[208]
 DIRECTION OUTPUT ;
 USE SIGNAL ;
 PORT
 LAYER M4 ;
 RECT 1865.760000 579.132000 1866.240000 579.156000 ;
 END
 END rx_flit[208]
 PIN rx_flit[209]
 DIRECTION OUTPUT ;
 USE SIGNAL ;
 PORT
 LAYER M4 ;
 RECT 1865.760000 579.276000 1866.240000 579.300000 ;
 END
 END rx_flit[209]
 PIN rx_flit[210]
 DIRECTION OUTPUT ;
 USE SIGNAL ;
 PORT
 LAYER M4 ;
 RECT 1865.760000 579.420000 1866.240000 579.444000 ;
 END
 END rx_flit[210]
 PIN rx_flit[211]
 DIRECTION OUTPUT ;
 USE SIGNAL ;
 PORT
 LAYER M4 ;
 RECT 1865.760000 579.564000 1866.240000 579.588000 ;
 END
 END rx_flit[211]
 PIN rx_flit[212]
 DIRECTION OUTPUT ;
 USE SIGNAL ;
 PORT
 LAYER M4 ;
 RECT 1865.760000 579.708000 1866.240000 579.732000 ;
 END
 END rx_flit[212]
 PIN rx_flit[213]
 DIRECTION OUTPUT ;
 USE SIGNAL ;
 PORT
 LAYER M4 ;
 RECT 1865.760000 579.852000 1866.240000 579.876000 ;
 END
 END rx_flit[213]
 PIN rx_flit[214]
 DIRECTION OUTPUT ;
 USE SIGNAL ;
 PORT
 LAYER M4 ;
 RECT 1865.760000 579.996000 1866.240000 580.020000 ;
 END
 END rx_flit[214]
 PIN rx_flit[215]
 DIRECTION OUTPUT ;
 USE SIGNAL ;
 PORT
 LAYER M4 ;
 RECT 1865.760000 580.140000 1866.240000 580.164000 ;
 END
 END rx_flit[215]
 PIN rx_flit[216]
 DIRECTION OUTPUT ;
 USE SIGNAL ;
 PORT
 LAYER M4 ;
 RECT 1865.760000 580.284000 1866.240000 580.308000 ;
 END
 END rx_flit[216]
 PIN rx_flit[217]
 DIRECTION OUTPUT ;
 USE SIGNAL ;
 PORT
 LAYER M4 ;
 RECT 1865.760000 580.428000 1866.240000 580.452000 ;
 END
 END rx_flit[217]
 PIN rx_flit[218]
 DIRECTION OUTPUT ;
 USE SIGNAL ;
 PORT
 LAYER M4 ;
 RECT 1865.760000 580.572000 1866.240000 580.596000 ;
 END
 END rx_flit[218]
 PIN rx_flit[219]
 DIRECTION OUTPUT ;
 USE SIGNAL ;
 PORT
 LAYER M4 ;
 RECT 1865.760000 580.716000 1866.240000 580.740000 ;
 END
 END rx_flit[219]
 PIN rx_flit[220]
 DIRECTION OUTPUT ;
 USE SIGNAL ;
 PORT
 LAYER M4 ;
 RECT 1865.760000 580.860000 1866.240000 580.884000 ;
 END
 END rx_flit[220]
 PIN rx_flit[221]
 DIRECTION OUTPUT ;
 USE SIGNAL ;
 PORT
 LAYER M4 ;
 RECT 1865.760000 581.004000 1866.240000 581.028000 ;
 END
 END rx_flit[221]
 PIN rx_flit[222]
 DIRECTION OUTPUT ;
 USE SIGNAL ;
 PORT
 LAYER M4 ;
 RECT 1865.760000 581.148000 1866.240000 581.172000 ;
 END
 END rx_flit[222]
 PIN rx_flit[223]
 DIRECTION OUTPUT ;
 USE SIGNAL ;
 PORT
 LAYER M4 ;
 RECT 1865.760000 581.292000 1866.240000 581.316000 ;
 END
 END rx_flit[223]
 PIN rx_flit[224]
 DIRECTION OUTPUT ;
 USE SIGNAL ;
 PORT
 LAYER M4 ;
 RECT 1865.760000 581.436000 1866.240000 581.460000 ;
 END
 END rx_flit[224]
 PIN rx_flit[225]
 DIRECTION OUTPUT ;
 USE SIGNAL ;
 PORT
 LAYER M4 ;
 RECT 1865.760000 581.580000 1866.240000 581.604000 ;
 END
 END rx_flit[225]
 PIN rx_flit[226]
 DIRECTION OUTPUT ;
 USE SIGNAL ;
 PORT
 LAYER M4 ;
 RECT 1865.760000 581.724000 1866.240000 581.748000 ;
 END
 END rx_flit[226]
 PIN rx_flit[227]
 DIRECTION OUTPUT ;
 USE SIGNAL ;
 PORT
 LAYER M4 ;
 RECT 1865.760000 581.868000 1866.240000 581.892000 ;
 END
 END rx_flit[227]
 PIN rx_flit[228]
 DIRECTION OUTPUT ;
 USE SIGNAL ;
 PORT
 LAYER M4 ;
 RECT 1865.760000 582.012000 1866.240000 582.036000 ;
 END
 END rx_flit[228]
 PIN rx_flit[229]
 DIRECTION OUTPUT ;
 USE SIGNAL ;
 PORT
 LAYER M4 ;
 RECT 1865.760000 582.156000 1866.240000 582.180000 ;
 END
 END rx_flit[229]
 PIN rx_flit[230]
 DIRECTION OUTPUT ;
 USE SIGNAL ;
 PORT
 LAYER M4 ;
 RECT 1865.760000 582.300000 1866.240000 582.324000 ;
 END
 END rx_flit[230]
 PIN rx_flit[231]
 DIRECTION OUTPUT ;
 USE SIGNAL ;
 PORT
 LAYER M4 ;
 RECT 1865.760000 582.444000 1866.240000 582.468000 ;
 END
 END rx_flit[231]
 PIN rx_flit[232]
 DIRECTION OUTPUT ;
 USE SIGNAL ;
 PORT
 LAYER M4 ;
 RECT 1865.760000 582.588000 1866.240000 582.612000 ;
 END
 END rx_flit[232]
 PIN rx_flit[233]
 DIRECTION OUTPUT ;
 USE SIGNAL ;
 PORT
 LAYER M4 ;
 RECT 1865.760000 582.732000 1866.240000 582.756000 ;
 END
 END rx_flit[233]
 PIN rx_flit[234]
 DIRECTION OUTPUT ;
 USE SIGNAL ;
 PORT
 LAYER M4 ;
 RECT 1865.760000 582.876000 1866.240000 582.900000 ;
 END
 END rx_flit[234]
 PIN rx_flit[235]
 DIRECTION OUTPUT ;
 USE SIGNAL ;
 PORT
 LAYER M4 ;
 RECT 1865.760000 583.020000 1866.240000 583.044000 ;
 END
 END rx_flit[235]
 PIN rx_flit[236]
 DIRECTION OUTPUT ;
 USE SIGNAL ;
 PORT
 LAYER M4 ;
 RECT 1865.760000 583.164000 1866.240000 583.188000 ;
 END
 END rx_flit[236]
 PIN rx_flit[237]
 DIRECTION OUTPUT ;
 USE SIGNAL ;
 PORT
 LAYER M4 ;
 RECT 1865.760000 583.308000 1866.240000 583.332000 ;
 END
 END rx_flit[237]
 PIN rx_flit[238]
 DIRECTION OUTPUT ;
 USE SIGNAL ;
 PORT
 LAYER M4 ;
 RECT 1865.760000 583.452000 1866.240000 583.476000 ;
 END
 END rx_flit[238]
 PIN rx_flit[239]
 DIRECTION OUTPUT ;
 USE SIGNAL ;
 PORT
 LAYER M4 ;
 RECT 1865.760000 583.596000 1866.240000 583.620000 ;
 END
 END rx_flit[239]
 PIN rx_flit[240]
 DIRECTION OUTPUT ;
 USE SIGNAL ;
 PORT
 LAYER M4 ;
 RECT 1865.760000 583.740000 1866.240000 583.764000 ;
 END
 END rx_flit[240]
 PIN rx_flit[241]
 DIRECTION OUTPUT ;
 USE SIGNAL ;
 PORT
 LAYER M4 ;
 RECT 1865.760000 583.884000 1866.240000 583.908000 ;
 END
 END rx_flit[241]
 PIN rx_flit[242]
 DIRECTION OUTPUT ;
 USE SIGNAL ;
 PORT
 LAYER M4 ;
 RECT 1865.760000 584.028000 1866.240000 584.052000 ;
 END
 END rx_flit[242]
 PIN rx_flit[243]
 DIRECTION OUTPUT ;
 USE SIGNAL ;
 PORT
 LAYER M4 ;
 RECT 1865.760000 584.172000 1866.240000 584.196000 ;
 END
 END rx_flit[243]
 PIN rx_flit[244]
 DIRECTION OUTPUT ;
 USE SIGNAL ;
 PORT
 LAYER M4 ;
 RECT 1865.760000 584.316000 1866.240000 584.340000 ;
 END
 END rx_flit[244]
 PIN rx_flit[245]
 DIRECTION OUTPUT ;
 USE SIGNAL ;
 PORT
 LAYER M4 ;
 RECT 1865.760000 584.460000 1866.240000 584.484000 ;
 END
 END rx_flit[245]
 PIN rx_flit[246]
 DIRECTION OUTPUT ;
 USE SIGNAL ;
 PORT
 LAYER M4 ;
 RECT 1865.760000 584.604000 1866.240000 584.628000 ;
 END
 END rx_flit[246]
 PIN rx_flit[247]
 DIRECTION OUTPUT ;
 USE SIGNAL ;
 PORT
 LAYER M4 ;
 RECT 1865.760000 584.748000 1866.240000 584.772000 ;
 END
 END rx_flit[247]
 PIN rx_flit[248]
 DIRECTION OUTPUT ;
 USE SIGNAL ;
 PORT
 LAYER M4 ;
 RECT 1865.760000 584.892000 1866.240000 584.916000 ;
 END
 END rx_flit[248]
 PIN rx_flit[249]
 DIRECTION OUTPUT ;
 USE SIGNAL ;
 PORT
 LAYER M4 ;
 RECT 1865.760000 585.036000 1866.240000 585.060000 ;
 END
 END rx_flit[249]
 PIN rx_flit[250]
 DIRECTION OUTPUT ;
 USE SIGNAL ;
 PORT
 LAYER M4 ;
 RECT 1865.760000 585.180000 1866.240000 585.204000 ;
 END
 END rx_flit[250]
 PIN rx_flit[251]
 DIRECTION OUTPUT ;
 USE SIGNAL ;
 PORT
 LAYER M4 ;
 RECT 1865.760000 585.324000 1866.240000 585.348000 ;
 END
 END rx_flit[251]
 PIN rx_flit[252]
 DIRECTION OUTPUT ;
 USE SIGNAL ;
 PORT
 LAYER M4 ;
 RECT 1865.760000 585.468000 1866.240000 585.492000 ;
 END
 END rx_flit[252]
 PIN rx_flit[253]
 DIRECTION OUTPUT ;
 USE SIGNAL ;
 PORT
 LAYER M4 ;
 RECT 1865.760000 585.612000 1866.240000 585.636000 ;
 END
 END rx_flit[253]
 PIN rx_flit[254]
 DIRECTION OUTPUT ;
 USE SIGNAL ;
 PORT
 LAYER M4 ;
 RECT 1865.760000 585.756000 1866.240000 585.780000 ;
 END
 END rx_flit[254]
 PIN rx_flit[255]
 DIRECTION OUTPUT ;
 USE SIGNAL ;
 PORT
 LAYER M4 ;
 RECT 1865.760000 585.900000 1866.240000 585.924000 ;
 END
 END rx_flit[255]
 PIN rx_flit[256]
 DIRECTION OUTPUT ;
 USE SIGNAL ;
 PORT
 LAYER M4 ;
 RECT 1865.760000 586.044000 1866.240000 586.068000 ;
 END
 END rx_flit[256]
 PIN rx_flit[257]
 DIRECTION OUTPUT ;
 USE SIGNAL ;
 PORT
 LAYER M4 ;
 RECT 1865.760000 586.188000 1866.240000 586.212000 ;
 END
 END rx_flit[257]
 PIN rx_flit[258]
 DIRECTION OUTPUT ;
 USE SIGNAL ;
 PORT
 LAYER M4 ;
 RECT 1865.760000 586.332000 1866.240000 586.356000 ;
 END
 END rx_flit[258]
 PIN rx_flit[259]
 DIRECTION OUTPUT ;
 USE SIGNAL ;
 PORT
 LAYER M4 ;
 RECT 1865.760000 586.476000 1866.240000 586.500000 ;
 END
 END rx_flit[259]
 PIN rx_flit[260]
 DIRECTION OUTPUT ;
 USE SIGNAL ;
 PORT
 LAYER M4 ;
 RECT 1865.760000 586.620000 1866.240000 586.644000 ;
 END
 END rx_flit[260]
 PIN rx_flit[261]
 DIRECTION OUTPUT ;
 USE SIGNAL ;
 PORT
 LAYER M4 ;
 RECT 1865.760000 586.764000 1866.240000 586.788000 ;
 END
 END rx_flit[261]
 PIN rx_flit[262]
 DIRECTION OUTPUT ;
 USE SIGNAL ;
 PORT
 LAYER M4 ;
 RECT 1865.760000 586.908000 1866.240000 586.932000 ;
 END
 END rx_flit[262]
 PIN rx_flit[263]
 DIRECTION OUTPUT ;
 USE SIGNAL ;
 PORT
 LAYER M4 ;
 RECT 1865.760000 587.052000 1866.240000 587.076000 ;
 END
 END rx_flit[263]
 PIN rx_flit[264]
 DIRECTION OUTPUT ;
 USE SIGNAL ;
 PORT
 LAYER M4 ;
 RECT 1865.760000 587.196000 1866.240000 587.220000 ;
 END
 END rx_flit[264]
 PIN rx_flit[265]
 DIRECTION OUTPUT ;
 USE SIGNAL ;
 PORT
 LAYER M4 ;
 RECT 1865.760000 587.340000 1866.240000 587.364000 ;
 END
 END rx_flit[265]
 PIN rx_flit[266]
 DIRECTION OUTPUT ;
 USE SIGNAL ;
 PORT
 LAYER M4 ;
 RECT 1865.760000 587.484000 1866.240000 587.508000 ;
 END
 END rx_flit[266]
 PIN rx_flit[267]
 DIRECTION OUTPUT ;
 USE SIGNAL ;
 PORT
 LAYER M4 ;
 RECT 1865.760000 587.628000 1866.240000 587.652000 ;
 END
 END rx_flit[267]
 PIN rx_flit[268]
 DIRECTION OUTPUT ;
 USE SIGNAL ;
 PORT
 LAYER M4 ;
 RECT 1865.760000 587.772000 1866.240000 587.796000 ;
 END
 END rx_flit[268]
 PIN rx_flit[269]
 DIRECTION OUTPUT ;
 USE SIGNAL ;
 PORT
 LAYER M4 ;
 RECT 1865.760000 587.916000 1866.240000 587.940000 ;
 END
 END rx_flit[269]
 PIN rx_flit[270]
 DIRECTION OUTPUT ;
 USE SIGNAL ;
 PORT
 LAYER M4 ;
 RECT 1865.760000 588.060000 1866.240000 588.084000 ;
 END
 END rx_flit[270]
 PIN rx_flit[271]
 DIRECTION OUTPUT ;
 USE SIGNAL ;
 PORT
 LAYER M4 ;
 RECT 1865.760000 588.204000 1866.240000 588.228000 ;
 END
 END rx_flit[271]
 PIN rx_flit[272]
 DIRECTION OUTPUT ;
 USE SIGNAL ;
 PORT
 LAYER M4 ;
 RECT 1865.760000 588.348000 1866.240000 588.372000 ;
 END
 END rx_flit[272]
 PIN rx_flit[273]
 DIRECTION OUTPUT ;
 USE SIGNAL ;
 PORT
 LAYER M4 ;
 RECT 1865.760000 588.492000 1866.240000 588.516000 ;
 END
 END rx_flit[273]
 PIN rx_flit[274]
 DIRECTION OUTPUT ;
 USE SIGNAL ;
 PORT
 LAYER M4 ;
 RECT 1865.760000 588.636000 1866.240000 588.660000 ;
 END
 END rx_flit[274]
 PIN rx_flit[275]
 DIRECTION OUTPUT ;
 USE SIGNAL ;
 PORT
 LAYER M4 ;
 RECT 1865.760000 588.780000 1866.240000 588.804000 ;
 END
 END rx_flit[275]
 PIN rx_flit[276]
 DIRECTION OUTPUT ;
 USE SIGNAL ;
 PORT
 LAYER M4 ;
 RECT 1865.760000 588.924000 1866.240000 588.948000 ;
 END
 END rx_flit[276]
 PIN rx_flit[277]
 DIRECTION OUTPUT ;
 USE SIGNAL ;
 PORT
 LAYER M4 ;
 RECT 1865.760000 589.068000 1866.240000 589.092000 ;
 END
 END rx_flit[277]
 PIN rx_flit[278]
 DIRECTION OUTPUT ;
 USE SIGNAL ;
 PORT
 LAYER M4 ;
 RECT 1865.760000 589.212000 1866.240000 589.236000 ;
 END
 END rx_flit[278]
 PIN rx_flit[279]
 DIRECTION OUTPUT ;
 USE SIGNAL ;
 PORT
 LAYER M4 ;
 RECT 1865.760000 589.356000 1866.240000 589.380000 ;
 END
 END rx_flit[279]
 PIN rx_flit[280]
 DIRECTION OUTPUT ;
 USE SIGNAL ;
 PORT
 LAYER M4 ;
 RECT 1865.760000 589.500000 1866.240000 589.524000 ;
 END
 END rx_flit[280]
 PIN rx_flit[281]
 DIRECTION OUTPUT ;
 USE SIGNAL ;
 PORT
 LAYER M4 ;
 RECT 1865.760000 589.644000 1866.240000 589.668000 ;
 END
 END rx_flit[281]
 PIN rx_flit[282]
 DIRECTION OUTPUT ;
 USE SIGNAL ;
 PORT
 LAYER M4 ;
 RECT 1865.760000 589.788000 1866.240000 589.812000 ;
 END
 END rx_flit[282]
 PIN rx_flit[283]
 DIRECTION OUTPUT ;
 USE SIGNAL ;
 PORT
 LAYER M4 ;
 RECT 1865.760000 589.932000 1866.240000 589.956000 ;
 END
 END rx_flit[283]
 PIN rx_flit[284]
 DIRECTION OUTPUT ;
 USE SIGNAL ;
 PORT
 LAYER M4 ;
 RECT 1865.760000 590.076000 1866.240000 590.100000 ;
 END
 END rx_flit[284]
 PIN rx_flit[285]
 DIRECTION OUTPUT ;
 USE SIGNAL ;
 PORT
 LAYER M4 ;
 RECT 1865.760000 590.220000 1866.240000 590.244000 ;
 END
 END rx_flit[285]
 PIN rx_flit[286]
 DIRECTION OUTPUT ;
 USE SIGNAL ;
 PORT
 LAYER M4 ;
 RECT 1865.760000 590.364000 1866.240000 590.388000 ;
 END
 END rx_flit[286]
 PIN rx_flit[287]
 DIRECTION OUTPUT ;
 USE SIGNAL ;
 PORT
 LAYER M4 ;
 RECT 1865.760000 590.508000 1866.240000 590.532000 ;
 END
 END rx_flit[287]
 PIN rx_flit[288]
 DIRECTION OUTPUT ;
 USE SIGNAL ;
 PORT
 LAYER M4 ;
 RECT 1865.760000 590.652000 1866.240000 590.676000 ;
 END
 END rx_flit[288]
 PIN rx_flit[289]
 DIRECTION OUTPUT ;
 USE SIGNAL ;
 PORT
 LAYER M4 ;
 RECT 1865.760000 590.796000 1866.240000 590.820000 ;
 END
 END rx_flit[289]
 PIN rx_flit[290]
 DIRECTION OUTPUT ;
 USE SIGNAL ;
 PORT
 LAYER M4 ;
 RECT 1865.760000 590.940000 1866.240000 590.964000 ;
 END
 END rx_flit[290]
 PIN rx_flit[291]
 DIRECTION OUTPUT ;
 USE SIGNAL ;
 PORT
 LAYER M4 ;
 RECT 1865.760000 591.084000 1866.240000 591.108000 ;
 END
 END rx_flit[291]
 PIN rx_flit[292]
 DIRECTION OUTPUT ;
 USE SIGNAL ;
 PORT
 LAYER M4 ;
 RECT 1865.760000 591.228000 1866.240000 591.252000 ;
 END
 END rx_flit[292]
 PIN rx_flit[293]
 DIRECTION OUTPUT ;
 USE SIGNAL ;
 PORT
 LAYER M4 ;
 RECT 1865.760000 591.372000 1866.240000 591.396000 ;
 END
 END rx_flit[293]
 PIN rx_flit[294]
 DIRECTION OUTPUT ;
 USE SIGNAL ;
 PORT
 LAYER M4 ;
 RECT 1865.760000 591.516000 1866.240000 591.540000 ;
 END
 END rx_flit[294]
 PIN rx_flit[295]
 DIRECTION OUTPUT ;
 USE SIGNAL ;
 PORT
 LAYER M4 ;
 RECT 1865.760000 591.660000 1866.240000 591.684000 ;
 END
 END rx_flit[295]
 PIN rx_flit[296]
 DIRECTION OUTPUT ;
 USE SIGNAL ;
 PORT
 LAYER M4 ;
 RECT 1865.760000 591.804000 1866.240000 591.828000 ;
 END
 END rx_flit[296]
 PIN rx_flit[297]
 DIRECTION OUTPUT ;
 USE SIGNAL ;
 PORT
 LAYER M4 ;
 RECT 1865.760000 591.948000 1866.240000 591.972000 ;
 END
 END rx_flit[297]
 PIN rx_flit[298]
 DIRECTION OUTPUT ;
 USE SIGNAL ;
 PORT
 LAYER M4 ;
 RECT 1865.760000 592.092000 1866.240000 592.116000 ;
 END
 END rx_flit[298]
 PIN rx_flit[299]
 DIRECTION OUTPUT ;
 USE SIGNAL ;
 PORT
 LAYER M4 ;
 RECT 1865.760000 592.236000 1866.240000 592.260000 ;
 END
 END rx_flit[299]
 PIN rx_flit[300]
 DIRECTION OUTPUT ;
 USE SIGNAL ;
 PORT
 LAYER M4 ;
 RECT 1865.760000 592.380000 1866.240000 592.404000 ;
 END
 END rx_flit[300]
 PIN rx_flit[301]
 DIRECTION OUTPUT ;
 USE SIGNAL ;
 PORT
 LAYER M4 ;
 RECT 1865.760000 592.524000 1866.240000 592.548000 ;
 END
 END rx_flit[301]
 PIN rx_flit[302]
 DIRECTION OUTPUT ;
 USE SIGNAL ;
 PORT
 LAYER M4 ;
 RECT 1865.760000 592.668000 1866.240000 592.692000 ;
 END
 END rx_flit[302]
 PIN rx_flit[303]
 DIRECTION OUTPUT ;
 USE SIGNAL ;
 PORT
 LAYER M4 ;
 RECT 1865.760000 592.812000 1866.240000 592.836000 ;
 END
 END rx_flit[303]
 PIN rx_flit[304]
 DIRECTION OUTPUT ;
 USE SIGNAL ;
 PORT
 LAYER M4 ;
 RECT 1865.760000 592.956000 1866.240000 592.980000 ;
 END
 END rx_flit[304]
 PIN rx_flit[305]
 DIRECTION OUTPUT ;
 USE SIGNAL ;
 PORT
 LAYER M4 ;
 RECT 1865.760000 593.100000 1866.240000 593.124000 ;
 END
 END rx_flit[305]
 PIN rx_flit[306]
 DIRECTION OUTPUT ;
 USE SIGNAL ;
 PORT
 LAYER M4 ;
 RECT 1865.760000 593.244000 1866.240000 593.268000 ;
 END
 END rx_flit[306]
 PIN rx_flit[307]
 DIRECTION OUTPUT ;
 USE SIGNAL ;
 PORT
 LAYER M4 ;
 RECT 1865.760000 593.388000 1866.240000 593.412000 ;
 END
 END rx_flit[307]
 PIN rx_flit[308]
 DIRECTION OUTPUT ;
 USE SIGNAL ;
 PORT
 LAYER M4 ;
 RECT 1865.760000 593.532000 1866.240000 593.556000 ;
 END
 END rx_flit[308]
 PIN rx_flit[309]
 DIRECTION OUTPUT ;
 USE SIGNAL ;
 PORT
 LAYER M4 ;
 RECT 1865.760000 593.676000 1866.240000 593.700000 ;
 END
 END rx_flit[309]
 PIN rx_flit[310]
 DIRECTION OUTPUT ;
 USE SIGNAL ;
 PORT
 LAYER M4 ;
 RECT 1865.760000 593.820000 1866.240000 593.844000 ;
 END
 END rx_flit[310]
 PIN rx_flit[311]
 DIRECTION OUTPUT ;
 USE SIGNAL ;
 PORT
 LAYER M4 ;
 RECT 1865.760000 593.964000 1866.240000 593.988000 ;
 END
 END rx_flit[311]
 PIN rx_flit[312]
 DIRECTION OUTPUT ;
 USE SIGNAL ;
 PORT
 LAYER M4 ;
 RECT 1865.760000 594.108000 1866.240000 594.132000 ;
 END
 END rx_flit[312]
 PIN rx_flit[313]
 DIRECTION OUTPUT ;
 USE SIGNAL ;
 PORT
 LAYER M4 ;
 RECT 1865.760000 594.252000 1866.240000 594.276000 ;
 END
 END rx_flit[313]
 PIN rx_flit[314]
 DIRECTION OUTPUT ;
 USE SIGNAL ;
 PORT
 LAYER M4 ;
 RECT 1865.760000 594.396000 1866.240000 594.420000 ;
 END
 END rx_flit[314]
 PIN rx_flit[315]
 DIRECTION OUTPUT ;
 USE SIGNAL ;
 PORT
 LAYER M4 ;
 RECT 1865.760000 594.540000 1866.240000 594.564000 ;
 END
 END rx_flit[315]
 PIN rx_flit[316]
 DIRECTION OUTPUT ;
 USE SIGNAL ;
 PORT
 LAYER M4 ;
 RECT 1865.760000 594.684000 1866.240000 594.708000 ;
 END
 END rx_flit[316]
 PIN rx_flit[317]
 DIRECTION OUTPUT ;
 USE SIGNAL ;
 PORT
 LAYER M4 ;
 RECT 1865.760000 594.828000 1866.240000 594.852000 ;
 END
 END rx_flit[317]
 PIN rx_flit[318]
 DIRECTION OUTPUT ;
 USE SIGNAL ;
 PORT
 LAYER M4 ;
 RECT 1865.760000 594.972000 1866.240000 594.996000 ;
 END
 END rx_flit[318]
 PIN rx_flit[319]
 DIRECTION OUTPUT ;
 USE SIGNAL ;
 PORT
 LAYER M4 ;
 RECT 1865.760000 595.116000 1866.240000 595.140000 ;
 END
 END rx_flit[319]
 PIN rx_flit[320]
 DIRECTION OUTPUT ;
 USE SIGNAL ;
 PORT
 LAYER M4 ;
 RECT 1865.760000 595.260000 1866.240000 595.284000 ;
 END
 END rx_flit[320]
 PIN rx_flit[321]
 DIRECTION OUTPUT ;
 USE SIGNAL ;
 PORT
 LAYER M4 ;
 RECT 1865.760000 595.404000 1866.240000 595.428000 ;
 END
 END rx_flit[321]
 PIN rx_flit[322]
 DIRECTION OUTPUT ;
 USE SIGNAL ;
 PORT
 LAYER M4 ;
 RECT 1865.760000 595.548000 1866.240000 595.572000 ;
 END
 END rx_flit[322]
 PIN rx_flit[323]
 DIRECTION OUTPUT ;
 USE SIGNAL ;
 PORT
 LAYER M4 ;
 RECT 1865.760000 595.692000 1866.240000 595.716000 ;
 END
 END rx_flit[323]
 PIN rx_flit[324]
 DIRECTION OUTPUT ;
 USE SIGNAL ;
 PORT
 LAYER M4 ;
 RECT 1865.760000 595.836000 1866.240000 595.860000 ;
 END
 END rx_flit[324]
 PIN rx_flit[325]
 DIRECTION OUTPUT ;
 USE SIGNAL ;
 PORT
 LAYER M4 ;
 RECT 1865.760000 595.980000 1866.240000 596.004000 ;
 END
 END rx_flit[325]
 PIN rx_flit[326]
 DIRECTION OUTPUT ;
 USE SIGNAL ;
 PORT
 LAYER M4 ;
 RECT 1865.760000 596.124000 1866.240000 596.148000 ;
 END
 END rx_flit[326]
 PIN rx_flit[327]
 DIRECTION OUTPUT ;
 USE SIGNAL ;
 PORT
 LAYER M4 ;
 RECT 1865.760000 596.268000 1866.240000 596.292000 ;
 END
 END rx_flit[327]
 PIN rx_flit[328]
 DIRECTION OUTPUT ;
 USE SIGNAL ;
 PORT
 LAYER M4 ;
 RECT 1865.760000 596.412000 1866.240000 596.436000 ;
 END
 END rx_flit[328]
 PIN rx_flit[329]
 DIRECTION OUTPUT ;
 USE SIGNAL ;
 PORT
 LAYER M4 ;
 RECT 1865.760000 596.556000 1866.240000 596.580000 ;
 END
 END rx_flit[329]
 PIN rx_flit[330]
 DIRECTION OUTPUT ;
 USE SIGNAL ;
 PORT
 LAYER M4 ;
 RECT 1865.760000 596.700000 1866.240000 596.724000 ;
 END
 END rx_flit[330]
 PIN rx_flit[331]
 DIRECTION OUTPUT ;
 USE SIGNAL ;
 PORT
 LAYER M4 ;
 RECT 1865.760000 596.844000 1866.240000 596.868000 ;
 END
 END rx_flit[331]
 PIN rx_flit[332]
 DIRECTION OUTPUT ;
 USE SIGNAL ;
 PORT
 LAYER M4 ;
 RECT 1865.760000 596.988000 1866.240000 597.012000 ;
 END
 END rx_flit[332]
 PIN rx_flit[333]
 DIRECTION OUTPUT ;
 USE SIGNAL ;
 PORT
 LAYER M4 ;
 RECT 1865.760000 597.132000 1866.240000 597.156000 ;
 END
 END rx_flit[333]
 PIN rx_flit[334]
 DIRECTION OUTPUT ;
 USE SIGNAL ;
 PORT
 LAYER M4 ;
 RECT 1865.760000 597.276000 1866.240000 597.300000 ;
 END
 END rx_flit[334]
 PIN rx_flit[335]
 DIRECTION OUTPUT ;
 USE SIGNAL ;
 PORT
 LAYER M4 ;
 RECT 1865.760000 597.420000 1866.240000 597.444000 ;
 END
 END rx_flit[335]
 PIN rx_flit[336]
 DIRECTION OUTPUT ;
 USE SIGNAL ;
 PORT
 LAYER M4 ;
 RECT 1865.760000 597.564000 1866.240000 597.588000 ;
 END
 END rx_flit[336]
 PIN rx_flit[337]
 DIRECTION OUTPUT ;
 USE SIGNAL ;
 PORT
 LAYER M4 ;
 RECT 1865.760000 597.708000 1866.240000 597.732000 ;
 END
 END rx_flit[337]
 PIN rx_flit[338]
 DIRECTION OUTPUT ;
 USE SIGNAL ;
 PORT
 LAYER M4 ;
 RECT 1865.760000 597.852000 1866.240000 597.876000 ;
 END
 END rx_flit[338]
 PIN rx_flit[339]
 DIRECTION OUTPUT ;
 USE SIGNAL ;
 PORT
 LAYER M4 ;
 RECT 1865.760000 597.996000 1866.240000 598.020000 ;
 END
 END rx_flit[339]
 PIN rx_flit[340]
 DIRECTION OUTPUT ;
 USE SIGNAL ;
 PORT
 LAYER M4 ;
 RECT 1865.760000 598.140000 1866.240000 598.164000 ;
 END
 END rx_flit[340]
 PIN rx_flit[341]
 DIRECTION OUTPUT ;
 USE SIGNAL ;
 PORT
 LAYER M4 ;
 RECT 1865.760000 598.284000 1866.240000 598.308000 ;
 END
 END rx_flit[341]
 PIN rx_flit[342]
 DIRECTION OUTPUT ;
 USE SIGNAL ;
 PORT
 LAYER M4 ;
 RECT 1865.760000 598.428000 1866.240000 598.452000 ;
 END
 END rx_flit[342]
 PIN rx_flit[343]
 DIRECTION OUTPUT ;
 USE SIGNAL ;
 PORT
 LAYER M4 ;
 RECT 1865.760000 598.572000 1866.240000 598.596000 ;
 END
 END rx_flit[343]
 PIN rx_flit[344]
 DIRECTION OUTPUT ;
 USE SIGNAL ;
 PORT
 LAYER M4 ;
 RECT 1865.760000 598.716000 1866.240000 598.740000 ;
 END
 END rx_flit[344]
 PIN rx_flit[345]
 DIRECTION OUTPUT ;
 USE SIGNAL ;
 PORT
 LAYER M4 ;
 RECT 1865.760000 598.860000 1866.240000 598.884000 ;
 END
 END rx_flit[345]
 PIN rx_flit[346]
 DIRECTION OUTPUT ;
 USE SIGNAL ;
 PORT
 LAYER M4 ;
 RECT 1865.760000 599.004000 1866.240000 599.028000 ;
 END
 END rx_flit[346]
 PIN rx_flit[347]
 DIRECTION OUTPUT ;
 USE SIGNAL ;
 PORT
 LAYER M4 ;
 RECT 1865.760000 599.148000 1866.240000 599.172000 ;
 END
 END rx_flit[347]
 PIN rx_flit[348]
 DIRECTION OUTPUT ;
 USE SIGNAL ;
 PORT
 LAYER M4 ;
 RECT 1865.760000 599.292000 1866.240000 599.316000 ;
 END
 END rx_flit[348]
 PIN rx_flit[349]
 DIRECTION OUTPUT ;
 USE SIGNAL ;
 PORT
 LAYER M4 ;
 RECT 1865.760000 599.436000 1866.240000 599.460000 ;
 END
 END rx_flit[349]
 PIN rx_flit[350]
 DIRECTION OUTPUT ;
 USE SIGNAL ;
 PORT
 LAYER M4 ;
 RECT 1865.760000 599.580000 1866.240000 599.604000 ;
 END
 END rx_flit[350]
 PIN rx_flit[351]
 DIRECTION OUTPUT ;
 USE SIGNAL ;
 PORT
 LAYER M4 ;
 RECT 1865.760000 599.724000 1866.240000 599.748000 ;
 END
 END rx_flit[351]
 PIN rx_flit[352]
 DIRECTION OUTPUT ;
 USE SIGNAL ;
 PORT
 LAYER M4 ;
 RECT 1865.760000 599.868000 1866.240000 599.892000 ;
 END
 END rx_flit[352]
 PIN rx_flit[353]
 DIRECTION OUTPUT ;
 USE SIGNAL ;
 PORT
 LAYER M4 ;
 RECT 1865.760000 600.012000 1866.240000 600.036000 ;
 END
 END rx_flit[353]
 PIN rx_flit[354]
 DIRECTION OUTPUT ;
 USE SIGNAL ;
 PORT
 LAYER M4 ;
 RECT 1865.760000 600.156000 1866.240000 600.180000 ;
 END
 END rx_flit[354]
 PIN rx_flit[355]
 DIRECTION OUTPUT ;
 USE SIGNAL ;
 PORT
 LAYER M4 ;
 RECT 1865.760000 600.300000 1866.240000 600.324000 ;
 END
 END rx_flit[355]
 PIN rx_flit[356]
 DIRECTION OUTPUT ;
 USE SIGNAL ;
 PORT
 LAYER M4 ;
 RECT 1865.760000 600.444000 1866.240000 600.468000 ;
 END
 END rx_flit[356]
 PIN rx_flit[357]
 DIRECTION OUTPUT ;
 USE SIGNAL ;
 PORT
 LAYER M4 ;
 RECT 1865.760000 600.588000 1866.240000 600.612000 ;
 END
 END rx_flit[357]
 PIN rx_flit[358]
 DIRECTION OUTPUT ;
 USE SIGNAL ;
 PORT
 LAYER M4 ;
 RECT 1865.760000 600.732000 1866.240000 600.756000 ;
 END
 END rx_flit[358]
 PIN rx_flit[359]
 DIRECTION OUTPUT ;
 USE SIGNAL ;
 PORT
 LAYER M4 ;
 RECT 1865.760000 600.876000 1866.240000 600.900000 ;
 END
 END rx_flit[359]
 PIN rx_flit[360]
 DIRECTION OUTPUT ;
 USE SIGNAL ;
 PORT
 LAYER M4 ;
 RECT 1865.760000 601.020000 1866.240000 601.044000 ;
 END
 END rx_flit[360]
 PIN rx_flit[361]
 DIRECTION OUTPUT ;
 USE SIGNAL ;
 PORT
 LAYER M4 ;
 RECT 1865.760000 601.164000 1866.240000 601.188000 ;
 END
 END rx_flit[361]
 PIN rx_flit[362]
 DIRECTION OUTPUT ;
 USE SIGNAL ;
 PORT
 LAYER M4 ;
 RECT 1865.760000 601.308000 1866.240000 601.332000 ;
 END
 END rx_flit[362]
 PIN rx_flit[363]
 DIRECTION OUTPUT ;
 USE SIGNAL ;
 PORT
 LAYER M4 ;
 RECT 1865.760000 601.452000 1866.240000 601.476000 ;
 END
 END rx_flit[363]
 PIN rx_flit[364]
 DIRECTION OUTPUT ;
 USE SIGNAL ;
 PORT
 LAYER M4 ;
 RECT 1865.760000 601.596000 1866.240000 601.620000 ;
 END
 END rx_flit[364]
 PIN rx_flit[365]
 DIRECTION OUTPUT ;
 USE SIGNAL ;
 PORT
 LAYER M4 ;
 RECT 1865.760000 601.740000 1866.240000 601.764000 ;
 END
 END rx_flit[365]
 PIN rx_flit[366]
 DIRECTION OUTPUT ;
 USE SIGNAL ;
 PORT
 LAYER M4 ;
 RECT 1865.760000 601.884000 1866.240000 601.908000 ;
 END
 END rx_flit[366]
 PIN rx_flit[367]
 DIRECTION OUTPUT ;
 USE SIGNAL ;
 PORT
 LAYER M4 ;
 RECT 1865.760000 602.028000 1866.240000 602.052000 ;
 END
 END rx_flit[367]
 PIN rx_flit[368]
 DIRECTION OUTPUT ;
 USE SIGNAL ;
 PORT
 LAYER M4 ;
 RECT 1865.760000 602.172000 1866.240000 602.196000 ;
 END
 END rx_flit[368]
 PIN rx_flit[369]
 DIRECTION OUTPUT ;
 USE SIGNAL ;
 PORT
 LAYER M4 ;
 RECT 1865.760000 602.316000 1866.240000 602.340000 ;
 END
 END rx_flit[369]
 PIN rx_flit[370]
 DIRECTION OUTPUT ;
 USE SIGNAL ;
 PORT
 LAYER M4 ;
 RECT 1865.760000 602.460000 1866.240000 602.484000 ;
 END
 END rx_flit[370]
 PIN rx_flit[371]
 DIRECTION OUTPUT ;
 USE SIGNAL ;
 PORT
 LAYER M4 ;
 RECT 1865.760000 602.604000 1866.240000 602.628000 ;
 END
 END rx_flit[371]
 PIN rx_flit[372]
 DIRECTION OUTPUT ;
 USE SIGNAL ;
 PORT
 LAYER M4 ;
 RECT 1865.760000 602.748000 1866.240000 602.772000 ;
 END
 END rx_flit[372]
 PIN rx_flit[373]
 DIRECTION OUTPUT ;
 USE SIGNAL ;
 PORT
 LAYER M4 ;
 RECT 1865.760000 602.892000 1866.240000 602.916000 ;
 END
 END rx_flit[373]
 PIN rx_flit[374]
 DIRECTION OUTPUT ;
 USE SIGNAL ;
 PORT
 LAYER M4 ;
 RECT 1865.760000 603.036000 1866.240000 603.060000 ;
 END
 END rx_flit[374]
 PIN rx_flit[375]
 DIRECTION OUTPUT ;
 USE SIGNAL ;
 PORT
 LAYER M4 ;
 RECT 1865.760000 603.180000 1866.240000 603.204000 ;
 END
 END rx_flit[375]
 PIN rx_flit[376]
 DIRECTION OUTPUT ;
 USE SIGNAL ;
 PORT
 LAYER M4 ;
 RECT 1865.760000 603.324000 1866.240000 603.348000 ;
 END
 END rx_flit[376]
 PIN rx_flit[377]
 DIRECTION OUTPUT ;
 USE SIGNAL ;
 PORT
 LAYER M4 ;
 RECT 1865.760000 603.468000 1866.240000 603.492000 ;
 END
 END rx_flit[377]
 PIN rx_flit[378]
 DIRECTION OUTPUT ;
 USE SIGNAL ;
 PORT
 LAYER M4 ;
 RECT 1865.760000 603.612000 1866.240000 603.636000 ;
 END
 END rx_flit[378]
 PIN rx_flit[379]
 DIRECTION OUTPUT ;
 USE SIGNAL ;
 PORT
 LAYER M4 ;
 RECT 1865.760000 603.756000 1866.240000 603.780000 ;
 END
 END rx_flit[379]
 PIN rx_flit[380]
 DIRECTION OUTPUT ;
 USE SIGNAL ;
 PORT
 LAYER M4 ;
 RECT 1865.760000 603.900000 1866.240000 603.924000 ;
 END
 END rx_flit[380]
 PIN rx_flit[381]
 DIRECTION OUTPUT ;
 USE SIGNAL ;
 PORT
 LAYER M4 ;
 RECT 1865.760000 604.044000 1866.240000 604.068000 ;
 END
 END rx_flit[381]
 PIN rx_flit[382]
 DIRECTION OUTPUT ;
 USE SIGNAL ;
 PORT
 LAYER M4 ;
 RECT 1865.760000 604.188000 1866.240000 604.212000 ;
 END
 END rx_flit[382]
 PIN rx_flit[383]
 DIRECTION OUTPUT ;
 USE SIGNAL ;
 PORT
 LAYER M4 ;
 RECT 1865.760000 604.332000 1866.240000 604.356000 ;
 END
 END rx_flit[383]
 PIN rx_flit[384]
 DIRECTION OUTPUT ;
 USE SIGNAL ;
 PORT
 LAYER M4 ;
 RECT 1865.760000 604.476000 1866.240000 604.500000 ;
 END
 END rx_flit[384]
 PIN rx_flit[385]
 DIRECTION OUTPUT ;
 USE SIGNAL ;
 PORT
 LAYER M4 ;
 RECT 1865.760000 604.620000 1866.240000 604.644000 ;
 END
 END rx_flit[385]
 PIN rx_flit[386]
 DIRECTION OUTPUT ;
 USE SIGNAL ;
 PORT
 LAYER M4 ;
 RECT 1865.760000 604.764000 1866.240000 604.788000 ;
 END
 END rx_flit[386]
 PIN rx_flit[387]
 DIRECTION OUTPUT ;
 USE SIGNAL ;
 PORT
 LAYER M4 ;
 RECT 1865.760000 604.908000 1866.240000 604.932000 ;
 END
 END rx_flit[387]
 PIN rx_flit[388]
 DIRECTION OUTPUT ;
 USE SIGNAL ;
 PORT
 LAYER M4 ;
 RECT 1865.760000 605.052000 1866.240000 605.076000 ;
 END
 END rx_flit[388]
 PIN rx_flit[389]
 DIRECTION OUTPUT ;
 USE SIGNAL ;
 PORT
 LAYER M4 ;
 RECT 1865.760000 605.196000 1866.240000 605.220000 ;
 END
 END rx_flit[389]
 PIN rx_flit[390]
 DIRECTION OUTPUT ;
 USE SIGNAL ;
 PORT
 LAYER M4 ;
 RECT 1865.760000 605.340000 1866.240000 605.364000 ;
 END
 END rx_flit[390]
 PIN rx_flit[391]
 DIRECTION OUTPUT ;
 USE SIGNAL ;
 PORT
 LAYER M4 ;
 RECT 1865.760000 605.484000 1866.240000 605.508000 ;
 END
 END rx_flit[391]
 PIN rx_flit[392]
 DIRECTION OUTPUT ;
 USE SIGNAL ;
 PORT
 LAYER M4 ;
 RECT 1865.760000 605.628000 1866.240000 605.652000 ;
 END
 END rx_flit[392]
 PIN rx_flit[393]
 DIRECTION OUTPUT ;
 USE SIGNAL ;
 PORT
 LAYER M4 ;
 RECT 1865.760000 605.772000 1866.240000 605.796000 ;
 END
 END rx_flit[393]
 PIN rx_flit[394]
 DIRECTION OUTPUT ;
 USE SIGNAL ;
 PORT
 LAYER M4 ;
 RECT 1865.760000 605.916000 1866.240000 605.940000 ;
 END
 END rx_flit[394]
 PIN rx_flit[395]
 DIRECTION OUTPUT ;
 USE SIGNAL ;
 PORT
 LAYER M4 ;
 RECT 1865.760000 606.060000 1866.240000 606.084000 ;
 END
 END rx_flit[395]
 PIN rx_flit[396]
 DIRECTION OUTPUT ;
 USE SIGNAL ;
 PORT
 LAYER M4 ;
 RECT 1865.760000 606.204000 1866.240000 606.228000 ;
 END
 END rx_flit[396]
 PIN rx_flit[397]
 DIRECTION OUTPUT ;
 USE SIGNAL ;
 PORT
 LAYER M4 ;
 RECT 1865.760000 606.348000 1866.240000 606.372000 ;
 END
 END rx_flit[397]
 PIN rx_flit[398]
 DIRECTION OUTPUT ;
 USE SIGNAL ;
 PORT
 LAYER M4 ;
 RECT 1865.760000 606.492000 1866.240000 606.516000 ;
 END
 END rx_flit[398]
 PIN rx_flit[399]
 DIRECTION OUTPUT ;
 USE SIGNAL ;
 PORT
 LAYER M4 ;
 RECT 1865.760000 606.636000 1866.240000 606.660000 ;
 END
 END rx_flit[399]
 PIN rx_flit[400]
 DIRECTION OUTPUT ;
 USE SIGNAL ;
 PORT
 LAYER M4 ;
 RECT 1865.760000 606.780000 1866.240000 606.804000 ;
 END
 END rx_flit[400]
 PIN rx_flit[401]
 DIRECTION OUTPUT ;
 USE SIGNAL ;
 PORT
 LAYER M4 ;
 RECT 1865.760000 606.924000 1866.240000 606.948000 ;
 END
 END rx_flit[401]
 PIN rx_flit[402]
 DIRECTION OUTPUT ;
 USE SIGNAL ;
 PORT
 LAYER M4 ;
 RECT 1865.760000 607.068000 1866.240000 607.092000 ;
 END
 END rx_flit[402]
 PIN rx_flit[403]
 DIRECTION OUTPUT ;
 USE SIGNAL ;
 PORT
 LAYER M4 ;
 RECT 1865.760000 607.212000 1866.240000 607.236000 ;
 END
 END rx_flit[403]
 PIN rx_flit[404]
 DIRECTION OUTPUT ;
 USE SIGNAL ;
 PORT
 LAYER M4 ;
 RECT 1865.760000 607.356000 1866.240000 607.380000 ;
 END
 END rx_flit[404]
 PIN rx_flit[405]
 DIRECTION OUTPUT ;
 USE SIGNAL ;
 PORT
 LAYER M4 ;
 RECT 1865.760000 607.500000 1866.240000 607.524000 ;
 END
 END rx_flit[405]
 PIN rx_flit[406]
 DIRECTION OUTPUT ;
 USE SIGNAL ;
 PORT
 LAYER M4 ;
 RECT 1865.760000 607.644000 1866.240000 607.668000 ;
 END
 END rx_flit[406]
 PIN rx_flit[407]
 DIRECTION OUTPUT ;
 USE SIGNAL ;
 PORT
 LAYER M4 ;
 RECT 1865.760000 607.788000 1866.240000 607.812000 ;
 END
 END rx_flit[407]
 PIN rx_flit[408]
 DIRECTION OUTPUT ;
 USE SIGNAL ;
 PORT
 LAYER M4 ;
 RECT 1865.760000 607.932000 1866.240000 607.956000 ;
 END
 END rx_flit[408]
 PIN rx_flit[409]
 DIRECTION OUTPUT ;
 USE SIGNAL ;
 PORT
 LAYER M4 ;
 RECT 1865.760000 608.076000 1866.240000 608.100000 ;
 END
 END rx_flit[409]
 PIN rx_flit[410]
 DIRECTION OUTPUT ;
 USE SIGNAL ;
 PORT
 LAYER M4 ;
 RECT 1865.760000 608.220000 1866.240000 608.244000 ;
 END
 END rx_flit[410]
 PIN rx_flit[411]
 DIRECTION OUTPUT ;
 USE SIGNAL ;
 PORT
 LAYER M4 ;
 RECT 1865.760000 608.364000 1866.240000 608.388000 ;
 END
 END rx_flit[411]
 PIN rx_flit[412]
 DIRECTION OUTPUT ;
 USE SIGNAL ;
 PORT
 LAYER M4 ;
 RECT 1865.760000 608.508000 1866.240000 608.532000 ;
 END
 END rx_flit[412]
 PIN rx_flit[413]
 DIRECTION OUTPUT ;
 USE SIGNAL ;
 PORT
 LAYER M4 ;
 RECT 1865.760000 608.652000 1866.240000 608.676000 ;
 END
 END rx_flit[413]
 PIN rx_flit[414]
 DIRECTION OUTPUT ;
 USE SIGNAL ;
 PORT
 LAYER M4 ;
 RECT 1865.760000 608.796000 1866.240000 608.820000 ;
 END
 END rx_flit[414]
 PIN rx_flit[415]
 DIRECTION OUTPUT ;
 USE SIGNAL ;
 PORT
 LAYER M4 ;
 RECT 1865.760000 608.940000 1866.240000 608.964000 ;
 END
 END rx_flit[415]
 PIN rx_flit[416]
 DIRECTION OUTPUT ;
 USE SIGNAL ;
 PORT
 LAYER M4 ;
 RECT 1865.760000 609.084000 1866.240000 609.108000 ;
 END
 END rx_flit[416]
 PIN rx_flit[417]
 DIRECTION OUTPUT ;
 USE SIGNAL ;
 PORT
 LAYER M4 ;
 RECT 1865.760000 609.228000 1866.240000 609.252000 ;
 END
 END rx_flit[417]
 PIN rx_flit[418]
 DIRECTION OUTPUT ;
 USE SIGNAL ;
 PORT
 LAYER M4 ;
 RECT 1865.760000 609.372000 1866.240000 609.396000 ;
 END
 END rx_flit[418]
 PIN rx_flit[419]
 DIRECTION OUTPUT ;
 USE SIGNAL ;
 PORT
 LAYER M4 ;
 RECT 1865.760000 609.516000 1866.240000 609.540000 ;
 END
 END rx_flit[419]
 PIN rx_flit[420]
 DIRECTION OUTPUT ;
 USE SIGNAL ;
 PORT
 LAYER M4 ;
 RECT 1865.760000 609.660000 1866.240000 609.684000 ;
 END
 END rx_flit[420]
 PIN rx_flit[421]
 DIRECTION OUTPUT ;
 USE SIGNAL ;
 PORT
 LAYER M4 ;
 RECT 1865.760000 609.804000 1866.240000 609.828000 ;
 END
 END rx_flit[421]
 PIN rx_flit[422]
 DIRECTION OUTPUT ;
 USE SIGNAL ;
 PORT
 LAYER M4 ;
 RECT 1865.760000 609.948000 1866.240000 609.972000 ;
 END
 END rx_flit[422]
 PIN rx_flit[423]
 DIRECTION OUTPUT ;
 USE SIGNAL ;
 PORT
 LAYER M4 ;
 RECT 1865.760000 610.092000 1866.240000 610.116000 ;
 END
 END rx_flit[423]
 PIN rx_flit[424]
 DIRECTION OUTPUT ;
 USE SIGNAL ;
 PORT
 LAYER M4 ;
 RECT 1865.760000 610.236000 1866.240000 610.260000 ;
 END
 END rx_flit[424]
 PIN rx_flit[425]
 DIRECTION OUTPUT ;
 USE SIGNAL ;
 PORT
 LAYER M4 ;
 RECT 1865.760000 610.380000 1866.240000 610.404000 ;
 END
 END rx_flit[425]
 PIN rx_flit[426]
 DIRECTION OUTPUT ;
 USE SIGNAL ;
 PORT
 LAYER M4 ;
 RECT 1865.760000 610.524000 1866.240000 610.548000 ;
 END
 END rx_flit[426]
 PIN rx_flit[427]
 DIRECTION OUTPUT ;
 USE SIGNAL ;
 PORT
 LAYER M4 ;
 RECT 1865.760000 610.668000 1866.240000 610.692000 ;
 END
 END rx_flit[427]
 PIN rx_flit[428]
 DIRECTION OUTPUT ;
 USE SIGNAL ;
 PORT
 LAYER M4 ;
 RECT 1865.760000 610.812000 1866.240000 610.836000 ;
 END
 END rx_flit[428]
 PIN rx_flit[429]
 DIRECTION OUTPUT ;
 USE SIGNAL ;
 PORT
 LAYER M4 ;
 RECT 1865.760000 610.956000 1866.240000 610.980000 ;
 END
 END rx_flit[429]
 PIN rx_flit[430]
 DIRECTION OUTPUT ;
 USE SIGNAL ;
 PORT
 LAYER M4 ;
 RECT 1865.760000 611.100000 1866.240000 611.124000 ;
 END
 END rx_flit[430]
 PIN rx_flit[431]
 DIRECTION OUTPUT ;
 USE SIGNAL ;
 PORT
 LAYER M4 ;
 RECT 1865.760000 611.244000 1866.240000 611.268000 ;
 END
 END rx_flit[431]
 PIN rx_flit[432]
 DIRECTION OUTPUT ;
 USE SIGNAL ;
 PORT
 LAYER M4 ;
 RECT 1865.760000 611.388000 1866.240000 611.412000 ;
 END
 END rx_flit[432]
 PIN rx_flit[433]
 DIRECTION OUTPUT ;
 USE SIGNAL ;
 PORT
 LAYER M4 ;
 RECT 1865.760000 611.532000 1866.240000 611.556000 ;
 END
 END rx_flit[433]
 PIN rx_flit[434]
 DIRECTION OUTPUT ;
 USE SIGNAL ;
 PORT
 LAYER M4 ;
 RECT 1865.760000 611.676000 1866.240000 611.700000 ;
 END
 END rx_flit[434]
 PIN rx_flit[435]
 DIRECTION OUTPUT ;
 USE SIGNAL ;
 PORT
 LAYER M4 ;
 RECT 1865.760000 611.820000 1866.240000 611.844000 ;
 END
 END rx_flit[435]
 PIN rx_flit[436]
 DIRECTION OUTPUT ;
 USE SIGNAL ;
 PORT
 LAYER M4 ;
 RECT 1865.760000 611.964000 1866.240000 611.988000 ;
 END
 END rx_flit[436]
 PIN rx_flit[437]
 DIRECTION OUTPUT ;
 USE SIGNAL ;
 PORT
 LAYER M4 ;
 RECT 1865.760000 612.108000 1866.240000 612.132000 ;
 END
 END rx_flit[437]
 PIN rx_flit[438]
 DIRECTION OUTPUT ;
 USE SIGNAL ;
 PORT
 LAYER M4 ;
 RECT 1865.760000 612.252000 1866.240000 612.276000 ;
 END
 END rx_flit[438]
 PIN rx_flit[439]
 DIRECTION OUTPUT ;
 USE SIGNAL ;
 PORT
 LAYER M4 ;
 RECT 1865.760000 612.396000 1866.240000 612.420000 ;
 END
 END rx_flit[439]
 PIN rx_flit[440]
 DIRECTION OUTPUT ;
 USE SIGNAL ;
 PORT
 LAYER M4 ;
 RECT 1865.760000 612.540000 1866.240000 612.564000 ;
 END
 END rx_flit[440]
 PIN rx_flit[441]
 DIRECTION OUTPUT ;
 USE SIGNAL ;
 PORT
 LAYER M4 ;
 RECT 1865.760000 612.684000 1866.240000 612.708000 ;
 END
 END rx_flit[441]
 PIN rx_flit[442]
 DIRECTION OUTPUT ;
 USE SIGNAL ;
 PORT
 LAYER M4 ;
 RECT 1865.760000 612.828000 1866.240000 612.852000 ;
 END
 END rx_flit[442]
 PIN rx_flit[443]
 DIRECTION OUTPUT ;
 USE SIGNAL ;
 PORT
 LAYER M4 ;
 RECT 1865.760000 612.972000 1866.240000 612.996000 ;
 END
 END rx_flit[443]
 PIN rx_flit[444]
 DIRECTION OUTPUT ;
 USE SIGNAL ;
 PORT
 LAYER M4 ;
 RECT 1865.760000 613.116000 1866.240000 613.140000 ;
 END
 END rx_flit[444]
 PIN rx_flit[445]
 DIRECTION OUTPUT ;
 USE SIGNAL ;
 PORT
 LAYER M4 ;
 RECT 1865.760000 613.260000 1866.240000 613.284000 ;
 END
 END rx_flit[445]
 PIN rx_flit[446]
 DIRECTION OUTPUT ;
 USE SIGNAL ;
 PORT
 LAYER M4 ;
 RECT 1865.760000 613.404000 1866.240000 613.428000 ;
 END
 END rx_flit[446]
 PIN rx_flit[447]
 DIRECTION OUTPUT ;
 USE SIGNAL ;
 PORT
 LAYER M4 ;
 RECT 1865.760000 613.548000 1866.240000 613.572000 ;
 END
 END rx_flit[447]
 PIN rx_flit[448]
 DIRECTION OUTPUT ;
 USE SIGNAL ;
 PORT
 LAYER M4 ;
 RECT 1865.760000 613.692000 1866.240000 613.716000 ;
 END
 END rx_flit[448]
 PIN rx_flit[449]
 DIRECTION OUTPUT ;
 USE SIGNAL ;
 PORT
 LAYER M4 ;
 RECT 1865.760000 613.836000 1866.240000 613.860000 ;
 END
 END rx_flit[449]
 PIN rx_flit[450]
 DIRECTION OUTPUT ;
 USE SIGNAL ;
 PORT
 LAYER M4 ;
 RECT 1865.760000 613.980000 1866.240000 614.004000 ;
 END
 END rx_flit[450]
 PIN rx_flit[451]
 DIRECTION OUTPUT ;
 USE SIGNAL ;
 PORT
 LAYER M4 ;
 RECT 1865.760000 614.124000 1866.240000 614.148000 ;
 END
 END rx_flit[451]
 PIN rx_flit[452]
 DIRECTION OUTPUT ;
 USE SIGNAL ;
 PORT
 LAYER M4 ;
 RECT 1865.760000 614.268000 1866.240000 614.292000 ;
 END
 END rx_flit[452]
 PIN rx_flit[453]
 DIRECTION OUTPUT ;
 USE SIGNAL ;
 PORT
 LAYER M4 ;
 RECT 1865.760000 614.412000 1866.240000 614.436000 ;
 END
 END rx_flit[453]
 PIN rx_flit[454]
 DIRECTION OUTPUT ;
 USE SIGNAL ;
 PORT
 LAYER M4 ;
 RECT 1865.760000 614.556000 1866.240000 614.580000 ;
 END
 END rx_flit[454]
 PIN rx_flit[455]
 DIRECTION OUTPUT ;
 USE SIGNAL ;
 PORT
 LAYER M4 ;
 RECT 1865.760000 614.700000 1866.240000 614.724000 ;
 END
 END rx_flit[455]
 PIN rx_flit[456]
 DIRECTION OUTPUT ;
 USE SIGNAL ;
 PORT
 LAYER M4 ;
 RECT 1865.760000 614.844000 1866.240000 614.868000 ;
 END
 END rx_flit[456]
 PIN rx_flit[457]
 DIRECTION OUTPUT ;
 USE SIGNAL ;
 PORT
 LAYER M4 ;
 RECT 1865.760000 614.988000 1866.240000 615.012000 ;
 END
 END rx_flit[457]
 PIN rx_flit[458]
 DIRECTION OUTPUT ;
 USE SIGNAL ;
 PORT
 LAYER M4 ;
 RECT 1865.760000 615.132000 1866.240000 615.156000 ;
 END
 END rx_flit[458]
 PIN rx_flit[459]
 DIRECTION OUTPUT ;
 USE SIGNAL ;
 PORT
 LAYER M4 ;
 RECT 1865.760000 615.276000 1866.240000 615.300000 ;
 END
 END rx_flit[459]
 PIN rx_flit[460]
 DIRECTION OUTPUT ;
 USE SIGNAL ;
 PORT
 LAYER M4 ;
 RECT 1865.760000 615.420000 1866.240000 615.444000 ;
 END
 END rx_flit[460]
 PIN rx_flit[461]
 DIRECTION OUTPUT ;
 USE SIGNAL ;
 PORT
 LAYER M4 ;
 RECT 1865.760000 615.564000 1866.240000 615.588000 ;
 END
 END rx_flit[461]
 PIN rx_flit[462]
 DIRECTION OUTPUT ;
 USE SIGNAL ;
 PORT
 LAYER M4 ;
 RECT 1865.760000 615.708000 1866.240000 615.732000 ;
 END
 END rx_flit[462]
 PIN rx_flit[463]
 DIRECTION OUTPUT ;
 USE SIGNAL ;
 PORT
 LAYER M4 ;
 RECT 1865.760000 615.852000 1866.240000 615.876000 ;
 END
 END rx_flit[463]
 PIN rx_flit[464]
 DIRECTION OUTPUT ;
 USE SIGNAL ;
 PORT
 LAYER M4 ;
 RECT 1865.760000 615.996000 1866.240000 616.020000 ;
 END
 END rx_flit[464]
 PIN rx_flit[465]
 DIRECTION OUTPUT ;
 USE SIGNAL ;
 PORT
 LAYER M4 ;
 RECT 1865.760000 616.140000 1866.240000 616.164000 ;
 END
 END rx_flit[465]
 PIN rx_flit[466]
 DIRECTION OUTPUT ;
 USE SIGNAL ;
 PORT
 LAYER M4 ;
 RECT 1865.760000 616.284000 1866.240000 616.308000 ;
 END
 END rx_flit[466]
 PIN rx_flit[467]
 DIRECTION OUTPUT ;
 USE SIGNAL ;
 PORT
 LAYER M4 ;
 RECT 1865.760000 616.428000 1866.240000 616.452000 ;
 END
 END rx_flit[467]
 PIN rx_flit[468]
 DIRECTION OUTPUT ;
 USE SIGNAL ;
 PORT
 LAYER M4 ;
 RECT 1865.760000 616.572000 1866.240000 616.596000 ;
 END
 END rx_flit[468]
 PIN rx_flit[469]
 DIRECTION OUTPUT ;
 USE SIGNAL ;
 PORT
 LAYER M4 ;
 RECT 1865.760000 616.716000 1866.240000 616.740000 ;
 END
 END rx_flit[469]
 PIN rx_flit[470]
 DIRECTION OUTPUT ;
 USE SIGNAL ;
 PORT
 LAYER M4 ;
 RECT 1865.760000 616.860000 1866.240000 616.884000 ;
 END
 END rx_flit[470]
 PIN rx_flit[471]
 DIRECTION OUTPUT ;
 USE SIGNAL ;
 PORT
 LAYER M4 ;
 RECT 1865.760000 617.004000 1866.240000 617.028000 ;
 END
 END rx_flit[471]
 PIN rx_flit[472]
 DIRECTION OUTPUT ;
 USE SIGNAL ;
 PORT
 LAYER M4 ;
 RECT 1865.760000 617.148000 1866.240000 617.172000 ;
 END
 END rx_flit[472]
 PIN rx_flit[473]
 DIRECTION OUTPUT ;
 USE SIGNAL ;
 PORT
 LAYER M4 ;
 RECT 1865.760000 617.292000 1866.240000 617.316000 ;
 END
 END rx_flit[473]
 PIN rx_flit[474]
 DIRECTION OUTPUT ;
 USE SIGNAL ;
 PORT
 LAYER M4 ;
 RECT 1865.760000 617.436000 1866.240000 617.460000 ;
 END
 END rx_flit[474]
 PIN rx_flit[475]
 DIRECTION OUTPUT ;
 USE SIGNAL ;
 PORT
 LAYER M4 ;
 RECT 1865.760000 617.580000 1866.240000 617.604000 ;
 END
 END rx_flit[475]
 PIN rx_flit[476]
 DIRECTION OUTPUT ;
 USE SIGNAL ;
 PORT
 LAYER M4 ;
 RECT 1865.760000 617.724000 1866.240000 617.748000 ;
 END
 END rx_flit[476]
 PIN rx_flit[477]
 DIRECTION OUTPUT ;
 USE SIGNAL ;
 PORT
 LAYER M4 ;
 RECT 1865.760000 617.868000 1866.240000 617.892000 ;
 END
 END rx_flit[477]
 PIN rx_flit[478]
 DIRECTION OUTPUT ;
 USE SIGNAL ;
 PORT
 LAYER M4 ;
 RECT 1865.760000 618.012000 1866.240000 618.036000 ;
 END
 END rx_flit[478]
 PIN rx_flit[479]
 DIRECTION OUTPUT ;
 USE SIGNAL ;
 PORT
 LAYER M4 ;
 RECT 1865.760000 618.156000 1866.240000 618.180000 ;
 END
 END rx_flit[479]
 PIN rx_flit[480]
 DIRECTION OUTPUT ;
 USE SIGNAL ;
 PORT
 LAYER M4 ;
 RECT 1865.760000 618.300000 1866.240000 618.324000 ;
 END
 END rx_flit[480]
 PIN rx_flit[481]
 DIRECTION OUTPUT ;
 USE SIGNAL ;
 PORT
 LAYER M4 ;
 RECT 1865.760000 618.444000 1866.240000 618.468000 ;
 END
 END rx_flit[481]
 PIN rx_flit[482]
 DIRECTION OUTPUT ;
 USE SIGNAL ;
 PORT
 LAYER M4 ;
 RECT 1865.760000 618.588000 1866.240000 618.612000 ;
 END
 END rx_flit[482]
 PIN rx_flit[483]
 DIRECTION OUTPUT ;
 USE SIGNAL ;
 PORT
 LAYER M4 ;
 RECT 1865.760000 618.732000 1866.240000 618.756000 ;
 END
 END rx_flit[483]
 PIN rx_flit[484]
 DIRECTION OUTPUT ;
 USE SIGNAL ;
 PORT
 LAYER M4 ;
 RECT 1865.760000 618.876000 1866.240000 618.900000 ;
 END
 END rx_flit[484]
 PIN rx_flit[485]
 DIRECTION OUTPUT ;
 USE SIGNAL ;
 PORT
 LAYER M4 ;
 RECT 1865.760000 619.020000 1866.240000 619.044000 ;
 END
 END rx_flit[485]
 PIN rx_flit[486]
 DIRECTION OUTPUT ;
 USE SIGNAL ;
 PORT
 LAYER M4 ;
 RECT 1865.760000 619.164000 1866.240000 619.188000 ;
 END
 END rx_flit[486]
 PIN rx_flit[487]
 DIRECTION OUTPUT ;
 USE SIGNAL ;
 PORT
 LAYER M4 ;
 RECT 1865.760000 619.308000 1866.240000 619.332000 ;
 END
 END rx_flit[487]
 PIN rx_flit[488]
 DIRECTION OUTPUT ;
 USE SIGNAL ;
 PORT
 LAYER M4 ;
 RECT 1865.760000 619.452000 1866.240000 619.476000 ;
 END
 END rx_flit[488]
 PIN rx_flit[489]
 DIRECTION OUTPUT ;
 USE SIGNAL ;
 PORT
 LAYER M4 ;
 RECT 1865.760000 619.596000 1866.240000 619.620000 ;
 END
 END rx_flit[489]
 PIN rx_flit[490]
 DIRECTION OUTPUT ;
 USE SIGNAL ;
 PORT
 LAYER M4 ;
 RECT 1865.760000 619.740000 1866.240000 619.764000 ;
 END
 END rx_flit[490]
 PIN rx_flit[491]
 DIRECTION OUTPUT ;
 USE SIGNAL ;
 PORT
 LAYER M4 ;
 RECT 1865.760000 619.884000 1866.240000 619.908000 ;
 END
 END rx_flit[491]
 PIN rx_flit[492]
 DIRECTION OUTPUT ;
 USE SIGNAL ;
 PORT
 LAYER M4 ;
 RECT 1865.760000 620.028000 1866.240000 620.052000 ;
 END
 END rx_flit[492]
 PIN rx_flit[493]
 DIRECTION OUTPUT ;
 USE SIGNAL ;
 PORT
 LAYER M4 ;
 RECT 1865.760000 620.172000 1866.240000 620.196000 ;
 END
 END rx_flit[493]
 PIN rx_flit[494]
 DIRECTION OUTPUT ;
 USE SIGNAL ;
 PORT
 LAYER M4 ;
 RECT 1865.760000 620.316000 1866.240000 620.340000 ;
 END
 END rx_flit[494]
 PIN rx_flit[495]
 DIRECTION OUTPUT ;
 USE SIGNAL ;
 PORT
 LAYER M4 ;
 RECT 1865.760000 620.460000 1866.240000 620.484000 ;
 END
 END rx_flit[495]
 PIN rx_flit[496]
 DIRECTION OUTPUT ;
 USE SIGNAL ;
 PORT
 LAYER M4 ;
 RECT 1865.760000 620.604000 1866.240000 620.628000 ;
 END
 END rx_flit[496]
 PIN rx_flit[497]
 DIRECTION OUTPUT ;
 USE SIGNAL ;
 PORT
 LAYER M4 ;
 RECT 1865.760000 620.748000 1866.240000 620.772000 ;
 END
 END rx_flit[497]
 PIN rx_flit[498]
 DIRECTION OUTPUT ;
 USE SIGNAL ;
 PORT
 LAYER M4 ;
 RECT 1865.760000 620.892000 1866.240000 620.916000 ;
 END
 END rx_flit[498]
 PIN rx_flit[499]
 DIRECTION OUTPUT ;
 USE SIGNAL ;
 PORT
 LAYER M4 ;
 RECT 1865.760000 621.036000 1866.240000 621.060000 ;
 END
 END rx_flit[499]
 PIN rx_flit[500]
 DIRECTION OUTPUT ;
 USE SIGNAL ;
 PORT
 LAYER M4 ;
 RECT 1865.760000 621.180000 1866.240000 621.204000 ;
 END
 END rx_flit[500]
 PIN rx_flit[501]
 DIRECTION OUTPUT ;
 USE SIGNAL ;
 PORT
 LAYER M4 ;
 RECT 1865.760000 621.324000 1866.240000 621.348000 ;
 END
 END rx_flit[501]
 PIN rx_flit[502]
 DIRECTION OUTPUT ;
 USE SIGNAL ;
 PORT
 LAYER M4 ;
 RECT 1865.760000 621.468000 1866.240000 621.492000 ;
 END
 END rx_flit[502]
 PIN rx_flit[503]
 DIRECTION OUTPUT ;
 USE SIGNAL ;
 PORT
 LAYER M4 ;
 RECT 1865.760000 621.612000 1866.240000 621.636000 ;
 END
 END rx_flit[503]
 PIN rx_flit[504]
 DIRECTION OUTPUT ;
 USE SIGNAL ;
 PORT
 LAYER M4 ;
 RECT 1865.760000 621.756000 1866.240000 621.780000 ;
 END
 END rx_flit[504]
 PIN rx_flit[505]
 DIRECTION OUTPUT ;
 USE SIGNAL ;
 PORT
 LAYER M4 ;
 RECT 1865.760000 621.900000 1866.240000 621.924000 ;
 END
 END rx_flit[505]
 PIN rx_flit[506]
 DIRECTION OUTPUT ;
 USE SIGNAL ;
 PORT
 LAYER M4 ;
 RECT 1865.760000 622.044000 1866.240000 622.068000 ;
 END
 END rx_flit[506]
 PIN rx_flit[507]
 DIRECTION OUTPUT ;
 USE SIGNAL ;
 PORT
 LAYER M4 ;
 RECT 1865.760000 622.188000 1866.240000 622.212000 ;
 END
 END rx_flit[507]
 PIN rx_flit[508]
 DIRECTION OUTPUT ;
 USE SIGNAL ;
 PORT
 LAYER M4 ;
 RECT 1865.760000 622.332000 1866.240000 622.356000 ;
 END
 END rx_flit[508]
 PIN rx_flit[509]
 DIRECTION OUTPUT ;
 USE SIGNAL ;
 PORT
 LAYER M4 ;
 RECT 1865.760000 622.476000 1866.240000 622.500000 ;
 END
 END rx_flit[509]
 PIN rx_flit[510]
 DIRECTION OUTPUT ;
 USE SIGNAL ;
 PORT
 LAYER M4 ;
 RECT 1865.760000 622.620000 1866.240000 622.644000 ;
 END
 END rx_flit[510]
 PIN rx_flit[511]
 DIRECTION OUTPUT ;
 USE SIGNAL ;
 PORT
 LAYER M4 ;
 RECT 1865.760000 622.764000 1866.240000 622.788000 ;
 END
 END rx_flit[511]
 PIN rx_flit[512]
 DIRECTION OUTPUT ;
 USE SIGNAL ;
 PORT
 LAYER M4 ;
 RECT 1865.760000 622.908000 1866.240000 622.932000 ;
 END
 END rx_flit[512]
 PIN rx_flit[513]
 DIRECTION OUTPUT ;
 USE SIGNAL ;
 PORT
 LAYER M4 ;
 RECT 1865.760000 623.052000 1866.240000 623.076000 ;
 END
 END rx_flit[513]
 PIN rx_flit[514]
 DIRECTION OUTPUT ;
 USE SIGNAL ;
 PORT
 LAYER M4 ;
 RECT 1865.760000 623.196000 1866.240000 623.220000 ;
 END
 END rx_flit[514]
 PIN rx_flit[515]
 DIRECTION OUTPUT ;
 USE SIGNAL ;
 PORT
 LAYER M4 ;
 RECT 1865.760000 623.340000 1866.240000 623.364000 ;
 END
 END rx_flit[515]
 PIN rx_flit[516]
 DIRECTION OUTPUT ;
 USE SIGNAL ;
 PORT
 LAYER M4 ;
 RECT 1865.760000 623.484000 1866.240000 623.508000 ;
 END
 END rx_flit[516]
 PIN rx_flit[517]
 DIRECTION OUTPUT ;
 USE SIGNAL ;
 PORT
 LAYER M4 ;
 RECT 1865.760000 623.628000 1866.240000 623.652000 ;
 END
 END rx_flit[517]
 PIN rx_flit[518]
 DIRECTION OUTPUT ;
 USE SIGNAL ;
 PORT
 LAYER M4 ;
 RECT 1865.760000 623.772000 1866.240000 623.796000 ;
 END
 END rx_flit[518]
 PIN rx_flit[519]
 DIRECTION OUTPUT ;
 USE SIGNAL ;
 PORT
 LAYER M4 ;
 RECT 1865.760000 623.916000 1866.240000 623.940000 ;
 END
 END rx_flit[519]
 PIN rx_flit[520]
 DIRECTION OUTPUT ;
 USE SIGNAL ;
 PORT
 LAYER M4 ;
 RECT 1865.760000 624.060000 1866.240000 624.084000 ;
 END
 END rx_flit[520]
 PIN rx_flit[521]
 DIRECTION OUTPUT ;
 USE SIGNAL ;
 PORT
 LAYER M4 ;
 RECT 1865.760000 624.204000 1866.240000 624.228000 ;
 END
 END rx_flit[521]
 PIN VDD
 DIRECTION INOUT ;
 USE POWER ;
 PORT
 LAYER M7 ;
 RECT 2.004 0.5 2.124 971.5 ;
 RECT 6.324 0.5 6.444 971.5 ;
 RECT 10.644 0.5 10.764 971.5 ;
 RECT 14.964 0.5 15.084 971.5 ;
 RECT 19.284 0.5 19.404 971.5 ;
 RECT 23.604 0.5 23.724 971.5 ;
 RECT 27.924 0.5 28.044 971.5 ;
 RECT 32.244 0.5 32.364 971.5 ;
 RECT 36.564 0.5 36.684 971.5 ;
 RECT 40.884 0.5 41.004 971.5 ;
 RECT 45.204 0.5 45.324 971.5 ;
 RECT 49.524 0.5 49.644 971.5 ;
 RECT 53.844 0.5 53.964 971.5 ;
 RECT 58.164 0.5 58.284 971.5 ;
 RECT 62.484 0.5 62.604 971.5 ;
 RECT 66.804 0.5 66.924 971.5 ;
 RECT 71.124 0.5 71.244 971.5 ;
 RECT 75.444 0.5 75.564 971.5 ;
 RECT 79.764 0.5 79.884 971.5 ;
 RECT 84.084 0.5 84.204 971.5 ;
 RECT 88.404 0.5 88.524 971.5 ;
 RECT 92.724 0.5 92.844 971.5 ;
 RECT 97.044 0.5 97.164 971.5 ;
 RECT 101.364 0.5 101.484 971.5 ;
 RECT 105.684 0.5 105.804 971.5 ;
 RECT 110.004 0.5 110.124 971.5 ;
 RECT 114.324 0.5 114.444 971.5 ;
 RECT 118.644 0.5 118.764 971.5 ;
 RECT 122.964 0.5 123.084 971.5 ;
 RECT 127.284 0.5 127.404 971.5 ;
 RECT 131.604 0.5 131.724 971.5 ;
 RECT 135.924 0.5 136.044 971.5 ;
 RECT 140.244 0.5 140.364 971.5 ;
 RECT 144.564 0.5 144.684 971.5 ;
 RECT 148.884 0.5 149.004 971.5 ;
 RECT 153.204 0.5 153.324 971.5 ;
 RECT 157.524 0.5 157.644 971.5 ;
 RECT 161.844 0.5 161.964 971.5 ;
 RECT 166.164 0.5 166.284 971.5 ;
 RECT 170.484 0.5 170.604 971.5 ;
 RECT 174.804 0.5 174.924 971.5 ;
 RECT 179.124 0.5 179.244 971.5 ;
 RECT 183.444 0.5 183.564 971.5 ;
 RECT 187.764 0.5 187.884 971.5 ;
 RECT 192.084 0.5 192.204 971.5 ;
 RECT 196.404 0.5 196.524 971.5 ;
 RECT 200.724 0.5 200.844 971.5 ;
 RECT 205.044 0.5 205.164 971.5 ;
 RECT 209.364 0.5 209.484 971.5 ;
 RECT 213.684 0.5 213.804 971.5 ;
 RECT 218.004 0.5 218.124 971.5 ;
 RECT 222.324 0.5 222.444 971.5 ;
 RECT 226.644 0.5 226.764 971.5 ;
 RECT 230.964 0.5 231.084 971.5 ;
 RECT 235.284 0.5 235.404 971.5 ;
 RECT 239.604 0.5 239.724 971.5 ;
 RECT 243.924 0.5 244.044 971.5 ;
 RECT 248.244 0.5 248.364 971.5 ;
 RECT 252.564 0.5 252.684 971.5 ;
 RECT 256.884 0.5 257.004 971.5 ;
 RECT 261.204 0.5 261.324 971.5 ;
 RECT 265.524 0.5 265.644 971.5 ;
 RECT 269.844 0.5 269.964 971.5 ;
 RECT 274.164 0.5 274.284 971.5 ;
 RECT 278.484 0.5 278.604 971.5 ;
 RECT 282.804 0.5 282.924 971.5 ;
 RECT 287.124 0.5 287.244 971.5 ;
 RECT 291.444 0.5 291.564 971.5 ;
 RECT 295.764 0.5 295.884 971.5 ;
 RECT 300.084 0.5 300.204 971.5 ;
 RECT 304.404 0.5 304.524 971.5 ;
 RECT 308.724 0.5 308.844 971.5 ;
 RECT 313.044 0.5 313.164 971.5 ;
 RECT 317.364 0.5 317.484 971.5 ;
 RECT 321.684 0.5 321.804 971.5 ;
 RECT 326.004 0.5 326.124 971.5 ;
 RECT 330.324 0.5 330.444 971.5 ;
 RECT 334.644 0.5 334.764 971.5 ;
 RECT 338.964 0.5 339.084 971.5 ;
 RECT 343.284 0.5 343.404 971.5 ;
 RECT 347.604 0.5 347.724 971.5 ;
 RECT 351.924 0.5 352.044 971.5 ;
 RECT 356.244 0.5 356.364 971.5 ;
 RECT 360.564 0.5 360.684 971.5 ;
 RECT 364.884 0.5 365.004 971.5 ;
 RECT 369.204 0.5 369.324 971.5 ;
 RECT 373.524 0.5 373.644 971.5 ;
 RECT 377.844 0.5 377.964 971.5 ;
 RECT 382.164 0.5 382.284 971.5 ;
 RECT 386.484 0.5 386.604 971.5 ;
 RECT 390.804 0.5 390.924 971.5 ;
 RECT 395.124 0.5 395.244 971.5 ;
 RECT 399.444 0.5 399.564 971.5 ;
 RECT 403.764 0.5 403.884 971.5 ;
 RECT 408.084 0.5 408.204 971.5 ;
 RECT 412.404 0.5 412.524 971.5 ;
 RECT 416.724 0.5 416.844 971.5 ;
 RECT 421.044 0.5 421.164 971.5 ;
 RECT 425.364 0.5 425.484 971.5 ;
 RECT 429.684 0.5 429.804 971.5 ;
 RECT 434.004 0.5 434.124 971.5 ;
 RECT 438.324 0.5 438.444 971.5 ;
 RECT 442.644 0.5 442.764 971.5 ;
 RECT 446.964 0.5 447.084 971.5 ;
 RECT 451.284 0.5 451.404 971.5 ;
 RECT 455.604 0.5 455.724 971.5 ;
 RECT 459.924 0.5 460.044 971.5 ;
 RECT 464.244 0.5 464.364 971.5 ;
 RECT 468.564 0.5 468.684 971.5 ;
 RECT 472.884 0.5 473.004 971.5 ;
 RECT 477.204 0.5 477.324 971.5 ;
 RECT 481.524 0.5 481.644 971.5 ;
 RECT 485.844 0.5 485.964 971.5 ;
 RECT 490.164 0.5 490.284 971.5 ;
 RECT 494.484 0.5 494.604 971.5 ;
 RECT 498.804 0.5 498.924 971.5 ;
 RECT 503.124 0.5 503.244 971.5 ;
 RECT 507.444 0.5 507.564 971.5 ;
 RECT 511.764 0.5 511.884 971.5 ;
 RECT 516.084 0.5 516.204 971.5 ;
 RECT 520.404 0.5 520.524 971.5 ;
 RECT 524.724 0.5 524.844 971.5 ;
 RECT 529.044 0.5 529.164 971.5 ;
 RECT 533.364 0.5 533.484 971.5 ;
 RECT 537.684 0.5 537.804 971.5 ;
 RECT 542.004 0.5 542.124 971.5 ;
 RECT 546.324 0.5 546.444 971.5 ;
 RECT 550.644 0.5 550.764 971.5 ;
 RECT 554.964 0.5 555.084 971.5 ;
 RECT 559.284 0.5 559.404 971.5 ;
 RECT 563.604 0.5 563.724 971.5 ;
 RECT 567.924 0.5 568.044 971.5 ;
 RECT 572.244 0.5 572.364 971.5 ;
 RECT 576.564 0.5 576.684 971.5 ;
 RECT 580.884 0.5 581.004 971.5 ;
 RECT 585.204 0.5 585.324 971.5 ;
 RECT 589.524 0.5 589.644 971.5 ;
 RECT 593.844 0.5 593.964 971.5 ;
 RECT 598.164 0.5 598.284 971.5 ;
 RECT 602.484 0.5 602.604 971.5 ;
 RECT 606.804 0.5 606.924 971.5 ;
 RECT 611.124 0.5 611.244 971.5 ;
 RECT 615.444 0.5 615.564 971.5 ;
 RECT 619.764 0.5 619.884 971.5 ;
 RECT 624.084 0.5 624.204 971.5 ;
 RECT 628.404 0.5 628.524 971.5 ;
 RECT 632.724 0.5 632.844 971.5 ;
 RECT 637.044 0.5 637.164 971.5 ;
 RECT 641.364 0.5 641.484 971.5 ;
 RECT 645.684 0.5 645.804 971.5 ;
 RECT 650.004 0.5 650.124 971.5 ;
 RECT 654.324 0.5 654.444 971.5 ;
 RECT 658.644 0.5 658.764 971.5 ;
 RECT 662.964 0.5 663.084 971.5 ;
 RECT 667.284 0.5 667.404 971.5 ;
 RECT 671.604 0.5 671.724 971.5 ;
 RECT 675.924 0.5 676.044 971.5 ;
 RECT 680.244 0.5 680.364 971.5 ;
 RECT 684.564 0.5 684.684 971.5 ;
 RECT 688.884 0.5 689.004 971.5 ;
 RECT 693.204 0.5 693.324 971.5 ;
 RECT 697.524 0.5 697.644 971.5 ;
 RECT 701.844 0.5 701.964 971.5 ;
 RECT 706.164 0.5 706.284 971.5 ;
 RECT 710.484 0.5 710.604 971.5 ;
 RECT 714.804 0.5 714.924 971.5 ;
 RECT 719.124 0.5 719.244 971.5 ;
 RECT 723.444 0.5 723.564 971.5 ;
 RECT 727.764 0.5 727.884 971.5 ;
 RECT 732.084 0.5 732.204 971.5 ;
 RECT 736.404 0.5 736.524 971.5 ;
 RECT 740.724 0.5 740.844 971.5 ;
 RECT 745.044 0.5 745.164 971.5 ;
 RECT 749.364 0.5 749.484 971.5 ;
 RECT 753.684 0.5 753.804 971.5 ;
 RECT 758.004 0.5 758.124 971.5 ;
 RECT 762.324 0.5 762.444 971.5 ;
 RECT 766.644 0.5 766.764 971.5 ;
 RECT 770.964 0.5 771.084 971.5 ;
 RECT 775.284 0.5 775.404 971.5 ;
 RECT 779.604 0.5 779.724 971.5 ;
 RECT 783.924 0.5 784.044 971.5 ;
 RECT 788.244 0.5 788.364 971.5 ;
 RECT 792.564 0.5 792.684 971.5 ;
 RECT 796.884 0.5 797.004 971.5 ;
 RECT 801.204 0.5 801.324 971.5 ;
 RECT 805.524 0.5 805.644 971.5 ;
 RECT 809.844 0.5 809.964 971.5 ;
 RECT 814.164 0.5 814.284 971.5 ;
 RECT 818.484 0.5 818.604 971.5 ;
 RECT 822.804 0.5 822.924 971.5 ;
 RECT 827.124 0.5 827.244 971.5 ;
 RECT 831.444 0.5 831.564 971.5 ;
 RECT 835.764 0.5 835.884 971.5 ;
 RECT 840.084 0.5 840.204 971.5 ;
 RECT 844.404 0.5 844.524 971.5 ;
 RECT 848.724 0.5 848.844 971.5 ;
 RECT 853.044 0.5 853.164 971.5 ;
 RECT 857.364 0.5 857.484 971.5 ;
 RECT 861.684 0.5 861.804 971.5 ;
 RECT 866.004 0.5 866.124 971.5 ;
 RECT 870.324 0.5 870.444 971.5 ;
 RECT 874.644 0.5 874.764 971.5 ;
 RECT 878.964 0.5 879.084 971.5 ;
 RECT 883.284 0.5 883.404 971.5 ;
 RECT 887.604 0.5 887.724 971.5 ;
 RECT 891.924 0.5 892.044 971.5 ;
 RECT 896.244 0.5 896.364 971.5 ;
 RECT 900.564 0.5 900.684 971.5 ;
 RECT 904.884 0.5 905.004 971.5 ;
 RECT 909.204 0.5 909.324 971.5 ;
 RECT 913.524 0.5 913.644 971.5 ;
 RECT 917.844 0.5 917.964 971.5 ;
 RECT 922.164 0.5 922.284 971.5 ;
 RECT 926.484 0.5 926.604 971.5 ;
 RECT 930.804 0.5 930.924 971.5 ;
 RECT 935.124 0.5 935.244 971.5 ;
 RECT 939.444 0.5 939.564 971.5 ;
 RECT 943.764 0.5 943.884 971.5 ;
 RECT 948.084 0.5 948.204 971.5 ;
 RECT 952.404 0.5 952.524 971.5 ;
 RECT 956.724 0.5 956.844 971.5 ;
 RECT 961.044 0.5 961.164 971.5 ;
 RECT 965.364 0.5 965.484 971.5 ;
 RECT 969.684 0.5 969.804 971.5 ;
 RECT 974.004 0.5 974.124 971.5 ;
 RECT 978.324 0.5 978.444 971.5 ;
 RECT 982.644 0.5 982.764 971.5 ;
 RECT 986.964 0.5 987.084 971.5 ;
 RECT 991.284 0.5 991.404 971.5 ;
 RECT 995.604 0.5 995.724 971.5 ;
 RECT 999.924 0.5 1000.044 971.5 ;
 RECT 1004.244 0.5 1004.364 971.5 ;
 RECT 1008.564 0.5 1008.684 971.5 ;
 RECT 1012.884 0.5 1013.004 971.5 ;
 RECT 1017.204 0.5 1017.324 971.5 ;
 RECT 1021.524 0.5 1021.644 971.5 ;
 RECT 1025.844 0.5 1025.964 971.5 ;
 RECT 1030.164 0.5 1030.284 971.5 ;
 RECT 1034.484 0.5 1034.604 971.5 ;
 RECT 1038.804 0.5 1038.924 971.5 ;
 RECT 1043.124 0.5 1043.244 971.5 ;
 RECT 1047.444 0.5 1047.564 971.5 ;
 RECT 1051.764 0.5 1051.884 971.5 ;
 RECT 1056.084 0.5 1056.204 971.5 ;
 RECT 1060.404 0.5 1060.524 971.5 ;
 RECT 1064.724 0.5 1064.844 971.5 ;
 RECT 1069.044 0.5 1069.164 971.5 ;
 RECT 1073.364 0.5 1073.484 971.5 ;
 RECT 1077.684 0.5 1077.804 971.5 ;
 RECT 1082.004 0.5 1082.124 971.5 ;
 RECT 1086.324 0.5 1086.444 971.5 ;
 RECT 1090.644 0.5 1090.764 971.5 ;
 RECT 1094.964 0.5 1095.084 971.5 ;
 RECT 1099.284 0.5 1099.404 971.5 ;
 RECT 1103.604 0.5 1103.724 971.5 ;
 RECT 1107.924 0.5 1108.044 971.5 ;
 RECT 1112.244 0.5 1112.364 971.5 ;
 RECT 1116.564 0.5 1116.684 971.5 ;
 RECT 1120.884 0.5 1121.004 971.5 ;
 RECT 1125.204 0.5 1125.324 971.5 ;
 RECT 1129.524 0.5 1129.644 971.5 ;
 RECT 1133.844 0.5 1133.964 971.5 ;
 RECT 1138.164 0.5 1138.284 971.5 ;
 RECT 1142.484 0.5 1142.604 971.5 ;
 RECT 1146.804 0.5 1146.924 971.5 ;
 RECT 1151.124 0.5 1151.244 971.5 ;
 RECT 1155.444 0.5 1155.564 971.5 ;
 RECT 1159.764 0.5 1159.884 971.5 ;
 RECT 1164.084 0.5 1164.204 971.5 ;
 RECT 1168.404 0.5 1168.524 971.5 ;
 RECT 1172.724 0.5 1172.844 971.5 ;
 RECT 1177.044 0.5 1177.164 971.5 ;
 RECT 1181.364 0.5 1181.484 971.5 ;
 RECT 1185.684 0.5 1185.804 971.5 ;
 RECT 1190.004 0.5 1190.124 971.5 ;
 RECT 1194.324 0.5 1194.444 971.5 ;
 RECT 1198.644 0.5 1198.764 971.5 ;
 RECT 1202.964 0.5 1203.084 971.5 ;
 RECT 1207.284 0.5 1207.404 971.5 ;
 RECT 1211.604 0.5 1211.724 971.5 ;
 RECT 1215.924 0.5 1216.044 971.5 ;
 RECT 1220.244 0.5 1220.364 971.5 ;
 RECT 1224.564 0.5 1224.684 971.5 ;
 RECT 1228.884 0.5 1229.004 971.5 ;
 RECT 1233.204 0.5 1233.324 971.5 ;
 RECT 1237.524 0.5 1237.644 971.5 ;
 RECT 1241.844 0.5 1241.964 971.5 ;
 RECT 1246.164 0.5 1246.284 971.5 ;
 RECT 1250.484 0.5 1250.604 971.5 ;
 RECT 1254.804 0.5 1254.924 971.5 ;
 RECT 1259.124 0.5 1259.244 971.5 ;
 RECT 1263.444 0.5 1263.564 971.5 ;
 RECT 1267.764 0.5 1267.884 971.5 ;
 RECT 1272.084 0.5 1272.204 971.5 ;
 RECT 1276.404 0.5 1276.524 971.5 ;
 RECT 1280.724 0.5 1280.844 971.5 ;
 RECT 1285.044 0.5 1285.164 971.5 ;
 RECT 1289.364 0.5 1289.484 971.5 ;
 RECT 1293.684 0.5 1293.804 971.5 ;
 RECT 1298.004 0.5 1298.124 971.5 ;
 RECT 1302.324 0.5 1302.444 971.5 ;
 RECT 1306.644 0.5 1306.764 971.5 ;
 RECT 1310.964 0.5 1311.084 971.5 ;
 RECT 1315.284 0.5 1315.404 971.5 ;
 RECT 1319.604 0.5 1319.724 971.5 ;
 RECT 1323.924 0.5 1324.044 971.5 ;
 RECT 1328.244 0.5 1328.364 971.5 ;
 RECT 1332.564 0.5 1332.684 971.5 ;
 RECT 1336.884 0.5 1337.004 971.5 ;
 RECT 1341.204 0.5 1341.324 971.5 ;
 RECT 1345.524 0.5 1345.644 971.5 ;
 RECT 1349.844 0.5 1349.964 971.5 ;
 RECT 1354.164 0.5 1354.284 971.5 ;
 RECT 1358.484 0.5 1358.604 971.5 ;
 RECT 1362.804 0.5 1362.924 971.5 ;
 RECT 1367.124 0.5 1367.244 971.5 ;
 RECT 1371.444 0.5 1371.564 971.5 ;
 RECT 1375.764 0.5 1375.884 971.5 ;
 RECT 1380.084 0.5 1380.204 971.5 ;
 RECT 1384.404 0.5 1384.524 971.5 ;
 RECT 1388.724 0.5 1388.844 971.5 ;
 RECT 1393.044 0.5 1393.164 971.5 ;
 RECT 1397.364 0.5 1397.484 971.5 ;
 RECT 1401.684 0.5 1401.804 971.5 ;
 RECT 1406.004 0.5 1406.124 971.5 ;
 RECT 1410.324 0.5 1410.444 971.5 ;
 RECT 1414.644 0.5 1414.764 971.5 ;
 RECT 1418.964 0.5 1419.084 971.5 ;
 RECT 1423.284 0.5 1423.404 971.5 ;
 RECT 1427.604 0.5 1427.724 971.5 ;
 RECT 1431.924 0.5 1432.044 971.5 ;
 RECT 1436.244 0.5 1436.364 971.5 ;
 RECT 1440.564 0.5 1440.684 971.5 ;
 RECT 1444.884 0.5 1445.004 971.5 ;
 RECT 1449.204 0.5 1449.324 971.5 ;
 RECT 1453.524 0.5 1453.644 971.5 ;
 RECT 1457.844 0.5 1457.964 971.5 ;
 RECT 1462.164 0.5 1462.284 971.5 ;
 RECT 1466.484 0.5 1466.604 971.5 ;
 RECT 1470.804 0.5 1470.924 971.5 ;
 RECT 1475.124 0.5 1475.244 971.5 ;
 RECT 1479.444 0.5 1479.564 971.5 ;
 RECT 1483.764 0.5 1483.884 971.5 ;
 RECT 1488.084 0.5 1488.204 971.5 ;
 RECT 1492.404 0.5 1492.524 971.5 ;
 RECT 1496.724 0.5 1496.844 971.5 ;
 RECT 1501.044 0.5 1501.164 971.5 ;
 RECT 1505.364 0.5 1505.484 971.5 ;
 RECT 1509.684 0.5 1509.804 971.5 ;
 RECT 1514.004 0.5 1514.124 971.5 ;
 RECT 1518.324 0.5 1518.444 971.5 ;
 RECT 1522.644 0.5 1522.764 971.5 ;
 RECT 1526.964 0.5 1527.084 971.5 ;
 RECT 1531.284 0.5 1531.404 971.5 ;
 RECT 1535.604 0.5 1535.724 971.5 ;
 RECT 1539.924 0.5 1540.044 971.5 ;
 RECT 1544.244 0.5 1544.364 971.5 ;
 RECT 1548.564 0.5 1548.684 971.5 ;
 RECT 1552.884 0.5 1553.004 971.5 ;
 RECT 1557.204 0.5 1557.324 971.5 ;
 RECT 1561.524 0.5 1561.644 971.5 ;
 RECT 1565.844 0.5 1565.964 971.5 ;
 RECT 1570.164 0.5 1570.284 971.5 ;
 RECT 1574.484 0.5 1574.604 971.5 ;
 RECT 1578.804 0.5 1578.924 971.5 ;
 RECT 1583.124 0.5 1583.244 971.5 ;
 RECT 1587.444 0.5 1587.564 971.5 ;
 RECT 1591.764 0.5 1591.884 971.5 ;
 RECT 1596.084 0.5 1596.204 971.5 ;
 RECT 1600.404 0.5 1600.524 971.5 ;
 RECT 1604.724 0.5 1604.844 971.5 ;
 RECT 1609.044 0.5 1609.164 971.5 ;
 RECT 1613.364 0.5 1613.484 971.5 ;
 RECT 1617.684 0.5 1617.804 971.5 ;
 RECT 1622.004 0.5 1622.124 971.5 ;
 RECT 1626.324 0.5 1626.444 971.5 ;
 RECT 1630.644 0.5 1630.764 971.5 ;
 RECT 1634.964 0.5 1635.084 971.5 ;
 RECT 1639.284 0.5 1639.404 971.5 ;
 RECT 1643.604 0.5 1643.724 971.5 ;
 RECT 1647.924 0.5 1648.044 971.5 ;
 RECT 1652.244 0.5 1652.364 971.5 ;
 RECT 1656.564 0.5 1656.684 971.5 ;
 RECT 1660.884 0.5 1661.004 971.5 ;
 RECT 1665.204 0.5 1665.324 971.5 ;
 RECT 1669.524 0.5 1669.644 971.5 ;
 RECT 1673.844 0.5 1673.964 971.5 ;
 RECT 1678.164 0.5 1678.284 971.5 ;
 RECT 1682.484 0.5 1682.604 971.5 ;
 RECT 1686.804 0.5 1686.924 971.5 ;
 RECT 1691.124 0.5 1691.244 971.5 ;
 RECT 1695.444 0.5 1695.564 971.5 ;
 RECT 1699.764 0.5 1699.884 971.5 ;
 RECT 1704.084 0.5 1704.204 971.5 ;
 RECT 1708.404 0.5 1708.524 971.5 ;
 RECT 1712.724 0.5 1712.844 971.5 ;
 RECT 1717.044 0.5 1717.164 971.5 ;
 RECT 1721.364 0.5 1721.484 971.5 ;
 RECT 1725.684 0.5 1725.804 971.5 ;
 RECT 1730.004 0.5 1730.124 971.5 ;
 RECT 1734.324 0.5 1734.444 971.5 ;
 RECT 1738.644 0.5 1738.764 971.5 ;
 RECT 1742.964 0.5 1743.084 971.5 ;
 RECT 1747.284 0.5 1747.404 971.5 ;
 RECT 1751.604 0.5 1751.724 971.5 ;
 RECT 1755.924 0.5 1756.044 971.5 ;
 RECT 1760.244 0.5 1760.364 971.5 ;
 RECT 1764.564 0.5 1764.684 971.5 ;
 RECT 1768.884 0.5 1769.004 971.5 ;
 RECT 1773.204 0.5 1773.324 971.5 ;
 RECT 1777.524 0.5 1777.644 971.5 ;
 RECT 1781.844 0.5 1781.964 971.5 ;
 RECT 1786.164 0.5 1786.284 971.5 ;
 RECT 1790.484 0.5 1790.604 971.5 ;
 RECT 1794.804 0.5 1794.924 971.5 ;
 RECT 1799.124 0.5 1799.244 971.5 ;
 RECT 1803.444 0.5 1803.564 971.5 ;
 RECT 1807.764 0.5 1807.884 971.5 ;
 RECT 1812.084 0.5 1812.204 971.5 ;
 RECT 1816.404 0.5 1816.524 971.5 ;
 RECT 1820.724 0.5 1820.844 971.5 ;
 RECT 1825.044 0.5 1825.164 971.5 ;
 RECT 1829.364 0.5 1829.484 971.5 ;
 RECT 1833.684 0.5 1833.804 971.5 ;
 RECT 1838.004 0.5 1838.124 971.5 ;
 RECT 1842.324 0.5 1842.444 971.5 ;
 RECT 1846.644 0.5 1846.764 971.5 ;
 RECT 1850.964 0.5 1851.084 971.5 ;
 RECT 1855.284 0.5 1855.404 971.5 ;
 RECT 1859.604 0.5 1859.724 971.5 ;
 RECT 1863.924 0.5 1864.044 971.5 ;
 END
 END VDD
 PIN VSS
 DIRECTION INOUT ;
 USE GROUND ;
 PORT
 LAYER M7 ;
 RECT 2.196 0.5 2.316 971.5 ;
 RECT 6.516 0.5 6.636 971.5 ;
 RECT 10.836 0.5 10.956 971.5 ;
 RECT 15.156 0.5 15.276 971.5 ;
 RECT 19.476 0.5 19.596 971.5 ;
 RECT 23.796 0.5 23.916 971.5 ;
 RECT 28.116 0.5 28.236 971.5 ;
 RECT 32.436 0.5 32.556 971.5 ;
 RECT 36.756 0.5 36.876 971.5 ;
 RECT 41.076 0.5 41.196 971.5 ;
 RECT 45.396 0.5 45.516 971.5 ;
 RECT 49.716 0.5 49.836 971.5 ;
 RECT 54.036 0.5 54.156 971.5 ;
 RECT 58.356 0.5 58.476 971.5 ;
 RECT 62.676 0.5 62.796 971.5 ;
 RECT 66.996 0.5 67.116 971.5 ;
 RECT 71.316 0.5 71.436 971.5 ;
 RECT 75.636 0.5 75.756 971.5 ;
 RECT 79.956 0.5 80.076 971.5 ;
 RECT 84.276 0.5 84.396 971.5 ;
 RECT 88.596 0.5 88.716 971.5 ;
 RECT 92.916 0.5 93.036 971.5 ;
 RECT 97.236 0.5 97.356 971.5 ;
 RECT 101.556 0.5 101.676 971.5 ;
 RECT 105.876 0.5 105.996 971.5 ;
 RECT 110.196 0.5 110.316 971.5 ;
 RECT 114.516 0.5 114.636 971.5 ;
 RECT 118.836 0.5 118.956 971.5 ;
 RECT 123.156 0.5 123.276 971.5 ;
 RECT 127.476 0.5 127.596 971.5 ;
 RECT 131.796 0.5 131.916 971.5 ;
 RECT 136.116 0.5 136.236 971.5 ;
 RECT 140.436 0.5 140.556 971.5 ;
 RECT 144.756 0.5 144.876 971.5 ;
 RECT 149.076 0.5 149.196 971.5 ;
 RECT 153.396 0.5 153.516 971.5 ;
 RECT 157.716 0.5 157.836 971.5 ;
 RECT 162.036 0.5 162.156 971.5 ;
 RECT 166.356 0.5 166.476 971.5 ;
 RECT 170.676 0.5 170.796 971.5 ;
 RECT 174.996 0.5 175.116 971.5 ;
 RECT 179.316 0.5 179.436 971.5 ;
 RECT 183.636 0.5 183.756 971.5 ;
 RECT 187.956 0.5 188.076 971.5 ;
 RECT 192.276 0.5 192.396 971.5 ;
 RECT 196.596 0.5 196.716 971.5 ;
 RECT 200.916 0.5 201.036 971.5 ;
 RECT 205.236 0.5 205.356 971.5 ;
 RECT 209.556 0.5 209.676 971.5 ;
 RECT 213.876 0.5 213.996 971.5 ;
 RECT 218.196 0.5 218.316 971.5 ;
 RECT 222.516 0.5 222.636 971.5 ;
 RECT 226.836 0.5 226.956 971.5 ;
 RECT 231.156 0.5 231.276 971.5 ;
 RECT 235.476 0.5 235.596 971.5 ;
 RECT 239.796 0.5 239.916 971.5 ;
 RECT 244.116 0.5 244.236 971.5 ;
 RECT 248.436 0.5 248.556 971.5 ;
 RECT 252.756 0.5 252.876 971.5 ;
 RECT 257.076 0.5 257.196 971.5 ;
 RECT 261.396 0.5 261.516 971.5 ;
 RECT 265.716 0.5 265.836 971.5 ;
 RECT 270.036 0.5 270.156 971.5 ;
 RECT 274.356 0.5 274.476 971.5 ;
 RECT 278.676 0.5 278.796 971.5 ;
 RECT 282.996 0.5 283.116 971.5 ;
 RECT 287.316 0.5 287.436 971.5 ;
 RECT 291.636 0.5 291.756 971.5 ;
 RECT 295.956 0.5 296.076 971.5 ;
 RECT 300.276 0.5 300.396 971.5 ;
 RECT 304.596 0.5 304.716 971.5 ;
 RECT 308.916 0.5 309.036 971.5 ;
 RECT 313.236 0.5 313.356 971.5 ;
 RECT 317.556 0.5 317.676 971.5 ;
 RECT 321.876 0.5 321.996 971.5 ;
 RECT 326.196 0.5 326.316 971.5 ;
 RECT 330.516 0.5 330.636 971.5 ;
 RECT 334.836 0.5 334.956 971.5 ;
 RECT 339.156 0.5 339.276 971.5 ;
 RECT 343.476 0.5 343.596 971.5 ;
 RECT 347.796 0.5 347.916 971.5 ;
 RECT 352.116 0.5 352.236 971.5 ;
 RECT 356.436 0.5 356.556 971.5 ;
 RECT 360.756 0.5 360.876 971.5 ;
 RECT 365.076 0.5 365.196 971.5 ;
 RECT 369.396 0.5 369.516 971.5 ;
 RECT 373.716 0.5 373.836 971.5 ;
 RECT 378.036 0.5 378.156 971.5 ;
 RECT 382.356 0.5 382.476 971.5 ;
 RECT 386.676 0.5 386.796 971.5 ;
 RECT 390.996 0.5 391.116 971.5 ;
 RECT 395.316 0.5 395.436 971.5 ;
 RECT 399.636 0.5 399.756 971.5 ;
 RECT 403.956 0.5 404.076 971.5 ;
 RECT 408.276 0.5 408.396 971.5 ;
 RECT 412.596 0.5 412.716 971.5 ;
 RECT 416.916 0.5 417.036 971.5 ;
 RECT 421.236 0.5 421.356 971.5 ;
 RECT 425.556 0.5 425.676 971.5 ;
 RECT 429.876 0.5 429.996 971.5 ;
 RECT 434.196 0.5 434.316 971.5 ;
 RECT 438.516 0.5 438.636 971.5 ;
 RECT 442.836 0.5 442.956 971.5 ;
 RECT 447.156 0.5 447.276 971.5 ;
 RECT 451.476 0.5 451.596 971.5 ;
 RECT 455.796 0.5 455.916 971.5 ;
 RECT 460.116 0.5 460.236 971.5 ;
 RECT 464.436 0.5 464.556 971.5 ;
 RECT 468.756 0.5 468.876 971.5 ;
 RECT 473.076 0.5 473.196 971.5 ;
 RECT 477.396 0.5 477.516 971.5 ;
 RECT 481.716 0.5 481.836 971.5 ;
 RECT 486.036 0.5 486.156 971.5 ;
 RECT 490.356 0.5 490.476 971.5 ;
 RECT 494.676 0.5 494.796 971.5 ;
 RECT 498.996 0.5 499.116 971.5 ;
 RECT 503.316 0.5 503.436 971.5 ;
 RECT 507.636 0.5 507.756 971.5 ;
 RECT 511.956 0.5 512.076 971.5 ;
 RECT 516.276 0.5 516.396 971.5 ;
 RECT 520.596 0.5 520.716 971.5 ;
 RECT 524.916 0.5 525.036 971.5 ;
 RECT 529.236 0.5 529.356 971.5 ;
 RECT 533.556 0.5 533.676 971.5 ;
 RECT 537.876 0.5 537.996 971.5 ;
 RECT 542.196 0.5 542.316 971.5 ;
 RECT 546.516 0.5 546.636 971.5 ;
 RECT 550.836 0.5 550.956 971.5 ;
 RECT 555.156 0.5 555.276 971.5 ;
 RECT 559.476 0.5 559.596 971.5 ;
 RECT 563.796 0.5 563.916 971.5 ;
 RECT 568.116 0.5 568.236 971.5 ;
 RECT 572.436 0.5 572.556 971.5 ;
 RECT 576.756 0.5 576.876 971.5 ;
 RECT 581.076 0.5 581.196 971.5 ;
 RECT 585.396 0.5 585.516 971.5 ;
 RECT 589.716 0.5 589.836 971.5 ;
 RECT 594.036 0.5 594.156 971.5 ;
 RECT 598.356 0.5 598.476 971.5 ;
 RECT 602.676 0.5 602.796 971.5 ;
 RECT 606.996 0.5 607.116 971.5 ;
 RECT 611.316 0.5 611.436 971.5 ;
 RECT 615.636 0.5 615.756 971.5 ;
 RECT 619.956 0.5 620.076 971.5 ;
 RECT 624.276 0.5 624.396 971.5 ;
 RECT 628.596 0.5 628.716 971.5 ;
 RECT 632.916 0.5 633.036 971.5 ;
 RECT 637.236 0.5 637.356 971.5 ;
 RECT 641.556 0.5 641.676 971.5 ;
 RECT 645.876 0.5 645.996 971.5 ;
 RECT 650.196 0.5 650.316 971.5 ;
 RECT 654.516 0.5 654.636 971.5 ;
 RECT 658.836 0.5 658.956 971.5 ;
 RECT 663.156 0.5 663.276 971.5 ;
 RECT 667.476 0.5 667.596 971.5 ;
 RECT 671.796 0.5 671.916 971.5 ;
 RECT 676.116 0.5 676.236 971.5 ;
 RECT 680.436 0.5 680.556 971.5 ;
 RECT 684.756 0.5 684.876 971.5 ;
 RECT 689.076 0.5 689.196 971.5 ;
 RECT 693.396 0.5 693.516 971.5 ;
 RECT 697.716 0.5 697.836 971.5 ;
 RECT 702.036 0.5 702.156 971.5 ;
 RECT 706.356 0.5 706.476 971.5 ;
 RECT 710.676 0.5 710.796 971.5 ;
 RECT 714.996 0.5 715.116 971.5 ;
 RECT 719.316 0.5 719.436 971.5 ;
 RECT 723.636 0.5 723.756 971.5 ;
 RECT 727.956 0.5 728.076 971.5 ;
 RECT 732.276 0.5 732.396 971.5 ;
 RECT 736.596 0.5 736.716 971.5 ;
 RECT 740.916 0.5 741.036 971.5 ;
 RECT 745.236 0.5 745.356 971.5 ;
 RECT 749.556 0.5 749.676 971.5 ;
 RECT 753.876 0.5 753.996 971.5 ;
 RECT 758.196 0.5 758.316 971.5 ;
 RECT 762.516 0.5 762.636 971.5 ;
 RECT 766.836 0.5 766.956 971.5 ;
 RECT 771.156 0.5 771.276 971.5 ;
 RECT 775.476 0.5 775.596 971.5 ;
 RECT 779.796 0.5 779.916 971.5 ;
 RECT 784.116 0.5 784.236 971.5 ;
 RECT 788.436 0.5 788.556 971.5 ;
 RECT 792.756 0.5 792.876 971.5 ;
 RECT 797.076 0.5 797.196 971.5 ;
 RECT 801.396 0.5 801.516 971.5 ;
 RECT 805.716 0.5 805.836 971.5 ;
 RECT 810.036 0.5 810.156 971.5 ;
 RECT 814.356 0.5 814.476 971.5 ;
 RECT 818.676 0.5 818.796 971.5 ;
 RECT 822.996 0.5 823.116 971.5 ;
 RECT 827.316 0.5 827.436 971.5 ;
 RECT 831.636 0.5 831.756 971.5 ;
 RECT 835.956 0.5 836.076 971.5 ;
 RECT 840.276 0.5 840.396 971.5 ;
 RECT 844.596 0.5 844.716 971.5 ;
 RECT 848.916 0.5 849.036 971.5 ;
 RECT 853.236 0.5 853.356 971.5 ;
 RECT 857.556 0.5 857.676 971.5 ;
 RECT 861.876 0.5 861.996 971.5 ;
 RECT 866.196 0.5 866.316 971.5 ;
 RECT 870.516 0.5 870.636 971.5 ;
 RECT 874.836 0.5 874.956 971.5 ;
 RECT 879.156 0.5 879.276 971.5 ;
 RECT 883.476 0.5 883.596 971.5 ;
 RECT 887.796 0.5 887.916 971.5 ;
 RECT 892.116 0.5 892.236 971.5 ;
 RECT 896.436 0.5 896.556 971.5 ;
 RECT 900.756 0.5 900.876 971.5 ;
 RECT 905.076 0.5 905.196 971.5 ;
 RECT 909.396 0.5 909.516 971.5 ;
 RECT 913.716 0.5 913.836 971.5 ;
 RECT 918.036 0.5 918.156 971.5 ;
 RECT 922.356 0.5 922.476 971.5 ;
 RECT 926.676 0.5 926.796 971.5 ;
 RECT 930.996 0.5 931.116 971.5 ;
 RECT 935.316 0.5 935.436 971.5 ;
 RECT 939.636 0.5 939.756 971.5 ;
 RECT 943.956 0.5 944.076 971.5 ;
 RECT 948.276 0.5 948.396 971.5 ;
 RECT 952.596 0.5 952.716 971.5 ;
 RECT 956.916 0.5 957.036 971.5 ;
 RECT 961.236 0.5 961.356 971.5 ;
 RECT 965.556 0.5 965.676 971.5 ;
 RECT 969.876 0.5 969.996 971.5 ;
 RECT 974.196 0.5 974.316 971.5 ;
 RECT 978.516 0.5 978.636 971.5 ;
 RECT 982.836 0.5 982.956 971.5 ;
 RECT 987.156 0.5 987.276 971.5 ;
 RECT 991.476 0.5 991.596 971.5 ;
 RECT 995.796 0.5 995.916 971.5 ;
 RECT 1000.116 0.5 1000.236 971.5 ;
 RECT 1004.436 0.5 1004.556 971.5 ;
 RECT 1008.756 0.5 1008.876 971.5 ;
 RECT 1013.076 0.5 1013.196 971.5 ;
 RECT 1017.396 0.5 1017.516 971.5 ;
 RECT 1021.716 0.5 1021.836 971.5 ;
 RECT 1026.036 0.5 1026.156 971.5 ;
 RECT 1030.356 0.5 1030.476 971.5 ;
 RECT 1034.676 0.5 1034.796 971.5 ;
 RECT 1038.996 0.5 1039.116 971.5 ;
 RECT 1043.316 0.5 1043.436 971.5 ;
 RECT 1047.636 0.5 1047.756 971.5 ;
 RECT 1051.956 0.5 1052.076 971.5 ;
 RECT 1056.276 0.5 1056.396 971.5 ;
 RECT 1060.596 0.5 1060.716 971.5 ;
 RECT 1064.916 0.5 1065.036 971.5 ;
 RECT 1069.236 0.5 1069.356 971.5 ;
 RECT 1073.556 0.5 1073.676 971.5 ;
 RECT 1077.876 0.5 1077.996 971.5 ;
 RECT 1082.196 0.5 1082.316 971.5 ;
 RECT 1086.516 0.5 1086.636 971.5 ;
 RECT 1090.836 0.5 1090.956 971.5 ;
 RECT 1095.156 0.5 1095.276 971.5 ;
 RECT 1099.476 0.5 1099.596 971.5 ;
 RECT 1103.796 0.5 1103.916 971.5 ;
 RECT 1108.116 0.5 1108.236 971.5 ;
 RECT 1112.436 0.5 1112.556 971.5 ;
 RECT 1116.756 0.5 1116.876 971.5 ;
 RECT 1121.076 0.5 1121.196 971.5 ;
 RECT 1125.396 0.5 1125.516 971.5 ;
 RECT 1129.716 0.5 1129.836 971.5 ;
 RECT 1134.036 0.5 1134.156 971.5 ;
 RECT 1138.356 0.5 1138.476 971.5 ;
 RECT 1142.676 0.5 1142.796 971.5 ;
 RECT 1146.996 0.5 1147.116 971.5 ;
 RECT 1151.316 0.5 1151.436 971.5 ;
 RECT 1155.636 0.5 1155.756 971.5 ;
 RECT 1159.956 0.5 1160.076 971.5 ;
 RECT 1164.276 0.5 1164.396 971.5 ;
 RECT 1168.596 0.5 1168.716 971.5 ;
 RECT 1172.916 0.5 1173.036 971.5 ;
 RECT 1177.236 0.5 1177.356 971.5 ;
 RECT 1181.556 0.5 1181.676 971.5 ;
 RECT 1185.876 0.5 1185.996 971.5 ;
 RECT 1190.196 0.5 1190.316 971.5 ;
 RECT 1194.516 0.5 1194.636 971.5 ;
 RECT 1198.836 0.5 1198.956 971.5 ;
 RECT 1203.156 0.5 1203.276 971.5 ;
 RECT 1207.476 0.5 1207.596 971.5 ;
 RECT 1211.796 0.5 1211.916 971.5 ;
 RECT 1216.116 0.5 1216.236 971.5 ;
 RECT 1220.436 0.5 1220.556 971.5 ;
 RECT 1224.756 0.5 1224.876 971.5 ;
 RECT 1229.076 0.5 1229.196 971.5 ;
 RECT 1233.396 0.5 1233.516 971.5 ;
 RECT 1237.716 0.5 1237.836 971.5 ;
 RECT 1242.036 0.5 1242.156 971.5 ;
 RECT 1246.356 0.5 1246.476 971.5 ;
 RECT 1250.676 0.5 1250.796 971.5 ;
 RECT 1254.996 0.5 1255.116 971.5 ;
 RECT 1259.316 0.5 1259.436 971.5 ;
 RECT 1263.636 0.5 1263.756 971.5 ;
 RECT 1267.956 0.5 1268.076 971.5 ;
 RECT 1272.276 0.5 1272.396 971.5 ;
 RECT 1276.596 0.5 1276.716 971.5 ;
 RECT 1280.916 0.5 1281.036 971.5 ;
 RECT 1285.236 0.5 1285.356 971.5 ;
 RECT 1289.556 0.5 1289.676 971.5 ;
 RECT 1293.876 0.5 1293.996 971.5 ;
 RECT 1298.196 0.5 1298.316 971.5 ;
 RECT 1302.516 0.5 1302.636 971.5 ;
 RECT 1306.836 0.5 1306.956 971.5 ;
 RECT 1311.156 0.5 1311.276 971.5 ;
 RECT 1315.476 0.5 1315.596 971.5 ;
 RECT 1319.796 0.5 1319.916 971.5 ;
 RECT 1324.116 0.5 1324.236 971.5 ;
 RECT 1328.436 0.5 1328.556 971.5 ;
 RECT 1332.756 0.5 1332.876 971.5 ;
 RECT 1337.076 0.5 1337.196 971.5 ;
 RECT 1341.396 0.5 1341.516 971.5 ;
 RECT 1345.716 0.5 1345.836 971.5 ;
 RECT 1350.036 0.5 1350.156 971.5 ;
 RECT 1354.356 0.5 1354.476 971.5 ;
 RECT 1358.676 0.5 1358.796 971.5 ;
 RECT 1362.996 0.5 1363.116 971.5 ;
 RECT 1367.316 0.5 1367.436 971.5 ;
 RECT 1371.636 0.5 1371.756 971.5 ;
 RECT 1375.956 0.5 1376.076 971.5 ;
 RECT 1380.276 0.5 1380.396 971.5 ;
 RECT 1384.596 0.5 1384.716 971.5 ;
 RECT 1388.916 0.5 1389.036 971.5 ;
 RECT 1393.236 0.5 1393.356 971.5 ;
 RECT 1397.556 0.5 1397.676 971.5 ;
 RECT 1401.876 0.5 1401.996 971.5 ;
 RECT 1406.196 0.5 1406.316 971.5 ;
 RECT 1410.516 0.5 1410.636 971.5 ;
 RECT 1414.836 0.5 1414.956 971.5 ;
 RECT 1419.156 0.5 1419.276 971.5 ;
 RECT 1423.476 0.5 1423.596 971.5 ;
 RECT 1427.796 0.5 1427.916 971.5 ;
 RECT 1432.116 0.5 1432.236 971.5 ;
 RECT 1436.436 0.5 1436.556 971.5 ;
 RECT 1440.756 0.5 1440.876 971.5 ;
 RECT 1445.076 0.5 1445.196 971.5 ;
 RECT 1449.396 0.5 1449.516 971.5 ;
 RECT 1453.716 0.5 1453.836 971.5 ;
 RECT 1458.036 0.5 1458.156 971.5 ;
 RECT 1462.356 0.5 1462.476 971.5 ;
 RECT 1466.676 0.5 1466.796 971.5 ;
 RECT 1470.996 0.5 1471.116 971.5 ;
 RECT 1475.316 0.5 1475.436 971.5 ;
 RECT 1479.636 0.5 1479.756 971.5 ;
 RECT 1483.956 0.5 1484.076 971.5 ;
 RECT 1488.276 0.5 1488.396 971.5 ;
 RECT 1492.596 0.5 1492.716 971.5 ;
 RECT 1496.916 0.5 1497.036 971.5 ;
 RECT 1501.236 0.5 1501.356 971.5 ;
 RECT 1505.556 0.5 1505.676 971.5 ;
 RECT 1509.876 0.5 1509.996 971.5 ;
 RECT 1514.196 0.5 1514.316 971.5 ;
 RECT 1518.516 0.5 1518.636 971.5 ;
 RECT 1522.836 0.5 1522.956 971.5 ;
 RECT 1527.156 0.5 1527.276 971.5 ;
 RECT 1531.476 0.5 1531.596 971.5 ;
 RECT 1535.796 0.5 1535.916 971.5 ;
 RECT 1540.116 0.5 1540.236 971.5 ;
 RECT 1544.436 0.5 1544.556 971.5 ;
 RECT 1548.756 0.5 1548.876 971.5 ;
 RECT 1553.076 0.5 1553.196 971.5 ;
 RECT 1557.396 0.5 1557.516 971.5 ;
 RECT 1561.716 0.5 1561.836 971.5 ;
 RECT 1566.036 0.5 1566.156 971.5 ;
 RECT 1570.356 0.5 1570.476 971.5 ;
 RECT 1574.676 0.5 1574.796 971.5 ;
 RECT 1578.996 0.5 1579.116 971.5 ;
 RECT 1583.316 0.5 1583.436 971.5 ;
 RECT 1587.636 0.5 1587.756 971.5 ;
 RECT 1591.956 0.5 1592.076 971.5 ;
 RECT 1596.276 0.5 1596.396 971.5 ;
 RECT 1600.596 0.5 1600.716 971.5 ;
 RECT 1604.916 0.5 1605.036 971.5 ;
 RECT 1609.236 0.5 1609.356 971.5 ;
 RECT 1613.556 0.5 1613.676 971.5 ;
 RECT 1617.876 0.5 1617.996 971.5 ;
 RECT 1622.196 0.5 1622.316 971.5 ;
 RECT 1626.516 0.5 1626.636 971.5 ;
 RECT 1630.836 0.5 1630.956 971.5 ;
 RECT 1635.156 0.5 1635.276 971.5 ;
 RECT 1639.476 0.5 1639.596 971.5 ;
 RECT 1643.796 0.5 1643.916 971.5 ;
 RECT 1648.116 0.5 1648.236 971.5 ;
 RECT 1652.436 0.5 1652.556 971.5 ;
 RECT 1656.756 0.5 1656.876 971.5 ;
 RECT 1661.076 0.5 1661.196 971.5 ;
 RECT 1665.396 0.5 1665.516 971.5 ;
 RECT 1669.716 0.5 1669.836 971.5 ;
 RECT 1674.036 0.5 1674.156 971.5 ;
 RECT 1678.356 0.5 1678.476 971.5 ;
 RECT 1682.676 0.5 1682.796 971.5 ;
 RECT 1686.996 0.5 1687.116 971.5 ;
 RECT 1691.316 0.5 1691.436 971.5 ;
 RECT 1695.636 0.5 1695.756 971.5 ;
 RECT 1699.956 0.5 1700.076 971.5 ;
 RECT 1704.276 0.5 1704.396 971.5 ;
 RECT 1708.596 0.5 1708.716 971.5 ;
 RECT 1712.916 0.5 1713.036 971.5 ;
 RECT 1717.236 0.5 1717.356 971.5 ;
 RECT 1721.556 0.5 1721.676 971.5 ;
 RECT 1725.876 0.5 1725.996 971.5 ;
 RECT 1730.196 0.5 1730.316 971.5 ;
 RECT 1734.516 0.5 1734.636 971.5 ;
 RECT 1738.836 0.5 1738.956 971.5 ;
 RECT 1743.156 0.5 1743.276 971.5 ;
 RECT 1747.476 0.5 1747.596 971.5 ;
 RECT 1751.796 0.5 1751.916 971.5 ;
 RECT 1756.116 0.5 1756.236 971.5 ;
 RECT 1760.436 0.5 1760.556 971.5 ;
 RECT 1764.756 0.5 1764.876 971.5 ;
 RECT 1769.076 0.5 1769.196 971.5 ;
 RECT 1773.396 0.5 1773.516 971.5 ;
 RECT 1777.716 0.5 1777.836 971.5 ;
 RECT 1782.036 0.5 1782.156 971.5 ;
 RECT 1786.356 0.5 1786.476 971.5 ;
 RECT 1790.676 0.5 1790.796 971.5 ;
 RECT 1794.996 0.5 1795.116 971.5 ;
 RECT 1799.316 0.5 1799.436 971.5 ;
 RECT 1803.636 0.5 1803.756 971.5 ;
 RECT 1807.956 0.5 1808.076 971.5 ;
 RECT 1812.276 0.5 1812.396 971.5 ;
 RECT 1816.596 0.5 1816.716 971.5 ;
 RECT 1820.916 0.5 1821.036 971.5 ;
 RECT 1825.236 0.5 1825.356 971.5 ;
 RECT 1829.556 0.5 1829.676 971.5 ;
 RECT 1833.876 0.5 1833.996 971.5 ;
 RECT 1838.196 0.5 1838.316 971.5 ;
 RECT 1842.516 0.5 1842.636 971.5 ;
 RECT 1846.836 0.5 1846.956 971.5 ;
 RECT 1851.156 0.5 1851.276 971.5 ;
 RECT 1855.476 0.5 1855.596 971.5 ;
 RECT 1859.796 0.5 1859.916 971.5 ;
 RECT 1864.116 0.5 1864.236 971.5 ;
 END
 END VSS
 OBS
 LAYER M1 ;
 RECT 0 0 1866.24 972.0 ;
 LAYER M2 ;
 RECT 0 0 1866.24 972.0 ;
 LAYER M3 ;
 RECT 0 0 1866.24 972.0 ;
 LAYER M4 ;
 RECT 0 0 1865.64 972.0 ;
 LAYER M5 ;
 RECT 0 0 1866.24 972.0 ;
 LAYER M6 ;
 RECT 0 0 1866.24 972.0 ;
 END
END ot_qfd_serdes_112g_x6_phy_w522
END LIBRARY
